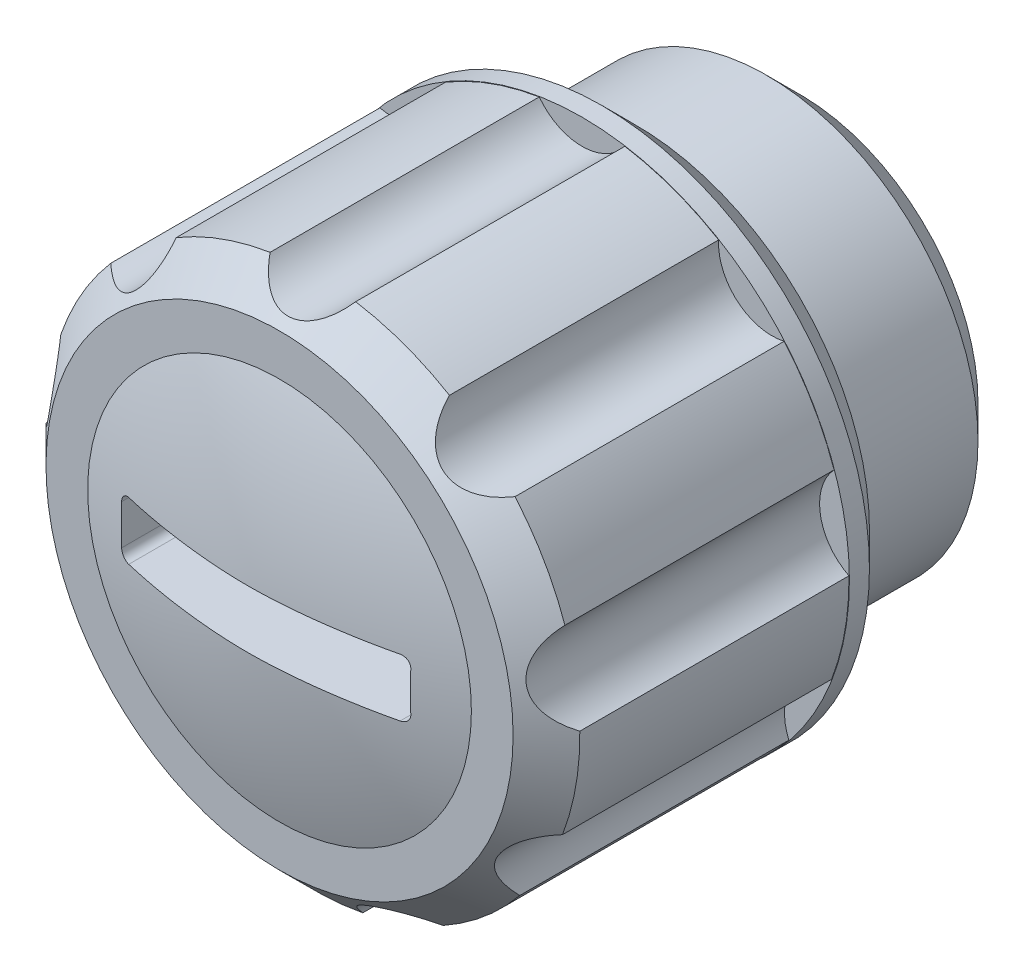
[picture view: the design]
ISO-10303-21;
HEADER;
FILE_DESCRIPTION(('STEP AP214'),'2;1');
FILE_NAME('part.step','',(''),(''),'','','');
FILE_SCHEMA(('AUTOMOTIVE_DESIGN { 1 0 10303 214 1 1 1 1 }'));
ENDSEC;
DATA;
#1=APPLICATION_CONTEXT('core data for automotive mechanical design processes');
#2=APPLICATION_PROTOCOL_DEFINITION('international standard','automotive_design',2000,#1);
#3=PRODUCT_CONTEXT('',#1,'mechanical');
#4=PRODUCT('Part','Part','',(#3));
#5=PRODUCT_RELATED_PRODUCT_CATEGORY('part','',(#4));
#6=PRODUCT_DEFINITION_FORMATION('','',#4);
#7=PRODUCT_DEFINITION_CONTEXT('part definition',#1,'design');
#8=PRODUCT_DEFINITION('design','',#6,#7);
#9=PRODUCT_DEFINITION_SHAPE('','',#8);
#10=(LENGTH_UNIT() NAMED_UNIT(*) SI_UNIT(.MILLI.,.METRE.));
#11=(NAMED_UNIT(*) PLANE_ANGLE_UNIT() SI_UNIT($,.RADIAN.));
#12=(NAMED_UNIT(*) SI_UNIT($,.STERADIAN.) SOLID_ANGLE_UNIT());
#13=UNCERTAINTY_MEASURE_WITH_UNIT(LENGTH_MEASURE(1.E-05),#10,'distance_accuracy_value','');
#14=(GEOMETRIC_REPRESENTATION_CONTEXT(3) GLOBAL_UNCERTAINTY_ASSIGNED_CONTEXT((#13)) GLOBAL_UNIT_ASSIGNED_CONTEXT((#10,
#11,#12)) REPRESENTATION_CONTEXT('',''));
#15=CARTESIAN_POINT('',(0.,0.,0.));
#16=DIRECTION('',(0.,0.,1.));
#17=DIRECTION('',(1.,0.,0.));
#18=AXIS2_PLACEMENT_3D('',#15,#16,#17);
#19=CARTESIAN_POINT('',(0.,0.,-2.24502330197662));
#20=DIRECTION('',(0.,0.,1.));
#21=DIRECTION('',(1.,0.,0.));
#22=AXIS2_PLACEMENT_3D('',#19,#20,#21);
#23=DEGENERATE_TOROIDAL_SURFACE('',#22,0.386362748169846,14.9999999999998,.F.);
#24=CARTESIAN_POINT('',(0.,0.,12.));
#25=DIRECTION('',(0.,0.,1.));
#26=DIRECTION('',(1.,0.,0.));
#27=AXIS2_PLACEMENT_3D('',#24,#25,#26);
#28=CIRCLE('',#27,4.3125);
#29=CARTESIAN_POINT('',(4.3125,0.,12.));
#30=VERTEX_POINT('',#29);
#31=EDGE_CURVE('E356',#30,#30,#28,.T.);
#32=ORIENTED_EDGE('',*,*,#31,.T.);
#33=EDGE_LOOP('',(#32));
#34=FACE_BOUND('',#33,.T.);
#35=CARTESIAN_POINT('',(-3.0498,-0.649999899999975,12.3398097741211));
#36=CARTESIAN_POINT('',(-3.06120822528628,-0.650019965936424,12.3371277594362));
#37=CARTESIAN_POINT('',(-3.07262553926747,-0.649047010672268,12.3344789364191));
#38=CARTESIAN_POINT('',(-3.09516164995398,-0.645167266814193,12.3293198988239));
#39=CARTESIAN_POINT('',(-3.10628037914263,-0.642260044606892,12.326809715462));
#40=CARTESIAN_POINT('',(-3.1279071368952,-0.634560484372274,12.3219992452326));
#41=CARTESIAN_POINT('',(-3.13841459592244,-0.629766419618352,12.3196991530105));
#42=CARTESIAN_POINT('',(-3.15848770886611,-0.618413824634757,12.3153819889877));
#43=CARTESIAN_POINT('',(-3.16805381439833,-0.611856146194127,12.3133647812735));
#44=CARTESIAN_POINT('',(-3.18579781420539,-0.59727066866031,12.3097075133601));
#45=CARTESIAN_POINT('',(-3.19399634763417,-0.589269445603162,12.308061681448));
#46=CARTESIAN_POINT('',(-3.20893719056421,-0.571941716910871,12.3051577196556));
#47=CARTESIAN_POINT('',(-3.2156793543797,-0.562615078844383,12.303899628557));
#48=CARTESIAN_POINT('',(-3.22732440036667,-0.543172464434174,12.3018421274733));
#49=CARTESIAN_POINT('',(-3.23227144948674,-0.533084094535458,12.3010314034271));
#50=CARTESIAN_POINT('',(-3.24041051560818,-0.512202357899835,12.2998457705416));
#51=CARTESIAN_POINT('',(-3.24360397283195,-0.501409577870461,12.299470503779));
#52=CARTESIAN_POINT('',(-3.24725089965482,-0.483746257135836,12.2992265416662));
#53=CARTESIAN_POINT('',(-3.24828749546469,-0.476992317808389,12.2992171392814));
#54=CARTESIAN_POINT('',(-3.24966526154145,-0.4634255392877,12.2993633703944));
#55=CARTESIAN_POINT('',(-3.25000743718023,-0.456612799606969,12.2995187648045));
#56=CARTESIAN_POINT('',(-3.24999990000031,-0.449800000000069,12.2997561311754));
#57=B_SPLINE_CURVE_WITH_KNOTS('',3,(#35,#36,#37,#38,#39,#40,#41,#42,#43,#44,#45,#46,#47,#48,#49,
#50,#51,#52,#53,#54,#55,#56),.UNSPECIFIED.,.F.,.F.,(4,2,2,2,2,2,2,2,2,2,4),(0.,
0.0351172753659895,0.0702424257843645,0.10539979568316,0.140540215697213,0.175089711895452,
0.209642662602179,0.243276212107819,0.276882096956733,0.297346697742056,0.317781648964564),.UNSPECIFIED.);
#58=CARTESIAN_POINT('',(-3.05,-0.65,12.3397627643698));
#59=VERTEX_POINT('',#58);
#60=CARTESIAN_POINT('',(-3.25,-0.45,12.2997491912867));
#61=VERTEX_POINT('',#60);
#62=EDGE_CURVE('E27',#59,#61,#57,.T.);
#63=ORIENTED_EDGE('',*,*,#62,.T.);
#64=CARTESIAN_POINT('',(-3.25,0.,12.3075320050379));
#65=CARTESIAN_POINT('',(-3.25,0.277728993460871,12.3075356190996));
#66=CARTESIAN_POINT('',(-3.25,0.555440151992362,12.2986179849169));
#67=CARTESIAN_POINT('',(-3.25,1.10971337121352,12.2631914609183));
#68=CARTESIAN_POINT('',(-3.25,1.38627553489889,12.2366841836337));
#69=CARTESIAN_POINT('',(-3.25,1.93745588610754,12.1665755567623));
#70=CARTESIAN_POINT('',(-3.25,2.21207222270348,12.122959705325));
#71=CARTESIAN_POINT('',(-3.25,2.75819405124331,12.019207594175));
#72=CARTESIAN_POINT('',(-3.25,3.02969897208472,11.9590683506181));
#73=CARTESIAN_POINT('',(-3.25,3.68907942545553,11.7923343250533));
#74=CARTESIAN_POINT('',(-3.25,4.07477310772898,11.6769874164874));
#75=CARTESIAN_POINT('',(-3.25,4.83507528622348,11.4141726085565));
#76=CARTESIAN_POINT('',(-3.25,5.20968196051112,11.2666994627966));
#77=CARTESIAN_POINT('',(-3.25,5.94561682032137,10.9408021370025));
#78=CARTESIAN_POINT('',(-3.25,6.30693188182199,10.7623483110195));
#79=CARTESIAN_POINT('',(-3.25,7.013278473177,10.3760839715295));
#80=CARTESIAN_POINT('',(-3.25,7.35831779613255,10.1682877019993));
#81=CARTESIAN_POINT('',(-3.25,8.03118455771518,9.72399493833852));
#82=CARTESIAN_POINT('',(-3.25,8.35894545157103,9.48739766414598));
#83=CARTESIAN_POINT('',(-3.25,8.99368126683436,8.98778857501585));
#84=CARTESIAN_POINT('',(-3.25,9.30065586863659,8.72477635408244));
#85=CARTESIAN_POINT('',(-3.25,9.8916546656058,8.1742495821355));
#86=CARTESIAN_POINT('',(-3.25,10.1756840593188,7.88674061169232));
#87=CARTESIAN_POINT('',(-3.25,10.7189336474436,7.2891687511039));
#88=CARTESIAN_POINT('',(-3.25,10.9781537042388,6.97910573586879));
#89=CARTESIAN_POINT('',(-3.25,11.4737062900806,6.33376323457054));
#90=CARTESIAN_POINT('',(-3.25,11.7096373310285,5.9981753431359));
#91=CARTESIAN_POINT('',(-3.25,12.1524595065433,5.30835452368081));
#92=CARTESIAN_POINT('',(-3.25,12.3593503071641,4.95412138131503));
#93=CARTESIAN_POINT('',(-3.25,12.7426542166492,4.22948724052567));
#94=CARTESIAN_POINT('',(-3.25,12.9190643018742,3.85908464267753));
#95=CARTESIAN_POINT('',(-3.25,13.2401398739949,3.10476845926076));
#96=CARTESIAN_POINT('',(-3.25,13.3848053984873,2.72085488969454));
#97=CARTESIAN_POINT('',(-3.25,13.6416809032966,1.94130139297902));
#98=CARTESIAN_POINT('',(-3.25,13.753812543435,1.5456356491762));
#99=CARTESIAN_POINT('',(-3.25,13.944363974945,0.746267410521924));
#100=CARTESIAN_POINT('',(-3.25,14.0227836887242,0.342564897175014));
#101=CARTESIAN_POINT('',(-3.25,14.1453548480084,-0.469998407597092));
#102=CARTESIAN_POINT('',(-3.25,14.1895071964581,-0.8788590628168));
#103=CARTESIAN_POINT('',(-3.25,14.2432347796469,-1.69884576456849));
#104=CARTESIAN_POINT('',(-3.25,14.2528100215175,-2.10997181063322));
#105=CARTESIAN_POINT('',(-3.25,14.2373111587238,-2.93180992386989));
#106=CARTESIAN_POINT('',(-3.25,14.2122168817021,-3.34252161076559));
#107=CARTESIAN_POINT('',(-3.25,14.1275207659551,-4.16037161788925));
#108=CARTESIAN_POINT('',(-3.25,14.0679189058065,-4.56750993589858));
#109=CARTESIAN_POINT('',(-3.25,13.9146256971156,-5.37533907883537));
#110=CARTESIAN_POINT('',(-3.25,13.8209326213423,-5.77602957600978));
#111=CARTESIAN_POINT('',(-3.25,13.6001207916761,-6.568092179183));
#112=CARTESIAN_POINT('',(-3.25,13.4730020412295,-6.95946428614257));
#113=CARTESIAN_POINT('',(-3.25,13.186232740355,-7.7301217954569));
#114=CARTESIAN_POINT('',(-3.25,13.0265808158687,-8.10940668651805));
#115=CARTESIAN_POINT('',(-3.25,12.6758786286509,-8.85317181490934));
#116=CARTESIAN_POINT('',(-3.25,12.4848283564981,-9.21765204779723));
#117=CARTESIAN_POINT('',(-3.25,12.072711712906,-9.92915798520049));
#118=CARTESIAN_POINT('',(-3.25,11.8516496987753,-10.2761862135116));
#119=CARTESIAN_POINT('',(-3.25,11.3810523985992,-10.9503675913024));
#120=CARTESIAN_POINT('',(-3.25,11.1315171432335,-11.2775207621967));
#121=CARTESIAN_POINT('',(-3.25,10.6059307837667,-11.9093794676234));
#122=CARTESIAN_POINT('',(-3.25,10.3298992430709,-12.2141012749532));
#123=CARTESIAN_POINT('',(-3.25,9.75311451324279,-12.7991756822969));
#124=CARTESIAN_POINT('',(-3.25,9.45236128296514,-13.0795282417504));
#125=CARTESIAN_POINT('',(-3.25,8.82813062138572,-13.6139441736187));
#126=CARTESIAN_POINT('',(-3.25,8.50464416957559,-13.8679970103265));
#127=CARTESIAN_POINT('',(-3.25,7.8373363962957,-14.3478241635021));
#128=CARTESIAN_POINT('',(-3.25,7.49351512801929,-14.573598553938));
#129=CARTESIAN_POINT('',(-3.25,6.78879460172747,-14.9946762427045));
#130=CARTESIAN_POINT('',(-3.25,6.42793763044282,-15.1900503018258));
#131=CARTESIAN_POINT('',(-3.25,5.69092259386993,-15.5494366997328));
#132=CARTESIAN_POINT('',(-3.25,5.31476441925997,-15.7134488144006));
#133=CARTESIAN_POINT('',(-3.25,4.54996490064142,-16.0086112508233));
#134=CARTESIAN_POINT('',(-3.25,4.16132971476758,-16.1397775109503));
#135=CARTESIAN_POINT('',(-3.25,3.37414151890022,-16.367940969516));
#136=CARTESIAN_POINT('',(-3.25,2.97558824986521,-16.4649372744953));
#137=CARTESIAN_POINT('',(-3.25,2.17796770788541,-16.6218590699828));
#138=CARTESIAN_POINT('',(-3.25,1.77901685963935,-16.682368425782));
#139=CARTESIAN_POINT('',(-3.25,1.17783289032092,-16.7458571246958));
#140=CARTESIAN_POINT('',(-3.25,0.976962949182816,-16.7624743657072));
#141=CARTESIAN_POINT('',(-3.25,0.574677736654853,-16.7864370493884));
#142=CARTESIAN_POINT('',(-3.25,0.373262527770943,-16.7937835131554));
#143=CARTESIAN_POINT('',(-3.25,-0.0296307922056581,-16.7991040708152));
#144=CARTESIAN_POINT('',(-3.25,-0.231108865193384,-16.7970810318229));
#145=CARTESIAN_POINT('',(-3.25,-0.633740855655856,-16.7837024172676));
#146=CARTESIAN_POINT('',(-3.25,-0.834894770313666,-16.7723467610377));
#147=CARTESIAN_POINT('',(-3.25,-1.43727360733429,-16.7244784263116));
#148=CARTESIAN_POINT('',(-3.25,-1.83748615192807,-16.6741652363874));
#149=CARTESIAN_POINT('',(-3.25,-2.60244344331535,-16.5434913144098));
#150=CARTESIAN_POINT('',(-3.25,-2.9676242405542,-16.465624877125));
#151=CARTESIAN_POINT('',(-3.25,-3.69061293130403,-16.2811099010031));
#152=CARTESIAN_POINT('',(-3.25,-4.04842149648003,-16.1744639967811));
#153=CARTESIAN_POINT('',(-3.25,-4.75476881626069,-15.9334225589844));
#154=CARTESIAN_POINT('',(-3.25,-5.10330243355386,-15.7990119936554));
#155=CARTESIAN_POINT('',(-3.25,-5.78889033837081,-15.5035347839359));
#156=CARTESIAN_POINT('',(-3.25,-6.12594408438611,-15.3424668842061));
#157=CARTESIAN_POINT('',(-3.25,-6.80932679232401,-14.9828170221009));
#158=CARTESIAN_POINT('',(-3.25,-7.15470066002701,-14.7824174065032));
#159=CARTESIAN_POINT('',(-3.25,-7.82779768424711,-14.3538815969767));
#160=CARTESIAN_POINT('',(-3.25,-8.15552013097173,-14.1257442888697));
#161=CARTESIAN_POINT('',(-3.25,-8.79107255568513,-13.6433774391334));
#162=CARTESIAN_POINT('',(-3.25,-9.09890611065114,-13.3891526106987));
#163=CARTESIAN_POINT('',(-3.25,-9.69269581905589,-12.8563257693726));
#164=CARTESIAN_POINT('',(-3.25,-9.97865187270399,-12.5777236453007));
#165=CARTESIAN_POINT('',(-3.25,-10.5337680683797,-11.9906483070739));
#166=CARTESIAN_POINT('',(-3.25,-10.8023152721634,-11.6815951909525));
#167=CARTESIAN_POINT('',(-3.25,-11.3125257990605,-11.0420356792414));
#168=CARTESIAN_POINT('',(-3.25,-11.5541885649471,-10.7115288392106));
#169=CARTESIAN_POINT('',(-3.25,-12.0089741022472,-10.0313455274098));
#170=CARTESIAN_POINT('',(-3.25,-12.2220918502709,-9.6816656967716));
#171=CARTESIAN_POINT('',(-3.25,-12.6182423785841,-8.96566280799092));
#172=CARTESIAN_POINT('',(-3.25,-12.8012752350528,-8.59933979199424));
#173=CARTESIAN_POINT('',(-3.25,-13.1366167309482,-7.85119993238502));
#174=CARTESIAN_POINT('',(-3.25,-13.2888047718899,-7.46932902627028));
#175=CARTESIAN_POINT('',(-3.25,-13.5604975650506,-6.69413124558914));
#176=CARTESIAN_POINT('',(-3.25,-13.680002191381,-6.30080432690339));
#177=CARTESIAN_POINT('',(-3.25,-13.885478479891,-5.505506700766));
#178=CARTESIAN_POINT('',(-3.25,-13.9714517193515,-5.10353640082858));
#179=CARTESIAN_POINT('',(-3.25,-14.1092657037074,-4.29378701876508));
#180=CARTESIAN_POINT('',(-3.25,-14.1611064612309,-3.88600793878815));
#181=CARTESIAN_POINT('',(-3.25,-14.2303212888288,-3.06715435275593));
#182=CARTESIAN_POINT('',(-3.25,-14.2476633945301,-2.65607714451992));
#183=CARTESIAN_POINT('',(-3.25,-14.2476620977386,-1.83392251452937));
#184=CARTESIAN_POINT('',(-3.25,-14.2303186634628,-1.42284509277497));
#185=CARTESIAN_POINT('',(-3.25,-14.1610682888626,-0.603603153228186));
#186=CARTESIAN_POINT('',(-3.25,-14.1091606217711,-0.195438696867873));
#187=CARTESIAN_POINT('',(-3.25,-13.9711485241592,0.615067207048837));
#188=CARTESIAN_POINT('',(-3.25,-13.885044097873,1.01740865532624));
#189=CARTESIAN_POINT('',(-3.25,-13.6792331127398,1.81346557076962));
#190=CARTESIAN_POINT('',(-3.25,-13.5595217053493,2.20717978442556));
#191=CARTESIAN_POINT('',(-3.25,-13.2873494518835,2.98312116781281));
#192=CARTESIAN_POINT('',(-3.25,-13.1348885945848,3.36534833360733));
#193=CARTESIAN_POINT('',(-3.25,-12.7982999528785,4.11558729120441));
#194=CARTESIAN_POINT('',(-3.25,-12.6141727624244,4.48359934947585));
#195=CARTESIAN_POINT('',(-3.25,-12.2155528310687,5.20279306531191));
#196=CARTESIAN_POINT('',(-3.25,-12.0010601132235,5.55397473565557));
#197=CARTESIAN_POINT('',(-3.25,-11.5433180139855,6.2368658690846));
#198=CARTESIAN_POINT('',(-3.25,-11.3000801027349,6.56858302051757));
#199=CARTESIAN_POINT('',(-3.25,-10.7864981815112,7.2103264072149));
#200=CARTESIAN_POINT('',(-3.25,-10.5161541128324,7.52035259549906));
#201=CARTESIAN_POINT('',(-3.25,-9.95025306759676,8.11650757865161));
#202=CARTESIAN_POINT('',(-3.25,-9.65469453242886,8.4026348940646));
#203=CARTESIAN_POINT('',(-3.25,-9.04046877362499,8.94890264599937));
#204=CARTESIAN_POINT('',(-3.25,-8.72180175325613,9.20904331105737));
#205=CARTESIAN_POINT('',(-3.25,-8.06411837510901,9.70105813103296));
#206=CARTESIAN_POINT('',(-3.25,-7.72513441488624,9.93297559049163));
#207=CARTESIAN_POINT('',(-3.25,-7.02875492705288,10.3672880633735));
#208=CARTESIAN_POINT('',(-3.25,-6.67135962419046,10.5696834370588));
#209=CARTESIAN_POINT('',(-3.25,-5.94066060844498,10.9433896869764));
#210=CARTESIAN_POINT('',(-3.25,-5.56735649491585,11.1146997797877));
#211=CARTESIAN_POINT('',(-3.25,-4.80749189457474,11.4247686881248));
#212=CARTESIAN_POINT('',(-3.25,-4.42093314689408,11.5635317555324));
#213=CARTESIAN_POINT('',(-3.25,-3.70318039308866,11.786627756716));
#214=CARTESIAN_POINT('',(-3.25,-3.37360154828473,11.876189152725));
#215=CARTESIAN_POINT('',(-3.25,-2.70877137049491,12.0309482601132));
#216=CARTESIAN_POINT('',(-3.25,-2.37352047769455,12.0961478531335));
#217=CARTESIAN_POINT('',(-3.25,-1.69957377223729,12.2010954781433));
#218=CARTESIAN_POINT('',(-3.25,-1.36088404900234,12.2408824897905));
#219=CARTESIAN_POINT('',(-3.25,-0.681453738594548,12.2940966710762));
#220=CARTESIAN_POINT('',(-3.25,-0.340713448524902,12.3075275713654));
#221=CARTESIAN_POINT('',(-3.25,0.,12.3075320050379));
#222=B_SPLINE_CURVE_WITH_KNOTS('',3,(#64,#65,#66,#67,#68,#69,#70,#71,#72,#73,#74,#75,#76,#77,
#78,#79,#80,#81,#82,#83,#84,#85,#86,#87,#88,#89,#90,#91,#92,#93,#94,#95,#96,#97,#98,#99,#100,
#101,#102,#103,#104,#105,#106,#107,#108,#109,#110,#111,#112,#113,#114,#115,#116,#117,#118,#119,
#120,#121,#122,#123,#124,#125,#126,#127,#128,#129,#130,#131,#132,#133,#134,#135,#136,#137,#138,
#139,#140,#141,#142,#143,#144,#145,#146,#147,#148,#149,#150,#151,#152,#153,#154,#155,#156,#157,
#158,#159,#160,#161,#162,#163,#164,#165,#166,#167,#168,#169,#170,#171,#172,#173,#174,#175,#176,
#177,#178,#179,#180,#181,#182,#183,#184,#185,#186,#187,#188,#189,#190,#191,#192,#193,#194,#195,
#196,#197,#198,#199,#200,#201,#202,#203,#204,#205,#206,#207,#208,#209,#210,#211,#212,#213,#214,
#215,#216,#217,#218,#219,#220,#221),.UNSPECIFIED.,.T.,.F.,(4,2,2,2,2,2,2,2,2,2,2,2,2,2,2,2,2,2,
2,2,2,2,2,2,2,2,2,2,2,2,2,2,2,2,2,2,2,2,2,2,2,2,2,2,2,2,2,2,2,2,2,2,2,2,2,2,2,2,2,2,2,2,2,2,2,2,
2,2,2,2,2,2,2,2,2,2,2,2,4),(0.,0.833015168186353,1.66595398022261,2.49960035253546,
3.33339736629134,4.53957397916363,5.74594771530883,6.95348227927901,8.16043266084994,
9.37173482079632,10.583055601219,11.7941011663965,13.0051534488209,14.2343656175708,
15.4635919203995,16.6929400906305,17.9222868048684,19.15456962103,20.3868552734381,
21.6191084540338,22.8513613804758,24.0843315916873,25.3173025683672,26.5503360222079,
27.7833693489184,29.01645476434,30.2495405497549,31.4824474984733,32.7153531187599,
33.9473553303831,35.1793595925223,36.4118555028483,37.6443481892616,38.8739277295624,
40.1035160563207,41.3325065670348,42.5615292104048,43.7703236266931,44.3748145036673,
44.97923879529,45.583478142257,46.1877227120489,47.3960010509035,48.5150195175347,
49.6339355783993,50.7534590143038,51.8730351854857,53.0695719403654,54.2661567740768,
55.4625258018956,56.658900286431,57.8857327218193,59.1125905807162,60.3396640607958,
61.5667344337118,62.7985136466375,64.0302976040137,65.2620236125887,66.4937491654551,
67.7266154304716,68.9594828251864,70.1923761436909,71.4252693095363,72.6583404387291,
73.8914119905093,75.1244604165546,76.3575079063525,77.5900650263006,78.8226248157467,
80.05526085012,81.2878860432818,82.5185954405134,83.7492898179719,84.9800152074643,
86.2105797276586,87.2343070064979,88.2579551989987,89.2800294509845,90.3019590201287),.UNSPECIFIED.);
#223=CARTESIAN_POINT('',(-3.25,0.45,12.2997491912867));
#224=VERTEX_POINT('',#223);
#225=EDGE_CURVE('E9',#61,#224,#222,.T.);
#226=ORIENTED_EDGE('',*,*,#225,.T.);
#227=CARTESIAN_POINT('',(-3.24999989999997,0.4498,12.2997561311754));
#228=CARTESIAN_POINT('',(-3.25002147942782,0.460776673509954,12.2993714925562));
#229=CARTESIAN_POINT('',(-3.24911882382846,0.471758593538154,12.2992032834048));
#230=CARTESIAN_POINT('',(-3.24553635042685,0.493412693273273,12.2992941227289));
#231=CARTESIAN_POINT('',(-3.24285883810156,0.504085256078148,12.299552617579));
#232=CARTESIAN_POINT('',(-3.23579622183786,0.524834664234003,12.3004904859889));
#233=CARTESIAN_POINT('',(-3.23141042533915,0.53491126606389,12.3011700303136));
#234=CARTESIAN_POINT('',(-3.22107038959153,0.554184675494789,12.3029273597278));
#235=CARTESIAN_POINT('',(-3.21511623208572,0.563381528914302,12.3040051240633));
#236=CARTESIAN_POINT('',(-3.20177417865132,0.580709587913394,12.3065339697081));
#237=CARTESIAN_POINT('',(-3.19437690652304,0.588833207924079,12.3079875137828));
#238=CARTESIAN_POINT('',(-3.17839327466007,0.603735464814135,12.3112205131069));
#239=CARTESIAN_POINT('',(-3.16980667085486,0.610513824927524,12.3130000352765));
#240=CARTESIAN_POINT('',(-3.15148706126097,0.62269653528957,12.3168763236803));
#241=CARTESIAN_POINT('',(-3.14173272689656,0.628066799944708,12.3189792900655));
#242=CARTESIAN_POINT('',(-3.12151319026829,0.637105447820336,12.3234120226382));
#243=CARTESIAN_POINT('',(-3.11104805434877,0.640773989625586,12.3257417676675));
#244=CARTESIAN_POINT('',(-3.09210451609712,0.64570458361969,12.3300193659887));
#245=CARTESIAN_POINT('',(-3.08370936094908,0.647322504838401,12.3319350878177));
#246=CARTESIAN_POINT('',(-3.06680849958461,0.649474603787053,12.3358309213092));
#247=CARTESIAN_POINT('',(-3.05830296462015,0.650010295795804,12.3378109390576));
#248=CARTESIAN_POINT('',(-3.0498,0.649999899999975,12.3398097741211));
#249=B_SPLINE_CURVE_WITH_KNOTS('',3,(#227,#228,#229,#230,#231,#232,#233,#234,#235,#236,#237,
#238,#239,#240,#241,#242,#243,#244,#245,#246,#247,#248),.UNSPECIFIED.,.F.,.F.,(4,2,2,2,2,2,2,2,
2,2,4),(0.,0.0329053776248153,0.0657680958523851,0.0986441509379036,0.13151849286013,
0.1646140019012,0.197716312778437,0.231558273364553,0.265397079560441,0.291616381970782,
0.31779897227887),.UNSPECIFIED.);
#250=CARTESIAN_POINT('',(-3.04999999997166,0.65,12.3397627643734));
#251=VERTEX_POINT('',#250);
#252=EDGE_CURVE('E419',#224,#251,#249,.T.);
#253=ORIENTED_EDGE('',*,*,#252,.T.);
#254=CARTESIAN_POINT('',(0.,0.65,12.7191322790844));
#255=CARTESIAN_POINT('',(0.108520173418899,0.65,12.7191277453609));
#256=CARTESIAN_POINT('',(0.217041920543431,0.65,12.7172094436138));
#257=CARTESIAN_POINT('',(0.433997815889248,0.65,12.7099981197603));
#258=CARTESIAN_POINT('',(0.542431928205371,0.65,12.7047040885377));
#259=CARTESIAN_POINT('',(0.759555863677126,0.65,12.6912706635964));
#260=CARTESIAN_POINT('',(0.868244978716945,0.65,12.6831199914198));
#261=CARTESIAN_POINT('',(1.08539837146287,0.65,12.6642185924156));
#262=CARTESIAN_POINT('',(1.19386263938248,0.65,12.6534677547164));
#263=CARTESIAN_POINT('',(1.51887735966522,0.65,12.6174925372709));
#264=CARTESIAN_POINT('',(1.73502604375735,0.65,12.5885469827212));
#265=CARTESIAN_POINT('',(2.16611297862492,0.65,12.5210525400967));
#266=CARTESIAN_POINT('',(2.38104917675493,0.65,12.4824906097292));
#267=CARTESIAN_POINT('',(2.80901885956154,0.65,12.3959374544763));
#268=CARTESIAN_POINT('',(3.02205219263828,0.65,12.3479454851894));
#269=CARTESIAN_POINT('',(3.64169701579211,0.65,12.1939819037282));
#270=CARTESIAN_POINT('',(4.04525595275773,0.65,12.0754170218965));
#271=CARTESIAN_POINT('',(4.84106887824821,0.65,11.804706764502));
#272=CARTESIAN_POINT('',(5.23331827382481,0.65,11.6525479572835));
#273=CARTESIAN_POINT('',(6.00390173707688,0.65,11.3156534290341));
#274=CARTESIAN_POINT('',(6.382226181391,0.65,11.1308956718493));
#275=CARTESIAN_POINT('',(7.12194189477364,0.65,10.7302214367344));
#276=CARTESIAN_POINT('',(7.48333496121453,0.65,10.5143082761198));
#277=CARTESIAN_POINT('',(8.18679974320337,0.65,10.0527629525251));
#278=CARTESIAN_POINT('',(8.52886465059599,0.65,9.80712041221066));
#279=CARTESIAN_POINT('',(9.19111928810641,0.65,9.28791513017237));
#280=CARTESIAN_POINT('',(9.51130841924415,0.65,9.01435162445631));
#281=CARTESIAN_POINT('',(10.1275007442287,0.65,8.44128082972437));
#282=CARTESIAN_POINT('',(10.4235063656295,0.65,8.14177615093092));
#283=CARTESIAN_POINT('',(10.9892674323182,0.65,7.51892636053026));
#284=CARTESIAN_POINT('',(11.2590230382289,0.65,7.19558139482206));
#285=CARTESIAN_POINT('',(11.7706885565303,0.65,6.52693164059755));
#286=CARTESIAN_POINT('',(12.012563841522,0.65,6.18160035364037));
#287=CARTESIAN_POINT('',(12.4663665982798,0.65,5.47179015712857));
#288=CARTESIAN_POINT('',(12.6782939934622,0.65,5.10731119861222));
#289=CARTESIAN_POINT('',(13.0706918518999,0.65,4.36180202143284));
#290=CARTESIAN_POINT('',(13.2511627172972,0.65,3.98077201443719));
#291=CARTESIAN_POINT('',(13.5793682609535,0.65,3.20486500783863));
#292=CARTESIAN_POINT('',(13.7271029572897,0.65,2.80998801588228));
#293=CARTESIAN_POINT('',(13.988800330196,0.65,2.00915107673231));
#294=CARTESIAN_POINT('',(14.1027594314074,0.65,1.60318996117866));
#295=CARTESIAN_POINT('',(14.2960746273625,0.65,0.783110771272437));
#296=CARTESIAN_POINT('',(14.3754307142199,0.65,0.368992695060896));
#297=CARTESIAN_POINT('',(14.498977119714,0.65,-0.464465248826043));
#298=CARTESIAN_POINT('',(14.5431666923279,0.65,-0.883805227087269));
#299=CARTESIAN_POINT('',(14.596063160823,0.65,-1.72471716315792));
#300=CARTESIAN_POINT('',(14.6047700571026,0.65,-2.1462891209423));
#301=CARTESIAN_POINT('',(14.5866390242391,0.65,-2.98868011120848));
#302=CARTESIAN_POINT('',(14.5598000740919,0.65,-3.40949912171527));
#303=CARTESIAN_POINT('',(14.4707663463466,0.65,-4.24738022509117));
#304=CARTESIAN_POINT('',(14.4085715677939,0.65,-4.66444231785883));
#305=CARTESIAN_POINT('',(14.2492707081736,0.65,-5.49183187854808));
#306=CARTESIAN_POINT('',(14.1521656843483,0.65,-5.90215955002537));
#307=CARTESIAN_POINT('',(13.92373427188,0.65,-6.7131760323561));
#308=CARTESIAN_POINT('',(13.7924078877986,0.65,-7.11386484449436));
#309=CARTESIAN_POINT('',(13.4964692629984,0.65,-7.90274953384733));
#310=CARTESIAN_POINT('',(13.3318574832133,0.65,-8.29094558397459));
#311=CARTESIAN_POINT('',(12.9705168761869,0.65,-9.05209088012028));
#312=CARTESIAN_POINT('',(12.7737880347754,0.65,-9.42504011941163));
#313=CARTESIAN_POINT('',(12.3495993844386,0.65,-10.1530610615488));
#314=CARTESIAN_POINT('',(12.1221378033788,0.65,-10.5081317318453));
#315=CARTESIAN_POINT('',(11.6381096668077,0.65,-11.1978469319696));
#316=CARTESIAN_POINT('',(11.3815431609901,0.65,-11.5324914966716));
#317=CARTESIAN_POINT('',(10.8411381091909,0.65,-12.1789638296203));
#318=CARTESIAN_POINT('',(10.5573005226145,0.65,-12.4907923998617));
#319=CARTESIAN_POINT('',(9.9643609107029,0.65,-13.0894299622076));
#320=CARTESIAN_POINT('',(9.65525870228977,0.65,-13.3762387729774));
#321=CARTESIAN_POINT('',(9.01399860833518,0.65,-13.9227850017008));
#322=CARTESIAN_POINT('',(8.681841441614,0.65,-14.1825232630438));
#323=CARTESIAN_POINT('',(7.99683299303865,0.65,-14.6730822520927));
#324=CARTESIAN_POINT('',(7.64398231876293,0.65,-14.9039038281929));
#325=CARTESIAN_POINT('',(6.92002553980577,0.65,-15.335028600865));
#326=CARTESIAN_POINT('',(6.5489163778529,0.65,-15.5353266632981));
#327=CARTESIAN_POINT('',(5.79113277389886,0.65,-15.903924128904));
#328=CARTESIAN_POINT('',(5.40445847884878,0.65,-16.0722238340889));
#329=CARTESIAN_POINT('',(4.61839618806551,0.65,-16.3755712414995));
#330=CARTESIAN_POINT('',(4.21901109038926,0.65,-16.5106264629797));
#331=CARTESIAN_POINT('',(3.41037855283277,0.65,-16.7464936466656));
#332=CARTESIAN_POINT('',(3.00113546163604,0.65,-16.8473204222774));
#333=CARTESIAN_POINT('',(2.37474825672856,0.65,-16.9737106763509));
#334=CARTESIAN_POINT('',(2.16011736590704,0.65,-17.0121235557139));
#335=CARTESIAN_POINT('',(1.72933145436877,0.65,-17.0793970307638));
#336=CARTESIAN_POINT('',(1.51317639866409,0.65,-17.1082574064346));
#337=CARTESIAN_POINT('',(1.1883245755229,0.65,-17.1440821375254));
#338=CARTESIAN_POINT('',(1.08002619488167,0.65,-17.1547737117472));
#339=CARTESIAN_POINT('',(0.863198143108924,0.65,-17.1735629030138));
#340=CARTESIAN_POINT('',(0.754668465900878,0.65,-17.1816604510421));
#341=CARTESIAN_POINT('',(0.537464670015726,0.65,-17.1950151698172));
#342=CARTESIAN_POINT('',(0.42879060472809,0.65,-17.2002731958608));
#343=CARTESIAN_POINT('',(0.211334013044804,0.65,-17.20738850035));
#344=CARTESIAN_POINT('',(0.102551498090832,0.65,-17.2092461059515));
#345=CARTESIAN_POINT('',(-0.098037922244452,0.65,-17.2091183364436));
#346=CARTESIAN_POINT('',(-0.189845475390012,0.65,-17.2076873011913));
#347=CARTESIAN_POINT('',(-0.373392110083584,0.65,-17.2023544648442));
#348=CARTESIAN_POINT('',(-0.465131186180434,0.65,-17.1984524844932));
#349=CARTESIAN_POINT('',(-0.648525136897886,0.65,-17.1885366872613));
#350=CARTESIAN_POINT('',(-0.740179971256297,0.65,-17.1825221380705));
#351=CARTESIAN_POINT('',(-0.923340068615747,0.65,-17.1685825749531));
#352=CARTESIAN_POINT('',(-1.01484533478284,0.65,-17.1606576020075));
#353=CARTESIAN_POINT('',(-1.28932831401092,0.65,-17.1341570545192));
#354=CARTESIAN_POINT('',(-1.47205047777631,0.65,-17.1128685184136));
#355=CARTESIAN_POINT('',(-1.83651738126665,0.65,-17.0634122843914));
#356=CARTESIAN_POINT('',(-2.01826229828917,0.65,-17.0352458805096));
#357=CARTESIAN_POINT('',(-2.38129600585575,0.65,-16.9720306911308));
#358=CARTESIAN_POINT('',(-2.56258014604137,0.65,-16.936955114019));
#359=CARTESIAN_POINT('',(-2.92371751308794,0.65,-16.8600846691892));
#360=CARTESIAN_POINT('',(-3.10357066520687,0.65,-16.8182894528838));
#361=CARTESIAN_POINT('',(-3.64033450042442,0.65,-16.6830040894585));
#362=CARTESIAN_POINT('',(-3.9947892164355,0.65,-16.57955495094));
#363=CARTESIAN_POINT('',(-4.71178689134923,0.65,-16.3411791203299));
#364=CARTESIAN_POINT('',(-5.07390702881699,0.65,-16.2049845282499));
#365=CARTESIAN_POINT('',(-5.78663052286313,0.65,-15.9049349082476));
#366=CARTESIAN_POINT('',(-6.13723052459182,0.65,-15.7410719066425));
#367=CARTESIAN_POINT('',(-6.82400082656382,0.65,-15.3870663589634));
#368=CARTESIAN_POINT('',(-7.16019896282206,0.65,-15.1969778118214));
#369=CARTESIAN_POINT('',(-7.81689468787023,0.65,-14.7914249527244));
#370=CARTESIAN_POINT('',(-8.13739298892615,0.65,-14.5759617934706));
#371=CARTESIAN_POINT('',(-8.7889588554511,0.65,-14.1003791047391));
#372=CARTESIAN_POINT('',(-9.118369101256,0.65,-13.8379842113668));
#373=CARTESIAN_POINT('',(-9.75396306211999,0.65,-13.2863857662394));
#374=CARTESIAN_POINT('',(-10.0601446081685,0.65,-12.9971797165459));
#375=CARTESIAN_POINT('',(-10.6473742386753,0.65,-12.3937305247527));
#376=CARTESIAN_POINT('',(-10.9283974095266,0.65,-12.0794631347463));
#377=CARTESIAN_POINT('',(-11.4629667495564,0.65,-11.4283824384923));
#378=CARTESIAN_POINT('',(-11.716513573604,0.65,-11.0915696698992));
#379=CARTESIAN_POINT('',(-12.1943966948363,0.65,-10.3976989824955));
#380=CARTESIAN_POINT('',(-12.4187257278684,0.65,-10.0406360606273));
#381=CARTESIAN_POINT('',(-12.836505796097,0.65,-9.30887820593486));
#382=CARTESIAN_POINT('',(-13.0299566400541,0.65,-8.93418316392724));
#383=CARTESIAN_POINT('',(-13.3845512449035,0.65,-8.1699401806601));
#384=CARTESIAN_POINT('',(-13.5457045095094,0.65,-7.78039664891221));
#385=CARTESIAN_POINT('',(-13.8346300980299,0.65,-6.98912166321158));
#386=CARTESIAN_POINT('',(-13.9624024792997,0.65,-6.58739023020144));
#387=CARTESIAN_POINT('',(-14.1836800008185,0.65,-5.77451590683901));
#388=CARTESIAN_POINT('',(-14.2771785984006,0.65,-5.36337123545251));
#389=CARTESIAN_POINT('',(-14.4292098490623,0.65,-4.53466691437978));
#390=CARTESIAN_POINT('',(-14.487742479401,0.65,-4.11710726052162));
#391=CARTESIAN_POINT('',(-14.5694291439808,0.65,-3.27850601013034));
#392=CARTESIAN_POINT('',(-14.5925801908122,0.65,-2.85746412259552));
#393=CARTESIAN_POINT('',(-14.6033296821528,0.65,-2.01492679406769));
#394=CARTESIAN_POINT('',(-14.5909281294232,0.65,-1.59343135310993));
#395=CARTESIAN_POINT('',(-14.5306606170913,0.65,-0.752983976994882));
#396=CARTESIAN_POINT('',(-14.4827946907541,0.65,-0.334032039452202));
#397=CARTESIAN_POINT('',(-14.351938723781,0.65,0.49835010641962));
#398=CARTESIAN_POINT('',(-14.2689486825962,0.65,0.911780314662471));
#399=CARTESIAN_POINT('',(-14.0684388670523,0.65,1.73016147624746));
#400=CARTESIAN_POINT('',(-13.9509206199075,0.65,2.13511280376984));
#401=CARTESIAN_POINT('',(-13.6821883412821,0.65,2.93367609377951));
#402=CARTESIAN_POINT('',(-13.5309743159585,0.65,3.32728805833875));
#403=CARTESIAN_POINT('',(-13.1959267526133,0.65,4.10037092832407));
#404=CARTESIAN_POINT('',(-13.0120935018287,0.65,4.47984195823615));
#405=CARTESIAN_POINT('',(-12.6131130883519,0.65,5.22194896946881));
#406=CARTESIAN_POINT('',(-12.3979659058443,0.65,5.58458494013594));
#407=CARTESIAN_POINT('',(-11.9378740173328,0.65,6.29046298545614));
#408=CARTESIAN_POINT('',(-11.6929276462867,0.65,6.63370397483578));
#409=CARTESIAN_POINT('',(-11.1749886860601,0.65,7.29832838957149));
#410=CARTESIAN_POINT('',(-10.9019961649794,0.65,7.61971186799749));
#411=CARTESIAN_POINT('',(-10.3299256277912,0.65,8.23831388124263));
#412=CARTESIAN_POINT('',(-10.0308495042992,0.65,8.53553416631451));
#413=CARTESIAN_POINT('',(-9.40871715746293,0.65,9.10372430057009));
#414=CARTESIAN_POINT('',(-9.08566069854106,0.65,9.37469389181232));
#415=CARTESIAN_POINT('',(-8.41785441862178,0.65,9.88845978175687));
#416=CARTESIAN_POINT('',(-8.07310383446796,0.65,10.1312550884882));
#417=CARTESIAN_POINT('',(-7.36438263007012,0.65,10.5869228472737));
#418=CARTESIAN_POINT('',(-7.00041275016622,0.65,10.799796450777));
#419=CARTESIAN_POINT('',(-6.25574024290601,0.65,11.1941576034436));
#420=CARTESIAN_POINT('',(-5.87503367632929,0.65,11.3756377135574));
#421=CARTESIAN_POINT('',(-5.09960838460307,0.65,11.7058730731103));
#422=CARTESIAN_POINT('',(-4.70488757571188,0.65,11.8546234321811));
#423=CARTESIAN_POINT('',(-3.90465475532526,0.65,12.118151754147));
#424=CARTESIAN_POINT('',(-3.49915214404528,0.65,12.2329583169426));
#425=CARTESIAN_POINT('',(-2.67985286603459,0.65,12.4278850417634));
#426=CARTESIAN_POINT('',(-2.26605705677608,0.65,12.5080087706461));
#427=CARTESIAN_POINT('',(-1.69646981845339,0.65,12.5931341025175));
#428=CARTESIAN_POINT('',(-1.54287539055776,0.65,12.6136119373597));
#429=CARTESIAN_POINT('',(-1.23513895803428,0.65,12.6495835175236));
#430=CARTESIAN_POINT('',(-1.08099712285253,0.65,12.6650786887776));
#431=CARTESIAN_POINT('',(-0.772511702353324,0.65,12.6907884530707));
#432=CARTESIAN_POINT('',(-0.618168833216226,0.65,12.7010114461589));
#433=CARTESIAN_POINT('',(-0.386454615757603,0.65,12.7116612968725));
#434=CARTESIAN_POINT('',(-0.309189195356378,0.65,12.7144304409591));
#435=CARTESIAN_POINT('',(-0.154616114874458,0.65,12.7181675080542));
#436=CARTESIAN_POINT('',(-0.0773084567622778,0.65,12.7191355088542));
#437=CARTESIAN_POINT('',(0.,0.65,12.7191322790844));
#438=B_SPLINE_CURVE_WITH_KNOTS('',3,(#254,#255,#256,#257,#258,#259,#260,#261,#262,#263,#264,
#265,#266,#267,#268,#269,#270,#271,#272,#273,#274,#275,#276,#277,#278,#279,#280,#281,#282,#283,
#284,#285,#286,#287,#288,#289,#290,#291,#292,#293,#294,#295,#296,#297,#298,#299,#300,#301,#302,
#303,#304,#305,#306,#307,#308,#309,#310,#311,#312,#313,#314,#315,#316,#317,#318,#319,#320,#321,
#322,#323,#324,#325,#326,#327,#328,#329,#330,#331,#332,#333,#334,#335,#336,#337,#338,#339,#340,
#341,#342,#343,#344,#345,#346,#347,#348,#349,#350,#351,#352,#353,#354,#355,#356,#357,#358,#359,
#360,#361,#362,#363,#364,#365,#366,#367,#368,#369,#370,#371,#372,#373,#374,#375,#376,#377,#378,
#379,#380,#381,#382,#383,#384,#385,#386,#387,#388,#389,#390,#391,#392,#393,#394,#395,#396,#397,
#398,#399,#400,#401,#402,#403,#404,#405,#406,#407,#408,#409,#410,#411,#412,#413,#414,#415,#416,
#417,#418,#419,#420,#421,#422,#423,#424,#425,#426,#427,#428,#429,#430,#431,#432,#433,#434,#435,
#436,#437),.UNSPECIFIED.,.T.,.F.,(4,2,2,2,2,2,2,2,2,2,2,2,2,2,2,2,2,2,2,2,2,2,2,2,2,2,2,2,2,2,2,
2,2,2,2,2,2,2,2,2,2,2,2,2,2,2,2,2,2,2,2,2,2,2,2,2,2,2,2,2,2,2,2,2,2,2,2,2,2,2,2,2,2,2,2,2,2,2,2,
2,2,2,2,2,2,2,2,2,2,2,2,4),(0.,0.325550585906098,0.651198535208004,0.978146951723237,
1.30510931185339,1.95910516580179,2.61399287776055,3.26893230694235,4.52915364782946,
5.78987977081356,7.05146140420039,8.31290880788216,9.57479780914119,10.8367213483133,
12.0985180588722,13.3603070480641,14.6236466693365,15.8869895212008,17.1503162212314,
18.4136422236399,19.6771019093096,20.9405618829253,22.2040486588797,23.4675354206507,
24.7310584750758,25.9945815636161,27.2580663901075,28.5215510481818,29.7850182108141,
31.048485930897,32.3120265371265,33.5755649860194,34.8390589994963,36.1025621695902,
37.366025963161,38.6294526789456,39.8930916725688,41.1567187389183,42.4200597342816,
43.6828532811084,44.3368060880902,44.9907739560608,45.3172246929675,45.64368411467,
45.9700451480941,46.296374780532,46.5717928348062,46.8472308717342,47.1227644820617,
47.3982921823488,47.9500163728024,48.5016368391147,49.0554399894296,49.6092718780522,
50.7159038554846,51.8754142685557,53.0352594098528,54.1927510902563,55.3501902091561,
56.6121057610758,57.8741390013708,59.1374084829,60.4006478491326,61.6642006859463,
62.9277613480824,64.1909496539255,65.4541357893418,66.7175629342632,67.9809909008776,
69.2445255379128,70.5080600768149,71.7715934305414,73.0351268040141,74.2986042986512,
75.5620815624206,76.8255477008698,78.0890146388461,79.3525522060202,80.6160867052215,
81.8795295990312,83.1429849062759,84.4064846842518,85.6699358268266,86.9336859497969,
88.1976247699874,89.4604955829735,90.7232364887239,91.1880404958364,91.6527113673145,
92.1166395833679,92.3485678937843,92.5804861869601),.UNSPECIFIED.);
#439=CARTESIAN_POINT('',(3.05,0.65,12.3397627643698));
#440=VERTEX_POINT('',#439);
#441=EDGE_CURVE('E429',#251,#440,#438,.T.);
#442=ORIENTED_EDGE('',*,*,#441,.T.);
#443=CARTESIAN_POINT('',(3.0498,0.649999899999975,12.3398097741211));
#444=CARTESIAN_POINT('',(3.06120822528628,0.650019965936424,12.3371277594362));
#445=CARTESIAN_POINT('',(3.07262553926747,0.649047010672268,12.3344789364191));
#446=CARTESIAN_POINT('',(3.09516164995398,0.645167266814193,12.3293198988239));
#447=CARTESIAN_POINT('',(3.10628037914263,0.642260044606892,12.326809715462));
#448=CARTESIAN_POINT('',(3.1279071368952,0.634560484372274,12.3219992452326));
#449=CARTESIAN_POINT('',(3.13841459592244,0.629766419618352,12.3196991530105));
#450=CARTESIAN_POINT('',(3.15848770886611,0.618413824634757,12.3153819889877));
#451=CARTESIAN_POINT('',(3.16805381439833,0.611856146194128,12.3133647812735));
#452=CARTESIAN_POINT('',(3.18579781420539,0.597270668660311,12.3097075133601));
#453=CARTESIAN_POINT('',(3.19399634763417,0.589269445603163,12.308061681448));
#454=CARTESIAN_POINT('',(3.20893719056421,0.571941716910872,12.3051577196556));
#455=CARTESIAN_POINT('',(3.2156793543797,0.562615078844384,12.303899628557));
#456=CARTESIAN_POINT('',(3.22732440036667,0.543172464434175,12.3018421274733));
#457=CARTESIAN_POINT('',(3.23227144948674,0.533084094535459,12.3010314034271));
#458=CARTESIAN_POINT('',(3.24041051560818,0.512202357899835,12.2998457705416));
#459=CARTESIAN_POINT('',(3.24360397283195,0.501409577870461,12.299470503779));
#460=CARTESIAN_POINT('',(3.24725089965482,0.483746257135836,12.2992265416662));
#461=CARTESIAN_POINT('',(3.24828749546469,0.476992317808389,12.2992171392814));
#462=CARTESIAN_POINT('',(3.24966526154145,0.4634255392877,12.2993633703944));
#463=CARTESIAN_POINT('',(3.25000743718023,0.456612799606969,12.2995187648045));
#464=CARTESIAN_POINT('',(3.24999990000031,0.449800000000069,12.2997561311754));
#465=B_SPLINE_CURVE_WITH_KNOTS('',3,(#443,#444,#445,#446,#447,#448,#449,#450,#451,#452,#453,
#454,#455,#456,#457,#458,#459,#460,#461,#462,#463,#464),.UNSPECIFIED.,.F.,.F.,(4,2,2,2,2,2,2,2,
2,2,4),(0.,0.0351172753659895,0.0702424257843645,0.105399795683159,0.140540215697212,
0.175089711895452,0.209642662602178,0.243276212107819,0.276882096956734,0.297346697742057,
0.317781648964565),.UNSPECIFIED.);
#466=CARTESIAN_POINT('',(3.25,0.45,12.2997491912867));
#467=VERTEX_POINT('',#466);
#468=EDGE_CURVE('E436',#440,#467,#465,.T.);
#469=ORIENTED_EDGE('',*,*,#468,.T.);
#470=CARTESIAN_POINT('',(3.25,0.,12.3075320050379));
#471=CARTESIAN_POINT('',(3.25,-0.277728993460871,12.3075356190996));
#472=CARTESIAN_POINT('',(3.25,-0.555440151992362,12.2986179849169));
#473=CARTESIAN_POINT('',(3.25,-1.10971337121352,12.2631914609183));
#474=CARTESIAN_POINT('',(3.25,-1.38627553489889,12.2366841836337));
#475=CARTESIAN_POINT('',(3.25,-1.93745588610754,12.1665755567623));
#476=CARTESIAN_POINT('',(3.25,-2.21207222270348,12.122959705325));
#477=CARTESIAN_POINT('',(3.25,-2.75819405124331,12.019207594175));
#478=CARTESIAN_POINT('',(3.25,-3.02969897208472,11.9590683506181));
#479=CARTESIAN_POINT('',(3.25,-3.68907942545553,11.7923343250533));
#480=CARTESIAN_POINT('',(3.25,-4.07477310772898,11.6769874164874));
#481=CARTESIAN_POINT('',(3.25,-4.83507528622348,11.4141726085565));
#482=CARTESIAN_POINT('',(3.25,-5.20968196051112,11.2666994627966));
#483=CARTESIAN_POINT('',(3.25,-5.94561682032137,10.9408021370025));
#484=CARTESIAN_POINT('',(3.25,-6.30693188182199,10.7623483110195));
#485=CARTESIAN_POINT('',(3.25,-7.013278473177,10.3760839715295));
#486=CARTESIAN_POINT('',(3.25,-7.35831779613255,10.1682877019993));
#487=CARTESIAN_POINT('',(3.25,-8.03118455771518,9.72399493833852));
#488=CARTESIAN_POINT('',(3.25,-8.35894545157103,9.48739766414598));
#489=CARTESIAN_POINT('',(3.25,-8.99368126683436,8.98778857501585));
#490=CARTESIAN_POINT('',(3.25,-9.30065586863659,8.72477635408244));
#491=CARTESIAN_POINT('',(3.25,-9.8916546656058,8.1742495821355));
#492=CARTESIAN_POINT('',(3.25,-10.1756840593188,7.88674061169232));
#493=CARTESIAN_POINT('',(3.25,-10.7189336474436,7.2891687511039));
#494=CARTESIAN_POINT('',(3.25,-10.9781537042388,6.97910573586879));
#495=CARTESIAN_POINT('',(3.25,-11.4737062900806,6.33376323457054));
#496=CARTESIAN_POINT('',(3.25,-11.7096373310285,5.9981753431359));
#497=CARTESIAN_POINT('',(3.25,-12.1524595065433,5.30835452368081));
#498=CARTESIAN_POINT('',(3.25,-12.3593503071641,4.95412138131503));
#499=CARTESIAN_POINT('',(3.25,-12.7426542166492,4.22948724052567));
#500=CARTESIAN_POINT('',(3.25,-12.9190643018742,3.85908464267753));
#501=CARTESIAN_POINT('',(3.25,-13.2401398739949,3.10476845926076));
#502=CARTESIAN_POINT('',(3.25,-13.3848053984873,2.72085488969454));
#503=CARTESIAN_POINT('',(3.25,-13.6416809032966,1.94130139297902));
#504=CARTESIAN_POINT('',(3.25,-13.753812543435,1.5456356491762));
#505=CARTESIAN_POINT('',(3.25,-13.944363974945,0.746267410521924));
#506=CARTESIAN_POINT('',(3.25,-14.0227836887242,0.342564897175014));
#507=CARTESIAN_POINT('',(3.25,-14.1453548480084,-0.469998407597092));
#508=CARTESIAN_POINT('',(3.25,-14.1895071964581,-0.8788590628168));
#509=CARTESIAN_POINT('',(3.25,-14.2432347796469,-1.69884576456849));
#510=CARTESIAN_POINT('',(3.25,-14.2528100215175,-2.10997181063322));
#511=CARTESIAN_POINT('',(3.25,-14.2373111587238,-2.93180992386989));
#512=CARTESIAN_POINT('',(3.25,-14.2122168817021,-3.34252161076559));
#513=CARTESIAN_POINT('',(3.25,-14.1275207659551,-4.16037161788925));
#514=CARTESIAN_POINT('',(3.25,-14.0679189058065,-4.56750993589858));
#515=CARTESIAN_POINT('',(3.25,-13.9146256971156,-5.37533907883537));
#516=CARTESIAN_POINT('',(3.25,-13.8209326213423,-5.77602957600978));
#517=CARTESIAN_POINT('',(3.25,-13.6001207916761,-6.568092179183));
#518=CARTESIAN_POINT('',(3.25,-13.4730020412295,-6.95946428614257));
#519=CARTESIAN_POINT('',(3.25,-13.186232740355,-7.7301217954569));
#520=CARTESIAN_POINT('',(3.25,-13.0265808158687,-8.10940668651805));
#521=CARTESIAN_POINT('',(3.25,-12.6758786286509,-8.85317181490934));
#522=CARTESIAN_POINT('',(3.25,-12.4848283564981,-9.21765204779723));
#523=CARTESIAN_POINT('',(3.25,-12.072711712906,-9.92915798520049));
#524=CARTESIAN_POINT('',(3.25,-11.8516496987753,-10.2761862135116));
#525=CARTESIAN_POINT('',(3.25,-11.3810523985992,-10.9503675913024));
#526=CARTESIAN_POINT('',(3.25,-11.1315171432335,-11.2775207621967));
#527=CARTESIAN_POINT('',(3.25,-10.6059307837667,-11.9093794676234));
#528=CARTESIAN_POINT('',(3.25,-10.3298992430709,-12.2141012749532));
#529=CARTESIAN_POINT('',(3.25,-9.75311451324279,-12.7991756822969));
#530=CARTESIAN_POINT('',(3.25,-9.45236128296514,-13.0795282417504));
#531=CARTESIAN_POINT('',(3.25,-8.82813062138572,-13.6139441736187));
#532=CARTESIAN_POINT('',(3.25,-8.50464416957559,-13.8679970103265));
#533=CARTESIAN_POINT('',(3.25,-7.8373363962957,-14.3478241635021));
#534=CARTESIAN_POINT('',(3.25,-7.49351512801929,-14.573598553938));
#535=CARTESIAN_POINT('',(3.25,-6.78879460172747,-14.9946762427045));
#536=CARTESIAN_POINT('',(3.25,-6.42793763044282,-15.1900503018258));
#537=CARTESIAN_POINT('',(3.25,-5.69092259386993,-15.5494366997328));
#538=CARTESIAN_POINT('',(3.25,-5.31476441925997,-15.7134488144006));
#539=CARTESIAN_POINT('',(3.25,-4.54996490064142,-16.0086112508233));
#540=CARTESIAN_POINT('',(3.25,-4.16132971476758,-16.1397775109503));
#541=CARTESIAN_POINT('',(3.25,-3.37414151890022,-16.367940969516));
#542=CARTESIAN_POINT('',(3.25,-2.97558824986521,-16.4649372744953));
#543=CARTESIAN_POINT('',(3.25,-2.17796770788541,-16.6218590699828));
#544=CARTESIAN_POINT('',(3.25,-1.77901685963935,-16.682368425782));
#545=CARTESIAN_POINT('',(3.25,-1.17783289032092,-16.7458571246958));
#546=CARTESIAN_POINT('',(3.25,-0.976962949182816,-16.7624743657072));
#547=CARTESIAN_POINT('',(3.25,-0.574677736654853,-16.7864370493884));
#548=CARTESIAN_POINT('',(3.25,-0.373262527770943,-16.7937835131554));
#549=CARTESIAN_POINT('',(3.25,0.0296307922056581,-16.7991040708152));
#550=CARTESIAN_POINT('',(3.25,0.231108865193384,-16.7970810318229));
#551=CARTESIAN_POINT('',(3.25,0.633740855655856,-16.7837024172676));
#552=CARTESIAN_POINT('',(3.25,0.834894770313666,-16.7723467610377));
#553=CARTESIAN_POINT('',(3.25,1.43727360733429,-16.7244784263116));
#554=CARTESIAN_POINT('',(3.25,1.83748615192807,-16.6741652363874));
#555=CARTESIAN_POINT('',(3.25,2.60244344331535,-16.5434913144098));
#556=CARTESIAN_POINT('',(3.25,2.9676242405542,-16.465624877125));
#557=CARTESIAN_POINT('',(3.25,3.69061293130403,-16.2811099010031));
#558=CARTESIAN_POINT('',(3.25,4.04842149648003,-16.1744639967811));
#559=CARTESIAN_POINT('',(3.25,4.75476881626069,-15.9334225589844));
#560=CARTESIAN_POINT('',(3.25,5.10330243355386,-15.7990119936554));
#561=CARTESIAN_POINT('',(3.25,5.78889033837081,-15.5035347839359));
#562=CARTESIAN_POINT('',(3.25,6.12594408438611,-15.3424668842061));
#563=CARTESIAN_POINT('',(3.25,6.80932679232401,-14.9828170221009));
#564=CARTESIAN_POINT('',(3.25,7.15470066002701,-14.7824174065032));
#565=CARTESIAN_POINT('',(3.25,7.82779768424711,-14.3538815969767));
#566=CARTESIAN_POINT('',(3.25,8.15552013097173,-14.1257442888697));
#567=CARTESIAN_POINT('',(3.25,8.79107255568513,-13.6433774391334));
#568=CARTESIAN_POINT('',(3.25,9.09890611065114,-13.3891526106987));
#569=CARTESIAN_POINT('',(3.25,9.69269581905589,-12.8563257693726));
#570=CARTESIAN_POINT('',(3.25,9.97865187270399,-12.5777236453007));
#571=CARTESIAN_POINT('',(3.25,10.5337680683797,-11.9906483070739));
#572=CARTESIAN_POINT('',(3.25,10.8023152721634,-11.6815951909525));
#573=CARTESIAN_POINT('',(3.25,11.3125257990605,-11.0420356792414));
#574=CARTESIAN_POINT('',(3.25,11.5541885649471,-10.7115288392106));
#575=CARTESIAN_POINT('',(3.25,12.0089741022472,-10.0313455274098));
#576=CARTESIAN_POINT('',(3.25,12.2220918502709,-9.6816656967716));
#577=CARTESIAN_POINT('',(3.25,12.6182423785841,-8.96566280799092));
#578=CARTESIAN_POINT('',(3.25,12.8012752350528,-8.59933979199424));
#579=CARTESIAN_POINT('',(3.25,13.1366167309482,-7.85119993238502));
#580=CARTESIAN_POINT('',(3.25,13.2888047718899,-7.46932902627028));
#581=CARTESIAN_POINT('',(3.25,13.5604975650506,-6.69413124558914));
#582=CARTESIAN_POINT('',(3.25,13.680002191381,-6.30080432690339));
#583=CARTESIAN_POINT('',(3.25,13.885478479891,-5.505506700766));
#584=CARTESIAN_POINT('',(3.25,13.9714517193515,-5.10353640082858));
#585=CARTESIAN_POINT('',(3.25,14.1092657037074,-4.29378701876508));
#586=CARTESIAN_POINT('',(3.25,14.1611064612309,-3.88600793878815));
#587=CARTESIAN_POINT('',(3.25,14.2303212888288,-3.06715435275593));
#588=CARTESIAN_POINT('',(3.25,14.2476633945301,-2.65607714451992));
#589=CARTESIAN_POINT('',(3.25,14.2476620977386,-1.83392251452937));
#590=CARTESIAN_POINT('',(3.25,14.2303186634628,-1.42284509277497));
#591=CARTESIAN_POINT('',(3.25,14.1610682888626,-0.603603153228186));
#592=CARTESIAN_POINT('',(3.25,14.1091606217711,-0.195438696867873));
#593=CARTESIAN_POINT('',(3.25,13.9711485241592,0.615067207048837));
#594=CARTESIAN_POINT('',(3.25,13.885044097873,1.01740865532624));
#595=CARTESIAN_POINT('',(3.25,13.6792331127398,1.81346557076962));
#596=CARTESIAN_POINT('',(3.25,13.5595217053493,2.20717978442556));
#597=CARTESIAN_POINT('',(3.25,13.2873494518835,2.98312116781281));
#598=CARTESIAN_POINT('',(3.25,13.1348885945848,3.36534833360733));
#599=CARTESIAN_POINT('',(3.25,12.7982999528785,4.11558729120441));
#600=CARTESIAN_POINT('',(3.25,12.6141727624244,4.48359934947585));
#601=CARTESIAN_POINT('',(3.25,12.2155528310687,5.20279306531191));
#602=CARTESIAN_POINT('',(3.25,12.0010601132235,5.55397473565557));
#603=CARTESIAN_POINT('',(3.25,11.5433180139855,6.2368658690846));
#604=CARTESIAN_POINT('',(3.25,11.3000801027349,6.56858302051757));
#605=CARTESIAN_POINT('',(3.25,10.7864981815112,7.2103264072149));
#606=CARTESIAN_POINT('',(3.25,10.5161541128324,7.52035259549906));
#607=CARTESIAN_POINT('',(3.25,9.95025306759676,8.11650757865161));
#608=CARTESIAN_POINT('',(3.25,9.65469453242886,8.4026348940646));
#609=CARTESIAN_POINT('',(3.25,9.04046877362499,8.94890264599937));
#610=CARTESIAN_POINT('',(3.25,8.72180175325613,9.20904331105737));
#611=CARTESIAN_POINT('',(3.25,8.06411837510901,9.70105813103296));
#612=CARTESIAN_POINT('',(3.25,7.72513441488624,9.93297559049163));
#613=CARTESIAN_POINT('',(3.25,7.02875492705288,10.3672880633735));
#614=CARTESIAN_POINT('',(3.25,6.67135962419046,10.5696834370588));
#615=CARTESIAN_POINT('',(3.25,5.94066060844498,10.9433896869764));
#616=CARTESIAN_POINT('',(3.25,5.56735649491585,11.1146997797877));
#617=CARTESIAN_POINT('',(3.25,4.80749189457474,11.4247686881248));
#618=CARTESIAN_POINT('',(3.25,4.42093314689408,11.5635317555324));
#619=CARTESIAN_POINT('',(3.25,3.70318039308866,11.786627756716));
#620=CARTESIAN_POINT('',(3.25,3.37360154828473,11.876189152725));
#621=CARTESIAN_POINT('',(3.25,2.70877137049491,12.0309482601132));
#622=CARTESIAN_POINT('',(3.25,2.37352047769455,12.0961478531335));
#623=CARTESIAN_POINT('',(3.25,1.69957377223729,12.2010954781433));
#624=CARTESIAN_POINT('',(3.25,1.36088404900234,12.2408824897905));
#625=CARTESIAN_POINT('',(3.25,0.681453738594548,12.2940966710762));
#626=CARTESIAN_POINT('',(3.25,0.340713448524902,12.3075275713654));
#627=CARTESIAN_POINT('',(3.25,0.,12.3075320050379));
#628=B_SPLINE_CURVE_WITH_KNOTS('',3,(#470,#471,#472,#473,#474,#475,#476,#477,#478,#479,#480,
#481,#482,#483,#484,#485,#486,#487,#488,#489,#490,#491,#492,#493,#494,#495,#496,#497,#498,#499,
#500,#501,#502,#503,#504,#505,#506,#507,#508,#509,#510,#511,#512,#513,#514,#515,#516,#517,#518,
#519,#520,#521,#522,#523,#524,#525,#526,#527,#528,#529,#530,#531,#532,#533,#534,#535,#536,#537,
#538,#539,#540,#541,#542,#543,#544,#545,#546,#547,#548,#549,#550,#551,#552,#553,#554,#555,#556,
#557,#558,#559,#560,#561,#562,#563,#564,#565,#566,#567,#568,#569,#570,#571,#572,#573,#574,#575,
#576,#577,#578,#579,#580,#581,#582,#583,#584,#585,#586,#587,#588,#589,#590,#591,#592,#593,#594,
#595,#596,#597,#598,#599,#600,#601,#602,#603,#604,#605,#606,#607,#608,#609,#610,#611,#612,#613,
#614,#615,#616,#617,#618,#619,#620,#621,#622,#623,#624,#625,#626,#627),.UNSPECIFIED.,.T.,.F.,(4,
2,2,2,2,2,2,2,2,2,2,2,2,2,2,2,2,2,2,2,2,2,2,2,2,2,2,2,2,2,2,2,2,2,2,2,2,2,2,2,2,2,2,2,2,2,2,2,2,
2,2,2,2,2,2,2,2,2,2,2,2,2,2,2,2,2,2,2,2,2,2,2,2,2,2,2,2,2,4),(0.,0.833015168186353,
1.66595398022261,2.49960035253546,3.33339736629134,4.53957397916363,5.74594771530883,
6.95348227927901,8.16043266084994,9.37173482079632,10.583055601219,11.7941011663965,
13.0051534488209,14.2343656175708,15.4635919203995,16.6929400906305,17.9222868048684,
19.15456962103,20.3868552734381,21.6191084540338,22.8513613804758,24.0843315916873,
25.3173025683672,26.5503360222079,27.7833693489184,29.01645476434,30.2495405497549,
31.4824474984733,32.7153531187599,33.9473553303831,35.1793595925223,36.4118555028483,
37.6443481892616,38.8739277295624,40.1035160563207,41.3325065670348,42.5615292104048,
43.7703236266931,44.3748145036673,44.97923879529,45.583478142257,46.1877227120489,
47.3960010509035,48.5150195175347,49.6339355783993,50.7534590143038,51.8730351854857,
53.0695719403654,54.2661567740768,55.4625258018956,56.658900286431,57.8857327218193,
59.1125905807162,60.3396640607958,61.5667344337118,62.7985136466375,64.0302976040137,
65.2620236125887,66.4937491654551,67.7266154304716,68.9594828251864,70.1923761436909,
71.4252693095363,72.6583404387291,73.8914119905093,75.1244604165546,76.3575079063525,
77.5900650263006,78.8226248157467,80.05526085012,81.2878860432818,82.5185954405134,
83.7492898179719,84.9800152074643,86.2105797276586,87.2343070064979,88.2579551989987,
89.2800294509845,90.3019590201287),.UNSPECIFIED.);
#629=CARTESIAN_POINT('',(3.25,-0.45,12.2997491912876));
#630=VERTEX_POINT('',#629);
#631=EDGE_CURVE('E444',#467,#630,#628,.T.);
#632=ORIENTED_EDGE('',*,*,#631,.T.);
#633=CARTESIAN_POINT('',(3.24999989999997,-0.4498,12.2997561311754));
#634=CARTESIAN_POINT('',(3.25002147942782,-0.460776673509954,12.2993714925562));
#635=CARTESIAN_POINT('',(3.24911882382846,-0.471758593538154,12.2992032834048));
#636=CARTESIAN_POINT('',(3.24553635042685,-0.493412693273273,12.2992941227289));
#637=CARTESIAN_POINT('',(3.24285883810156,-0.504085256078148,12.299552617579));
#638=CARTESIAN_POINT('',(3.23579622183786,-0.524834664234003,12.3004904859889));
#639=CARTESIAN_POINT('',(3.23141042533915,-0.53491126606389,12.3011700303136));
#640=CARTESIAN_POINT('',(3.22107038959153,-0.554184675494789,12.3029273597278));
#641=CARTESIAN_POINT('',(3.21511623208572,-0.563381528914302,12.3040051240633));
#642=CARTESIAN_POINT('',(3.20177417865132,-0.580709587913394,12.3065339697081));
#643=CARTESIAN_POINT('',(3.19437690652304,-0.588833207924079,12.3079875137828));
#644=CARTESIAN_POINT('',(3.17839327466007,-0.603735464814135,12.3112205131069));
#645=CARTESIAN_POINT('',(3.16980667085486,-0.610513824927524,12.3130000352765));
#646=CARTESIAN_POINT('',(3.15148706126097,-0.62269653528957,12.3168763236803));
#647=CARTESIAN_POINT('',(3.14173272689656,-0.628066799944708,12.3189792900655));
#648=CARTESIAN_POINT('',(3.12151319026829,-0.637105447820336,12.3234120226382));
#649=CARTESIAN_POINT('',(3.11104805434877,-0.640773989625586,12.3257417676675));
#650=CARTESIAN_POINT('',(3.09210451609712,-0.64570458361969,12.3300193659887));
#651=CARTESIAN_POINT('',(3.08370936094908,-0.647322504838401,12.3319350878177));
#652=CARTESIAN_POINT('',(3.06680849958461,-0.649474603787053,12.3358309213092));
#653=CARTESIAN_POINT('',(3.05830296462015,-0.650010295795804,12.3378109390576));
#654=CARTESIAN_POINT('',(3.0498,-0.649999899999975,12.3398097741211));
#655=B_SPLINE_CURVE_WITH_KNOTS('',3,(#633,#634,#635,#636,#637,#638,#639,#640,#641,#642,#643,
#644,#645,#646,#647,#648,#649,#650,#651,#652,#653,#654),.UNSPECIFIED.,.F.,.F.,(4,2,2,2,2,2,2,2,
2,2,4),(0.,0.0329053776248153,0.0657680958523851,0.0986441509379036,0.13151849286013,
0.1646140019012,0.197716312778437,0.231558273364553,0.265397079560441,0.291616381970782,
0.31779897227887),.UNSPECIFIED.);
#656=CARTESIAN_POINT('',(3.05,-0.65,12.3397627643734));
#657=VERTEX_POINT('',#656);
#658=EDGE_CURVE('E451',#630,#657,#655,.T.);
#659=ORIENTED_EDGE('',*,*,#658,.T.);
#660=CARTESIAN_POINT('',(0.,-0.65,12.7191322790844));
#661=CARTESIAN_POINT('',(-0.108520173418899,-0.65,12.7191277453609));
#662=CARTESIAN_POINT('',(-0.217041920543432,-0.65,12.7172094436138));
#663=CARTESIAN_POINT('',(-0.433997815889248,-0.65,12.7099981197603));
#664=CARTESIAN_POINT('',(-0.542431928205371,-0.65,12.7047040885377));
#665=CARTESIAN_POINT('',(-0.759555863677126,-0.65,12.6912706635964));
#666=CARTESIAN_POINT('',(-0.868244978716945,-0.65,12.6831199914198));
#667=CARTESIAN_POINT('',(-1.08539837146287,-0.65,12.6642185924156));
#668=CARTESIAN_POINT('',(-1.19386263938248,-0.65,12.6534677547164));
#669=CARTESIAN_POINT('',(-1.51887735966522,-0.65,12.6174925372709));
#670=CARTESIAN_POINT('',(-1.73502604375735,-0.65,12.5885469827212));
#671=CARTESIAN_POINT('',(-2.16611297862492,-0.65,12.5210525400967));
#672=CARTESIAN_POINT('',(-2.38104917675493,-0.65,12.4824906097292));
#673=CARTESIAN_POINT('',(-2.80901885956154,-0.65,12.3959374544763));
#674=CARTESIAN_POINT('',(-3.02205219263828,-0.65,12.3479454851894));
#675=CARTESIAN_POINT('',(-3.64169701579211,-0.65,12.1939819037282));
#676=CARTESIAN_POINT('',(-4.04525595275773,-0.65,12.0754170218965));
#677=CARTESIAN_POINT('',(-4.84106887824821,-0.65,11.804706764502));
#678=CARTESIAN_POINT('',(-5.23331827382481,-0.65,11.6525479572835));
#679=CARTESIAN_POINT('',(-6.00390173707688,-0.65,11.3156534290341));
#680=CARTESIAN_POINT('',(-6.382226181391,-0.65,11.1308956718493));
#681=CARTESIAN_POINT('',(-7.12194189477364,-0.65,10.7302214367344));
#682=CARTESIAN_POINT('',(-7.48333496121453,-0.65,10.5143082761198));
#683=CARTESIAN_POINT('',(-8.18679974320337,-0.65,10.0527629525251));
#684=CARTESIAN_POINT('',(-8.52886465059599,-0.65,9.80712041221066));
#685=CARTESIAN_POINT('',(-9.19111928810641,-0.65,9.28791513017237));
#686=CARTESIAN_POINT('',(-9.51130841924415,-0.65,9.01435162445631));
#687=CARTESIAN_POINT('',(-10.1275007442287,-0.65,8.44128082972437));
#688=CARTESIAN_POINT('',(-10.4235063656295,-0.65,8.14177615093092));
#689=CARTESIAN_POINT('',(-10.9892674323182,-0.65,7.51892636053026));
#690=CARTESIAN_POINT('',(-11.2590230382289,-0.65,7.19558139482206));
#691=CARTESIAN_POINT('',(-11.7706885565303,-0.65,6.52693164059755));
#692=CARTESIAN_POINT('',(-12.012563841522,-0.65,6.18160035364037));
#693=CARTESIAN_POINT('',(-12.4663665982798,-0.65,5.47179015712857));
#694=CARTESIAN_POINT('',(-12.6782939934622,-0.65,5.10731119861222));
#695=CARTESIAN_POINT('',(-13.0706918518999,-0.65,4.36180202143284));
#696=CARTESIAN_POINT('',(-13.2511627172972,-0.65,3.98077201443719));
#697=CARTESIAN_POINT('',(-13.5793682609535,-0.65,3.20486500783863));
#698=CARTESIAN_POINT('',(-13.7271029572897,-0.65,2.80998801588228));
#699=CARTESIAN_POINT('',(-13.988800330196,-0.65,2.00915107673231));
#700=CARTESIAN_POINT('',(-14.1027594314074,-0.65,1.60318996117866));
#701=CARTESIAN_POINT('',(-14.2960746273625,-0.65,0.783110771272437));
#702=CARTESIAN_POINT('',(-14.3754307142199,-0.65,0.368992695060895));
#703=CARTESIAN_POINT('',(-14.498977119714,-0.65,-0.464465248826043));
#704=CARTESIAN_POINT('',(-14.5431666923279,-0.65,-0.883805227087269));
#705=CARTESIAN_POINT('',(-14.596063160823,-0.65,-1.72471716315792));
#706=CARTESIAN_POINT('',(-14.6047700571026,-0.65,-2.1462891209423));
#707=CARTESIAN_POINT('',(-14.5866390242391,-0.65,-2.98868011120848));
#708=CARTESIAN_POINT('',(-14.5598000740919,-0.65,-3.40949912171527));
#709=CARTESIAN_POINT('',(-14.4707663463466,-0.65,-4.24738022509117));
#710=CARTESIAN_POINT('',(-14.4085715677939,-0.65,-4.66444231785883));
#711=CARTESIAN_POINT('',(-14.2492707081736,-0.65,-5.49183187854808));
#712=CARTESIAN_POINT('',(-14.1521656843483,-0.65,-5.90215955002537));
#713=CARTESIAN_POINT('',(-13.92373427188,-0.65,-6.7131760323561));
#714=CARTESIAN_POINT('',(-13.7924078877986,-0.65,-7.11386484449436));
#715=CARTESIAN_POINT('',(-13.4964692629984,-0.65,-7.90274953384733));
#716=CARTESIAN_POINT('',(-13.3318574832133,-0.65,-8.29094558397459));
#717=CARTESIAN_POINT('',(-12.9705168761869,-0.65,-9.05209088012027));
#718=CARTESIAN_POINT('',(-12.7737880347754,-0.65,-9.42504011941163));
#719=CARTESIAN_POINT('',(-12.3495993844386,-0.65,-10.1530610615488));
#720=CARTESIAN_POINT('',(-12.1221378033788,-0.65,-10.5081317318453));
#721=CARTESIAN_POINT('',(-11.6381096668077,-0.65,-11.1978469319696));
#722=CARTESIAN_POINT('',(-11.3815431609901,-0.65,-11.5324914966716));
#723=CARTESIAN_POINT('',(-10.8411381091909,-0.65,-12.1789638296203));
#724=CARTESIAN_POINT('',(-10.5573005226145,-0.65,-12.4907923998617));
#725=CARTESIAN_POINT('',(-9.96436091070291,-0.65,-13.0894299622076));
#726=CARTESIAN_POINT('',(-9.65525870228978,-0.65,-13.3762387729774));
#727=CARTESIAN_POINT('',(-9.01399860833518,-0.65,-13.9227850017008));
#728=CARTESIAN_POINT('',(-8.681841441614,-0.65,-14.1825232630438));
#729=CARTESIAN_POINT('',(-7.99683299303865,-0.65,-14.6730822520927));
#730=CARTESIAN_POINT('',(-7.64398231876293,-0.65,-14.9039038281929));
#731=CARTESIAN_POINT('',(-6.92002553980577,-0.65,-15.335028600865));
#732=CARTESIAN_POINT('',(-6.5489163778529,-0.65,-15.5353266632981));
#733=CARTESIAN_POINT('',(-5.79113277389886,-0.65,-15.903924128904));
#734=CARTESIAN_POINT('',(-5.40445847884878,-0.65,-16.0722238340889));
#735=CARTESIAN_POINT('',(-4.61839618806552,-0.65,-16.3755712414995));
#736=CARTESIAN_POINT('',(-4.21901109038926,-0.65,-16.5106264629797));
#737=CARTESIAN_POINT('',(-3.41037855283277,-0.65,-16.7464936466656));
#738=CARTESIAN_POINT('',(-3.00113546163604,-0.65,-16.8473204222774));
#739=CARTESIAN_POINT('',(-2.37474825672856,-0.65,-16.9737106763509));
#740=CARTESIAN_POINT('',(-2.16011736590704,-0.65,-17.0121235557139));
#741=CARTESIAN_POINT('',(-1.72933145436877,-0.65,-17.0793970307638));
#742=CARTESIAN_POINT('',(-1.51317639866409,-0.65,-17.1082574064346));
#743=CARTESIAN_POINT('',(-1.1883245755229,-0.65,-17.1440821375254));
#744=CARTESIAN_POINT('',(-1.08002619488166,-0.65,-17.1547737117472));
#745=CARTESIAN_POINT('',(-0.86319814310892,-0.65,-17.1735629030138));
#746=CARTESIAN_POINT('',(-0.754668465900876,-0.65,-17.1816604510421));
#747=CARTESIAN_POINT('',(-0.537464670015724,-0.65,-17.1950151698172));
#748=CARTESIAN_POINT('',(-0.428790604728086,-0.65,-17.2002731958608));
#749=CARTESIAN_POINT('',(-0.211334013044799,-0.65,-17.20738850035));
#750=CARTESIAN_POINT('',(-0.10255149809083,-0.65,-17.2092461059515));
#751=CARTESIAN_POINT('',(0.0980379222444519,-0.65,-17.2091183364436));
#752=CARTESIAN_POINT('',(0.189845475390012,-0.65,-17.2076873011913));
#753=CARTESIAN_POINT('',(0.373392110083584,-0.65,-17.2023544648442));
#754=CARTESIAN_POINT('',(0.465131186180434,-0.65,-17.1984524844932));
#755=CARTESIAN_POINT('',(0.648525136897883,-0.65,-17.1885366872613));
#756=CARTESIAN_POINT('',(0.740179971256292,-0.65,-17.1825221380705));
#757=CARTESIAN_POINT('',(0.923340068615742,-0.65,-17.1685825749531));
#758=CARTESIAN_POINT('',(1.01484533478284,-0.65,-17.1606576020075));
#759=CARTESIAN_POINT('',(1.28932831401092,-0.65,-17.1341570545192));
#760=CARTESIAN_POINT('',(1.47205047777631,-0.65,-17.1128685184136));
#761=CARTESIAN_POINT('',(1.83651738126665,-0.65,-17.0634122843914));
#762=CARTESIAN_POINT('',(2.01826229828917,-0.65,-17.0352458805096));
#763=CARTESIAN_POINT('',(2.38129600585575,-0.65,-16.9720306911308));
#764=CARTESIAN_POINT('',(2.56258014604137,-0.65,-16.936955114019));
#765=CARTESIAN_POINT('',(2.92371751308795,-0.65,-16.8600846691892));
#766=CARTESIAN_POINT('',(3.10357066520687,-0.65,-16.8182894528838));
#767=CARTESIAN_POINT('',(3.64033450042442,-0.65,-16.6830040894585));
#768=CARTESIAN_POINT('',(3.9947892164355,-0.65,-16.57955495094));
#769=CARTESIAN_POINT('',(4.71178689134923,-0.65,-16.3411791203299));
#770=CARTESIAN_POINT('',(5.07390702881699,-0.65,-16.2049845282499));
#771=CARTESIAN_POINT('',(5.78663052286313,-0.65,-15.9049349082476));
#772=CARTESIAN_POINT('',(6.13723052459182,-0.65,-15.7410719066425));
#773=CARTESIAN_POINT('',(6.82400082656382,-0.65,-15.3870663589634));
#774=CARTESIAN_POINT('',(7.16019896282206,-0.65,-15.1969778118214));
#775=CARTESIAN_POINT('',(7.81689468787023,-0.65,-14.7914249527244));
#776=CARTESIAN_POINT('',(8.13739298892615,-0.65,-14.5759617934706));
#777=CARTESIAN_POINT('',(8.7889588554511,-0.65,-14.1003791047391));
#778=CARTESIAN_POINT('',(9.118369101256,-0.65,-13.8379842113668));
#779=CARTESIAN_POINT('',(9.75396306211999,-0.65,-13.2863857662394));
#780=CARTESIAN_POINT('',(10.0601446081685,-0.65,-12.9971797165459));
#781=CARTESIAN_POINT('',(10.6473742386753,-0.65,-12.3937305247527));
#782=CARTESIAN_POINT('',(10.9283974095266,-0.65,-12.0794631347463));
#783=CARTESIAN_POINT('',(11.4629667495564,-0.65,-11.4283824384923));
#784=CARTESIAN_POINT('',(11.716513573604,-0.65,-11.0915696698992));
#785=CARTESIAN_POINT('',(12.1943966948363,-0.65,-10.3976989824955));
#786=CARTESIAN_POINT('',(12.4187257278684,-0.65,-10.0406360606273));
#787=CARTESIAN_POINT('',(12.836505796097,-0.65,-9.30887820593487));
#788=CARTESIAN_POINT('',(13.0299566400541,-0.65,-8.93418316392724));
#789=CARTESIAN_POINT('',(13.3845512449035,-0.65,-8.16994018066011));
#790=CARTESIAN_POINT('',(13.5457045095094,-0.65,-7.78039664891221));
#791=CARTESIAN_POINT('',(13.8346300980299,-0.65,-6.98912166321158));
#792=CARTESIAN_POINT('',(13.9624024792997,-0.65,-6.58739023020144));
#793=CARTESIAN_POINT('',(14.1836800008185,-0.65,-5.77451590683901));
#794=CARTESIAN_POINT('',(14.2771785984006,-0.65,-5.36337123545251));
#795=CARTESIAN_POINT('',(14.4292098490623,-0.65,-4.53466691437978));
#796=CARTESIAN_POINT('',(14.487742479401,-0.65,-4.11710726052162));
#797=CARTESIAN_POINT('',(14.5694291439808,-0.65,-3.27850601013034));
#798=CARTESIAN_POINT('',(14.5925801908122,-0.65,-2.85746412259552));
#799=CARTESIAN_POINT('',(14.6033296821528,-0.65,-2.01492679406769));
#800=CARTESIAN_POINT('',(14.5909281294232,-0.65,-1.59343135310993));
#801=CARTESIAN_POINT('',(14.5306606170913,-0.65,-0.752983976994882));
#802=CARTESIAN_POINT('',(14.4827946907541,-0.65,-0.334032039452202));
#803=CARTESIAN_POINT('',(14.351938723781,-0.65,0.49835010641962));
#804=CARTESIAN_POINT('',(14.2689486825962,-0.65,0.911780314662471));
#805=CARTESIAN_POINT('',(14.0684388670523,-0.65,1.73016147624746));
#806=CARTESIAN_POINT('',(13.9509206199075,-0.65,2.13511280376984));
#807=CARTESIAN_POINT('',(13.6821883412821,-0.65,2.93367609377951));
#808=CARTESIAN_POINT('',(13.5309743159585,-0.65,3.32728805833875));
#809=CARTESIAN_POINT('',(13.1959267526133,-0.65,4.10037092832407));
#810=CARTESIAN_POINT('',(13.0120935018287,-0.65,4.47984195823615));
#811=CARTESIAN_POINT('',(12.6131130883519,-0.65,5.22194896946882));
#812=CARTESIAN_POINT('',(12.3979659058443,-0.65,5.58458494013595));
#813=CARTESIAN_POINT('',(11.9378740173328,-0.65,6.29046298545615));
#814=CARTESIAN_POINT('',(11.6929276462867,-0.65,6.63370397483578));
#815=CARTESIAN_POINT('',(11.1749886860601,-0.65,7.29832838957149));
#816=CARTESIAN_POINT('',(10.9019961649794,-0.65,7.61971186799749));
#817=CARTESIAN_POINT('',(10.3299256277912,-0.65,8.23831388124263));
#818=CARTESIAN_POINT('',(10.0308495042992,-0.65,8.53553416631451));
#819=CARTESIAN_POINT('',(9.40871715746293,-0.65,9.10372430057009));
#820=CARTESIAN_POINT('',(9.08566069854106,-0.65,9.37469389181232));
#821=CARTESIAN_POINT('',(8.41785441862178,-0.65,9.88845978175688));
#822=CARTESIAN_POINT('',(8.07310383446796,-0.65,10.1312550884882));
#823=CARTESIAN_POINT('',(7.36438263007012,-0.65,10.5869228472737));
#824=CARTESIAN_POINT('',(7.00041275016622,-0.65,10.799796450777));
#825=CARTESIAN_POINT('',(6.25574024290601,-0.65,11.1941576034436));
#826=CARTESIAN_POINT('',(5.87503367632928,-0.65,11.3756377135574));
#827=CARTESIAN_POINT('',(5.09960838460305,-0.65,11.7058730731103));
#828=CARTESIAN_POINT('',(4.70488757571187,-0.65,11.8546234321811));
#829=CARTESIAN_POINT('',(3.90465475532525,-0.65,12.118151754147));
#830=CARTESIAN_POINT('',(3.49915214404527,-0.65,12.2329583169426));
#831=CARTESIAN_POINT('',(2.6798528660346,-0.65,12.4278850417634));
#832=CARTESIAN_POINT('',(2.26605705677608,-0.65,12.5080087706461));
#833=CARTESIAN_POINT('',(1.69646981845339,-0.65,12.5931341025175));
#834=CARTESIAN_POINT('',(1.54287539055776,-0.65,12.6136119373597));
#835=CARTESIAN_POINT('',(1.23513895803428,-0.65,12.6495835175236));
#836=CARTESIAN_POINT('',(1.08099712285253,-0.65,12.6650786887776));
#837=CARTESIAN_POINT('',(0.772511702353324,-0.65,12.6907884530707));
#838=CARTESIAN_POINT('',(0.618168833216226,-0.65,12.7010114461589));
#839=CARTESIAN_POINT('',(0.386454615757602,-0.65,12.7116612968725));
#840=CARTESIAN_POINT('',(0.309189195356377,-0.65,12.7144304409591));
#841=CARTESIAN_POINT('',(0.154616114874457,-0.65,12.7181675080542));
#842=CARTESIAN_POINT('',(0.0773084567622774,-0.65,12.7191355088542));
#843=CARTESIAN_POINT('',(0.,-0.65,12.7191322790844));
#844=B_SPLINE_CURVE_WITH_KNOTS('',3,(#660,#661,#662,#663,#664,#665,#666,#667,#668,#669,#670,
#671,#672,#673,#674,#675,#676,#677,#678,#679,#680,#681,#682,#683,#684,#685,#686,#687,#688,#689,
#690,#691,#692,#693,#694,#695,#696,#697,#698,#699,#700,#701,#702,#703,#704,#705,#706,#707,#708,
#709,#710,#711,#712,#713,#714,#715,#716,#717,#718,#719,#720,#721,#722,#723,#724,#725,#726,#727,
#728,#729,#730,#731,#732,#733,#734,#735,#736,#737,#738,#739,#740,#741,#742,#743,#744,#745,#746,
#747,#748,#749,#750,#751,#752,#753,#754,#755,#756,#757,#758,#759,#760,#761,#762,#763,#764,#765,
#766,#767,#768,#769,#770,#771,#772,#773,#774,#775,#776,#777,#778,#779,#780,#781,#782,#783,#784,
#785,#786,#787,#788,#789,#790,#791,#792,#793,#794,#795,#796,#797,#798,#799,#800,#801,#802,#803,
#804,#805,#806,#807,#808,#809,#810,#811,#812,#813,#814,#815,#816,#817,#818,#819,#820,#821,#822,
#823,#824,#825,#826,#827,#828,#829,#830,#831,#832,#833,#834,#835,#836,#837,#838,#839,#840,#841,
#842,#843),.UNSPECIFIED.,.T.,.F.,(4,2,2,2,2,2,2,2,2,2,2,2,2,2,2,2,2,2,2,2,2,2,2,2,2,2,2,2,2,2,2,
2,2,2,2,2,2,2,2,2,2,2,2,2,2,2,2,2,2,2,2,2,2,2,2,2,2,2,2,2,2,2,2,2,2,2,2,2,2,2,2,2,2,2,2,2,2,2,2,
2,2,2,2,2,2,2,2,2,2,2,2,4),(0.,0.325550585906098,0.651198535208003,0.978146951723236,
1.30510931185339,1.95910516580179,2.61399287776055,3.26893230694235,4.52915364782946,
5.78987977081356,7.05146140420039,8.31290880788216,9.57479780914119,10.8367213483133,
12.0985180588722,13.3603070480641,14.6236466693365,15.8869895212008,17.1503162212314,
18.4136422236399,19.6771019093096,20.9405618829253,22.2040486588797,23.4675354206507,
24.7310584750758,25.9945815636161,27.2580663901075,28.5215510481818,29.7850182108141,
31.048485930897,32.3120265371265,33.5755649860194,34.8390589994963,36.1025621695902,
37.366025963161,38.6294526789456,39.8930916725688,41.1567187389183,42.4200597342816,
43.6828532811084,44.3368060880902,44.9907739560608,45.3172246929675,45.64368411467,
45.9700451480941,46.296374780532,46.5717928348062,46.8472308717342,47.1227644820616,
47.3982921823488,47.9500163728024,48.5016368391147,49.0554399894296,49.6092718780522,
50.7159038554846,51.8754142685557,53.0352594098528,54.1927510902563,55.3501902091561,
56.6121057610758,57.8741390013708,59.1374084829,60.4006478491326,61.6642006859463,
62.9277613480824,64.1909496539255,65.4541357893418,66.7175629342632,67.9809909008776,
69.2445255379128,70.5080600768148,71.7715934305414,73.0351268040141,74.2986042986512,
75.5620815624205,76.8255477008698,78.0890146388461,79.3525522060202,80.6160867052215,
81.8795295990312,83.1429849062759,84.4064846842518,85.6699358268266,86.9336859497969,
88.1976247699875,89.4604955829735,90.7232364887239,91.1880404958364,91.6527113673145,
92.1166395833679,92.3485678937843,92.5804861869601),.UNSPECIFIED.);
#845=EDGE_CURVE('E458',#657,#59,#844,.T.);
#846=ORIENTED_EDGE('',*,*,#845,.T.);
#847=EDGE_LOOP('',(#63,#226,#253,#442,#469,#632,#659,#846));
#848=FACE_BOUND('',#847,.T.);
#849=ADVANCED_FACE('F14',(#34,#848),#23,.F.);
#850=CARTESIAN_POINT('',(0.,0.,0.));
#851=DIRECTION('',(0.,0.,1.));
#852=DIRECTION('',(1.,0.,0.));
#853=AXIS2_PLACEMENT_3D('',#850,#851,#852);
#854=PLANE('',#853);
#855=CARTESIAN_POINT('',(0.,0.,0.));
#856=DIRECTION('',(0.,0.,1.));
#857=DIRECTION('',(1.,0.,0.));
#858=AXIS2_PLACEMENT_3D('',#855,#856,#857);
#859=CIRCLE('',#858,2.);
#860=CARTESIAN_POINT('',(2.,0.,0.));
#861=VERTEX_POINT('',#860);
#862=EDGE_CURVE('E383',#861,#861,#859,.T.);
#863=ORIENTED_EDGE('',*,*,#862,.F.);
#864=EDGE_LOOP('',(#863));
#865=FACE_BOUND('',#864,.T.);
#866=CARTESIAN_POINT('',(0.,0.,0.));
#867=DIRECTION('',(0.,0.,-1.));
#868=DIRECTION('',(-1.,0.,0.));
#869=AXIS2_PLACEMENT_3D('',#866,#867,#868);
#870=CIRCLE('',#869,1.5);
#871=CARTESIAN_POINT('',(-1.5,0.,0.));
#872=VERTEX_POINT('',#871);
#873=EDGE_CURVE('E219',#872,#872,#870,.T.);
#874=ORIENTED_EDGE('',*,*,#873,.F.);
#875=EDGE_LOOP('',(#874));
#876=FACE_BOUND('',#875,.T.);
#877=ADVANCED_FACE('F16',(#865,#876),#854,.F.);
#878=CARTESIAN_POINT('',(0.,0.,12.75));
#879=DIRECTION('',(0.,0.,1.));
#880=DIRECTION('',(1.,0.,0.));
#881=AXIS2_PLACEMENT_3D('',#878,#879,#880);
#882=CYLINDRICAL_SURFACE('',#881,2.);
#883=CARTESIAN_POINT('',(0.,0.,0.3));
#884=DIRECTION('',(0.,0.,1.));
#885=DIRECTION('',(1.,0.,0.));
#886=AXIS2_PLACEMENT_3D('',#883,#884,#885);
#887=CIRCLE('',#886,2.);
#888=CARTESIAN_POINT('',(2.,0.,0.3));
#889=VERTEX_POINT('',#888);
#890=EDGE_CURVE('E380',#889,#889,#887,.T.);
#891=ORIENTED_EDGE('',*,*,#890,.F.);
#892=EDGE_LOOP('',(#891));
#893=FACE_BOUND('',#892,.T.);
#894=ORIENTED_EDGE('',*,*,#862,.T.);
#895=EDGE_LOOP('',(#894));
#896=FACE_BOUND('',#895,.T.);
#897=ADVANCED_FACE('F957',(#893,#896),#882,.T.);
#898=CARTESIAN_POINT('',(0.,2.,0.3));
#899=DIRECTION('',(0.,0.,1.));
#900=DIRECTION('',(1.,0.,0.));
#901=AXIS2_PLACEMENT_3D('',#898,#899,#900);
#902=PLANE('',#901);
#903=CARTESIAN_POINT('',(0.,0.,0.3));
#904=DIRECTION('',(0.,0.,1.));
#905=DIRECTION('',(1.,0.,0.));
#906=AXIS2_PLACEMENT_3D('',#903,#904,#905);
#907=CIRCLE('',#906,4.);
#908=CARTESIAN_POINT('',(4.,0.,0.3));
#909=VERTEX_POINT('',#908);
#910=EDGE_CURVE('E377',#909,#909,#907,.T.);
#911=ORIENTED_EDGE('',*,*,#910,.F.);
#912=EDGE_LOOP('',(#911));
#913=FACE_BOUND('',#912,.T.);
#914=ORIENTED_EDGE('',*,*,#890,.T.);
#915=EDGE_LOOP('',(#914));
#916=FACE_BOUND('',#915,.T.);
#917=ADVANCED_FACE('F948',(#913,#916),#902,.F.);
#918=CARTESIAN_POINT('',(0.,0.,0.3));
#919=DIRECTION('',(0.,0.,1.));
#920=DIRECTION('',(1.,0.,0.));
#921=AXIS2_PLACEMENT_3D('',#918,#919,#920);
#922=CONICAL_SURFACE('',#921,4.,0.785398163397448);
#923=CARTESIAN_POINT('',(0.,0.,1.05));
#924=DIRECTION('',(0.,0.,1.));
#925=DIRECTION('',(1.,0.,0.));
#926=AXIS2_PLACEMENT_3D('',#923,#924,#925);
#927=CIRCLE('',#926,4.75);
#928=CARTESIAN_POINT('',(4.75,0.,1.05));
#929=VERTEX_POINT('',#928);
#930=EDGE_CURVE('E374',#929,#929,#927,.T.);
#931=ORIENTED_EDGE('',*,*,#930,.F.);
#932=EDGE_LOOP('',(#931));
#933=FACE_BOUND('',#932,.T.);
#934=ORIENTED_EDGE('',*,*,#910,.T.);
#935=EDGE_LOOP('',(#934));
#936=FACE_BOUND('',#935,.T.);
#937=ADVANCED_FACE('F939',(#933,#936),#922,.T.);
#938=CARTESIAN_POINT('',(0.,0.,12.75));
#939=DIRECTION('',(0.,0.,1.));
#940=DIRECTION('',(1.,0.,0.));
#941=AXIS2_PLACEMENT_3D('',#938,#939,#940);
#942=CYLINDRICAL_SURFACE('',#941,4.75);
#943=CARTESIAN_POINT('',(0.,0.,4.));
#944=DIRECTION('',(0.,0.,1.));
#945=DIRECTION('',(1.,0.,0.));
#946=AXIS2_PLACEMENT_3D('',#943,#944,#945);
#947=CIRCLE('',#946,4.75);
#948=CARTESIAN_POINT('',(4.75,0.,4.));
#949=VERTEX_POINT('',#948);
#950=EDGE_CURVE('E371',#949,#949,#947,.T.);
#951=ORIENTED_EDGE('',*,*,#950,.F.);
#952=EDGE_LOOP('',(#951));
#953=FACE_BOUND('',#952,.T.);
#954=ORIENTED_EDGE('',*,*,#930,.T.);
#955=EDGE_LOOP('',(#954));
#956=FACE_BOUND('',#955,.T.);
#957=ADVANCED_FACE('F930',(#953,#956),#942,.T.);
#958=CARTESIAN_POINT('',(0.,4.75,4.));
#959=DIRECTION('',(0.,0.,1.));
#960=DIRECTION('',(1.,0.,0.));
#961=AXIS2_PLACEMENT_3D('',#958,#959,#960);
#962=PLANE('',#961);
#963=CARTESIAN_POINT('',(0.,0.,4.));
#964=DIRECTION('',(0.,0.,1.));
#965=DIRECTION('',(1.,0.,0.));
#966=AXIS2_PLACEMENT_3D('',#963,#964,#965);
#967=CIRCLE('',#966,5.);
#968=CARTESIAN_POINT('',(5.,0.,4.));
#969=VERTEX_POINT('',#968);
#970=EDGE_CURVE('E368',#969,#969,#967,.T.);
#971=ORIENTED_EDGE('',*,*,#970,.F.);
#972=EDGE_LOOP('',(#971));
#973=FACE_BOUND('',#972,.T.);
#974=ORIENTED_EDGE('',*,*,#950,.T.);
#975=EDGE_LOOP('',(#974));
#976=FACE_BOUND('',#975,.T.);
#977=ADVANCED_FACE('F921',(#973,#976),#962,.F.);
#978=CARTESIAN_POINT('',(0.,0.,12.75));
#979=DIRECTION('',(0.,0.,1.));
#980=DIRECTION('',(1.,0.,0.));
#981=AXIS2_PLACEMENT_3D('',#978,#979,#980);
#982=CYLINDRICAL_SURFACE('',#981,5.);
#983=CARTESIAN_POINT('',(0.,0.,7.));
#984=DIRECTION('',(0.,0.,1.));
#985=DIRECTION('',(1.,0.,0.));
#986=AXIS2_PLACEMENT_3D('',#983,#984,#985);
#987=CIRCLE('',#986,5.);
#988=CARTESIAN_POINT('',(5.,0.,7.));
#989=VERTEX_POINT('',#988);
#990=EDGE_CURVE('E365',#989,#989,#987,.T.);
#991=ORIENTED_EDGE('',*,*,#990,.F.);
#992=EDGE_LOOP('',(#991));
#993=FACE_BOUND('',#992,.T.);
#994=ORIENTED_EDGE('',*,*,#970,.T.);
#995=EDGE_LOOP('',(#994));
#996=FACE_BOUND('',#995,.T.);
#997=ADVANCED_FACE('F912',(#993,#996),#982,.T.);
#998=CARTESIAN_POINT('',(0.,5.,7.));
#999=DIRECTION('',(0.,0.,1.));
#1000=DIRECTION('',(1.,0.,0.));
#1001=AXIS2_PLACEMENT_3D('',#998,#999,#1000);
#1002=PLANE('',#1001);
#1003=CARTESIAN_POINT('',(0.,0.,7.));
#1004=DIRECTION('',(0.,0.,1.));
#1005=DIRECTION('',(1.,0.,0.));
#1006=AXIS2_PLACEMENT_3D('',#1003,#1004,#1005);
#1007=CIRCLE('',#1006,5.21739130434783);
#1008=CARTESIAN_POINT('',(5.21739130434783,0.,7.));
#1009=VERTEX_POINT('',#1008);
#1010=EDGE_CURVE('E362',#1009,#1009,#1007,.T.);
#1011=ORIENTED_EDGE('',*,*,#1010,.F.);
#1012=EDGE_LOOP('',(#1011));
#1013=FACE_BOUND('',#1012,.T.);
#1014=ORIENTED_EDGE('',*,*,#990,.T.);
#1015=EDGE_LOOP('',(#1014));
#1016=FACE_BOUND('',#1015,.T.);
#1017=ADVANCED_FACE('F904',(#1013,#1016),#1002,.F.);
#1018=CARTESIAN_POINT('',(0.,0.,12.75));
#1019=DIRECTION('',(0.,0.,1.));
#1020=DIRECTION('',(1.,0.,0.));
#1021=AXIS2_PLACEMENT_3D('',#1018,#1019,#1020);
#1022=CYLINDRICAL_SURFACE('',#1021,5.21739130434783);
#1023=CARTESIAN_POINT('',(0.,0.,4.));
#1024=DIRECTION('',(0.,0.,1.));
#1025=DIRECTION('',(1.,0.,0.));
#1026=AXIS2_PLACEMENT_3D('',#1023,#1024,#1025);
#1027=CIRCLE('',#1026,5.21739130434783);
#1028=CARTESIAN_POINT('',(5.21739130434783,0.,4.));
#1029=VERTEX_POINT('',#1028);
#1030=EDGE_CURVE('E256',#1029,#1029,#1027,.T.);
#1031=ORIENTED_EDGE('',*,*,#1030,.F.);
#1032=EDGE_LOOP('',(#1031));
#1033=FACE_BOUND('',#1032,.T.);
#1034=ORIENTED_EDGE('',*,*,#1010,.T.);
#1035=EDGE_LOOP('',(#1034));
#1036=FACE_BOUND('',#1035,.T.);
#1037=ADVANCED_FACE('F487',(#1033,#1036),#1022,.F.);
#1038=CARTESIAN_POINT('',(0.,5.21739130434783,5.2));
#1039=DIRECTION('',(0.,0.,1.));
#1040=DIRECTION('',(1.,0.,0.));
#1041=AXIS2_PLACEMENT_3D('',#1038,#1039,#1040);
#1042=PLANE('',#1041);
#1043=CARTESIAN_POINT('',(0.,0.,5.2));
#1044=DIRECTION('',(0.,0.,1.));
#1045=DIRECTION('',(1.,0.,0.));
#1046=AXIS2_PLACEMENT_3D('',#1043,#1044,#1045);
#1047=CIRCLE('',#1046,6.01);
#1048=CARTESIAN_POINT('',(6.01,0.,5.2));
#1049=VERTEX_POINT('',#1048);
#1050=EDGE_CURVE('E253',#1049,#1049,#1047,.T.);
#1051=ORIENTED_EDGE('',*,*,#1050,.T.);
#1052=EDGE_LOOP('',(#1051));
#1053=FACE_BOUND('',#1052,.T.);
#1054=CARTESIAN_POINT('',(-6.53912348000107,1.15302389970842,5.2));
#1055=DIRECTION('',(0.,0.,1.));
#1056=DIRECTION('',(1.,0.,0.));
#1057=AXIS2_PLACEMENT_3D('',#1054,#1055,#1056);
#1058=CIRCLE('',#1057,1.2);
#1059=CARTESIAN_POINT('',(-5.99945018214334,0.0812250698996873,5.2));
#1060=VERTEX_POINT('',#1059);
#1061=CARTESIAN_POINT('',(-5.6654196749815,1.97560621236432,5.2));
#1062=VERTEX_POINT('',#1061);
#1063=EDGE_CURVE('E351',#1060,#1062,#1058,.T.);
#1064=ORIENTED_EDGE('',*,*,#1063,.T.);
#1065=CARTESIAN_POINT('',(0.,0.,5.2));
#1066=DIRECTION('',(0.,0.,1.));
#1067=DIRECTION('',(1.,0.,0.));
#1068=AXIS2_PLACEMENT_3D('',#1065,#1066,#1067);
#1069=CIRCLE('',#1068,6.);
#1070=CARTESIAN_POINT('',(-4.54363500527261,3.918594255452,5.2));
#1071=VERTEX_POINT('',#1070);
#1072=EDGE_CURVE('E349',#1071,#1062,#1069,.T.);
#1073=ORIENTED_EDGE('',*,*,#1072,.F.);
#1074=CARTESIAN_POINT('',(-4.26810972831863,5.08653510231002,5.2));
#1075=DIRECTION('',(0.,0.,1.));
#1076=DIRECTION('',(1.,0.,0.));
#1077=AXIS2_PLACEMENT_3D('',#1074,#1075,#1076);
#1078=CIRCLE('',#1077,1.2);
#1079=CARTESIAN_POINT('',(-3.07006806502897,5.15506373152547,5.2));
#1080=VERTEX_POINT('',#1079);
#1081=EDGE_CURVE('E346',#1071,#1080,#1078,.T.);
#1082=ORIENTED_EDGE('',*,*,#1081,.T.);
#1083=CARTESIAN_POINT('',(0.,0.,5.2));
#1084=DIRECTION('',(0.,0.,1.));
#1085=DIRECTION('',(1.,0.,0.));
#1086=AXIS2_PLACEMENT_3D('',#1083,#1084,#1085);
#1087=CIRCLE('',#1086,6.);
#1088=CARTESIAN_POINT('',(-0.961802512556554,5.92240963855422,5.2));
#1089=VERTEX_POINT('',#1088);
#1090=EDGE_CURVE('E344',#1089,#1080,#1087,.T.);
#1091=ORIENTED_EDGE('',*,*,#1090,.F.);
#1092=CARTESIAN_POINT('',(0.,6.64,5.2));
#1093=DIRECTION('',(0.,0.,1.));
#1094=DIRECTION('',(1.,0.,0.));
#1095=AXIS2_PLACEMENT_3D('',#1092,#1093,#1094);
#1096=CIRCLE('',#1095,1.2);
#1097=CARTESIAN_POINT('',(0.961802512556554,5.92240963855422,5.2));
#1098=VERTEX_POINT('',#1097);
#1099=EDGE_CURVE('E342',#1089,#1098,#1096,.T.);
#1100=ORIENTED_EDGE('',*,*,#1099,.T.);
#1101=CARTESIAN_POINT('',(0.,0.,5.2));
#1102=DIRECTION('',(0.,0.,1.));
#1103=DIRECTION('',(1.,0.,0.));
#1104=AXIS2_PLACEMENT_3D('',#1101,#1102,#1103);
#1105=CIRCLE('',#1104,6.);
#1106=CARTESIAN_POINT('',(3.07006806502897,5.15506373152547,5.2));
#1107=VERTEX_POINT('',#1106);
#1108=EDGE_CURVE('E339',#1107,#1098,#1105,.T.);
#1109=ORIENTED_EDGE('',*,*,#1108,.F.);
#1110=CARTESIAN_POINT('',(4.26810972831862,5.08653510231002,5.2));
#1111=DIRECTION('',(0.,0.,1.));
#1112=DIRECTION('',(1.,0.,0.));
#1113=AXIS2_PLACEMENT_3D('',#1110,#1111,#1112);
#1114=CIRCLE('',#1113,1.2);
#1115=CARTESIAN_POINT('',(4.54363500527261,3.91859425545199,5.2));
#1116=VERTEX_POINT('',#1115);
#1117=EDGE_CURVE('E336',#1107,#1116,#1114,.T.);
#1118=ORIENTED_EDGE('',*,*,#1117,.T.);
#1119=CARTESIAN_POINT('',(0.,0.,5.2));
#1120=DIRECTION('',(0.,0.,1.));
#1121=DIRECTION('',(1.,0.,0.));
#1122=AXIS2_PLACEMENT_3D('',#1119,#1120,#1121);
#1123=CIRCLE('',#1122,6.);
#1124=CARTESIAN_POINT('',(5.6654196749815,1.97560621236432,5.2));
#1125=VERTEX_POINT('',#1124);
#1126=EDGE_CURVE('E334',#1125,#1116,#1123,.T.);
#1127=ORIENTED_EDGE('',*,*,#1126,.F.);
#1128=CARTESIAN_POINT('',(6.53912348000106,1.15302389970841,5.2));
#1129=DIRECTION('',(0.,0.,1.));
#1130=DIRECTION('',(1.,0.,0.));
#1131=AXIS2_PLACEMENT_3D('',#1128,#1129,#1130);
#1132=CIRCLE('',#1131,1.2);
#1133=CARTESIAN_POINT('',(5.99945018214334,0.0812250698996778,5.2));
#1134=VERTEX_POINT('',#1133);
#1135=EDGE_CURVE('E331',#1125,#1134,#1132,.T.);
#1136=ORIENTED_EDGE('',*,*,#1135,.T.);
#1137=CARTESIAN_POINT('',(0.,0.,5.2));
#1138=DIRECTION('',(0.,0.,1.));
#1139=DIRECTION('',(1.,0.,0.));
#1140=AXIS2_PLACEMENT_3D('',#1137,#1138,#1139);
#1141=CIRCLE('',#1140,6.);
#1142=CARTESIAN_POINT('',(5.60985845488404,-2.12825940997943,5.2));
#1143=VERTEX_POINT('',#1142);
#1144=EDGE_CURVE('E329',#1143,#1134,#1141,.T.);
#1145=ORIENTED_EDGE('',*,*,#1144,.F.);
#1146=CARTESIAN_POINT('',(5.75040868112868,-3.32,5.2));
#1147=DIRECTION('',(0.,0.,1.));
#1148=DIRECTION('',(1.,0.,0.));
#1149=AXIS2_PLACEMENT_3D('',#1146,#1147,#1148);
#1150=CIRCLE('',#1149,1.2);
#1151=CARTESIAN_POINT('',(4.64805594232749,-3.79415022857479,5.2));
#1152=VERTEX_POINT('',#1151);
#1153=EDGE_CURVE('E326',#1143,#1152,#1150,.T.);
#1154=ORIENTED_EDGE('',*,*,#1153,.T.);
#1155=CARTESIAN_POINT('',(0.,0.,5.2));
#1156=DIRECTION('',(0.,0.,1.));
#1157=DIRECTION('',(1.,0.,0.));
#1158=AXIS2_PLACEMENT_3D('',#1155,#1156,#1157);
#1159=CIRCLE('',#1158,6.);
#1160=CARTESIAN_POINT('',(2.92938211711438,-5.23628880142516,5.2));
#1161=VERTEX_POINT('',#1160);
#1162=EDGE_CURVE('E324',#1161,#1152,#1159,.T.);
#1163=ORIENTED_EDGE('',*,*,#1162,.F.);
#1164=CARTESIAN_POINT('',(2.27101375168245,-6.23955900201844,5.2));
#1165=DIRECTION('',(0.,0.,1.));
#1166=DIRECTION('',(1.,0.,0.));
#1167=AXIS2_PLACEMENT_3D('',#1164,#1165,#1166);
#1168=CIRCLE('',#1167,1.2);
#1169=CARTESIAN_POINT('',(1.12178466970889,-5.89420046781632,5.2));
#1170=VERTEX_POINT('',#1169);
#1171=EDGE_CURVE('E321',#1161,#1170,#1168,.T.);
#1172=ORIENTED_EDGE('',*,*,#1171,.T.);
#1173=CARTESIAN_POINT('',(0.,0.,5.2));
#1174=DIRECTION('',(0.,0.,1.));
#1175=DIRECTION('',(1.,0.,0.));
#1176=AXIS2_PLACEMENT_3D('',#1173,#1174,#1175);
#1177=CIRCLE('',#1176,6.);
#1178=CARTESIAN_POINT('',(-1.1217846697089,-5.89420046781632,5.2));
#1179=VERTEX_POINT('',#1178);
#1180=EDGE_CURVE('E319',#1179,#1170,#1177,.T.);
#1181=ORIENTED_EDGE('',*,*,#1180,.F.);
#1182=CARTESIAN_POINT('',(-2.27101375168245,-6.23955900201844,5.2));
#1183=DIRECTION('',(0.,0.,1.));
#1184=DIRECTION('',(1.,0.,0.));
#1185=AXIS2_PLACEMENT_3D('',#1182,#1183,#1184);
#1186=CIRCLE('',#1185,1.2);
#1187=CARTESIAN_POINT('',(-2.92938211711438,-5.23628880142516,5.2));
#1188=VERTEX_POINT('',#1187);
#1189=EDGE_CURVE('E316',#1179,#1188,#1186,.T.);
#1190=ORIENTED_EDGE('',*,*,#1189,.T.);
#1191=CARTESIAN_POINT('',(0.,0.,5.2));
#1192=DIRECTION('',(0.,0.,1.));
#1193=DIRECTION('',(1.,0.,0.));
#1194=AXIS2_PLACEMENT_3D('',#1191,#1192,#1193);
#1195=CIRCLE('',#1194,6.);
#1196=CARTESIAN_POINT('',(-4.64805594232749,-3.79415022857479,5.2));
#1197=VERTEX_POINT('',#1196);
#1198=EDGE_CURVE('E314',#1197,#1188,#1195,.T.);
#1199=ORIENTED_EDGE('',*,*,#1198,.F.);
#1200=CARTESIAN_POINT('',(-5.75040868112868,-3.32,5.2));
#1201=DIRECTION('',(0.,0.,1.));
#1202=DIRECTION('',(1.,0.,0.));
#1203=AXIS2_PLACEMENT_3D('',#1200,#1201,#1202);
#1204=CIRCLE('',#1203,1.2);
#1205=CARTESIAN_POINT('',(-5.60985845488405,-2.12825940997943,5.2));
#1206=VERTEX_POINT('',#1205);
#1207=EDGE_CURVE('E311',#1197,#1206,#1204,.T.);
#1208=ORIENTED_EDGE('',*,*,#1207,.T.);
#1209=CARTESIAN_POINT('',(0.,0.,5.2));
#1210=DIRECTION('',(0.,0.,1.));
#1211=DIRECTION('',(1.,0.,0.));
#1212=AXIS2_PLACEMENT_3D('',#1209,#1210,#1211);
#1213=CIRCLE('',#1212,6.);
#1214=EDGE_CURVE('E354',#1060,#1206,#1213,.T.);
#1215=ORIENTED_EDGE('',*,*,#1214,.F.);
#1216=EDGE_LOOP('',(#1064,#1073,#1082,#1091,#1100,#1109,#1118,#1127,#1136,#1145,#1154,#1163,
#1172,#1181,#1190,#1199,#1208,#1215));
#1217=FACE_BOUND('',#1216,.T.);
#1218=ADVANCED_FACE('F484',(#1053,#1217),#1042,.T.);
#1219=CARTESIAN_POINT('',(0.,5.26,4.));
#1220=DIRECTION('',(0.,0.,-1.));
#1221=DIRECTION('',(-1.,0.,0.));
#1222=AXIS2_PLACEMENT_3D('',#1219,#1220,#1221);
#1223=PLANE('',#1222);
#1224=ORIENTED_EDGE('',*,*,#1030,.T.);
#1225=EDGE_LOOP('',(#1224));
#1226=FACE_BOUND('',#1225,.T.);
#1227=CARTESIAN_POINT('',(0.,0.,4.));
#1228=DIRECTION('',(0.,0.,1.));
#1229=DIRECTION('',(1.,0.,0.));
#1230=AXIS2_PLACEMENT_3D('',#1227,#1228,#1229);
#1231=CIRCLE('',#1230,5.26);
#1232=CARTESIAN_POINT('',(5.26,0.,4.));
#1233=VERTEX_POINT('',#1232);
#1234=EDGE_CURVE('E200',#1233,#1233,#1231,.T.);
#1235=ORIENTED_EDGE('',*,*,#1234,.F.);
#1236=EDGE_LOOP('',(#1235));
#1237=FACE_BOUND('',#1236,.T.);
#1238=ADVANCED_FACE('F482',(#1226,#1237),#1223,.T.);
#1239=CARTESIAN_POINT('',(0.,0.,12.));
#1240=DIRECTION('',(0.,0.,1.));
#1241=DIRECTION('',(1.,0.,0.));
#1242=AXIS2_PLACEMENT_3D('',#1239,#1240,#1241);
#1243=CYLINDRICAL_SURFACE('',#1242,6.01);
#1244=CARTESIAN_POINT('',(0.,0.,4.75));
#1245=DIRECTION('',(0.,0.,1.));
#1246=DIRECTION('',(1.,0.,0.));
#1247=AXIS2_PLACEMENT_3D('',#1244,#1245,#1246);
#1248=CIRCLE('',#1247,6.01);
#1249=CARTESIAN_POINT('',(6.01,0.,4.75));
#1250=VERTEX_POINT('',#1249);
#1251=EDGE_CURVE('E250',#1250,#1250,#1248,.T.);
#1252=ORIENTED_EDGE('',*,*,#1251,.T.);
#1253=EDGE_LOOP('',(#1252));
#1254=FACE_BOUND('',#1253,.T.);
#1255=ORIENTED_EDGE('',*,*,#1050,.F.);
#1256=EDGE_LOOP('',(#1255));
#1257=FACE_BOUND('',#1256,.T.);
#1258=ADVANCED_FACE('F478',(#1254,#1257),#1243,.T.);
#1259=CARTESIAN_POINT('',(0.,0.,4.75));
#1260=DIRECTION('',(0.,0.,1.));
#1261=DIRECTION('',(1.,0.,0.));
#1262=AXIS2_PLACEMENT_3D('',#1259,#1260,#1261);
#1263=CONICAL_SURFACE('',#1262,6.01,0.785398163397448);
#1264=ORIENTED_EDGE('',*,*,#1234,.T.);
#1265=EDGE_LOOP('',(#1264));
#1266=FACE_BOUND('',#1265,.T.);
#1267=ORIENTED_EDGE('',*,*,#1251,.F.);
#1268=EDGE_LOOP('',(#1267));
#1269=FACE_BOUND('',#1268,.T.);
#1270=ADVANCED_FACE('F475',(#1266,#1269),#1263,.T.);
#1271=CARTESIAN_POINT('',(0.,5.25,12.));
#1272=DIRECTION('',(0.,0.,-1.));
#1273=DIRECTION('',(-1.,0.,0.));
#1274=AXIS2_PLACEMENT_3D('',#1271,#1272,#1273);
#1275=PLANE('',#1274);
#1276=ORIENTED_EDGE('',*,*,#31,.F.);
#1277=EDGE_LOOP('',(#1276));
#1278=FACE_BOUND('',#1277,.T.);
#1279=CARTESIAN_POINT('',(0.,0.,12.));
#1280=DIRECTION('',(0.,0.,1.));
#1281=DIRECTION('',(1.,0.,0.));
#1282=AXIS2_PLACEMENT_3D('',#1279,#1280,#1281);
#1283=CIRCLE('',#1282,5.25);
#1284=CARTESIAN_POINT('',(5.25,0.,12.));
#1285=VERTEX_POINT('',#1284);
#1286=EDGE_CURVE('E359',#1285,#1285,#1283,.T.);
#1287=ORIENTED_EDGE('',*,*,#1286,.T.);
#1288=EDGE_LOOP('',(#1287));
#1289=FACE_BOUND('',#1288,.T.);
#1290=ADVANCED_FACE('F415',(#1278,#1289),#1275,.F.);
#1291=CARTESIAN_POINT('',(0.,0.,10.25));
#1292=DIRECTION('',(0.,0.,-1.));
#1293=DIRECTION('',(-1.,0.,0.));
#1294=AXIS2_PLACEMENT_3D('',#1291,#1292,#1293);
#1295=CONICAL_SURFACE('',#1294,7.,0.785398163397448);
#1296=ORIENTED_EDGE('',*,*,#1286,.F.);
#1297=EDGE_LOOP('',(#1296));
#1298=FACE_BOUND('',#1297,.T.);
#1299=CARTESIAN_POINT('',(0.,0.,11.25));
#1300=DIRECTION('',(0.,0.,-1.));
#1301=DIRECTION('',(-1.,0.,0.));
#1302=AXIS2_PLACEMENT_3D('',#1299,#1300,#1301);
#1303=CIRCLE('',#1302,6.);
#1304=CARTESIAN_POINT('',(-5.6654196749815,1.97560621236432,11.25));
#1305=VERTEX_POINT('',#1304);
#1306=CARTESIAN_POINT('',(-4.54363500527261,3.918594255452,11.25));
#1307=VERTEX_POINT('',#1306);
#1308=EDGE_CURVE('E505',#1305,#1307,#1303,.T.);
#1309=ORIENTED_EDGE('',*,*,#1308,.F.);
#1310=CARTESIAN_POINT('',(-6.1599348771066,2.29153872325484,10.6776376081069));
#1311=CARTESIAN_POINT('',(-6.11686247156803,2.2771796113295,10.7230063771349));
#1312=CARTESIAN_POINT('',(-6.07463808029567,2.26041349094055,10.7684330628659));
#1313=CARTESIAN_POINT('',(-5.99210689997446,2.2220680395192,10.8591555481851));
#1314=CARTESIAN_POINT('',(-5.95180363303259,2.20048025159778,10.9044509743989));
#1315=CARTESIAN_POINT('',(-5.87413099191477,2.15293523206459,10.9937651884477));
#1316=CARTESIAN_POINT('',(-5.83672441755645,2.12705522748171,11.0377927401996));
#1317=CARTESIAN_POINT('',(-5.76448823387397,2.07065048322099,11.1249114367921));
#1318=CARTESIAN_POINT('',(-5.72965566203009,2.0401312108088,11.1680036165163));
#1319=CARTESIAN_POINT('',(-5.68593417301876,1.99699045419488,11.2235762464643));
#1320=CARTESIAN_POINT('',(-5.67569770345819,1.98651663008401,11.2367020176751));
#1321=CARTESIAN_POINT('',(-5.61323978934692,1.92021622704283,11.317511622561));
#1322=CARTESIAN_POINT('',(-5.5648257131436,1.8582526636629,11.3833412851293));
#1323=CARTESIAN_POINT('',(-5.47875013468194,1.72063192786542,11.507654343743));
#1324=CARTESIAN_POINT('',(-5.44107335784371,1.64499446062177,11.5661481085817));
#1325=CARTESIAN_POINT('',(-5.39543000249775,1.51917191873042,11.6448951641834));
#1326=CARTESIAN_POINT('',(-5.38186987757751,1.47409800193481,11.6700642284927));
#1327=CARTESIAN_POINT('',(-5.35986422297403,1.38031798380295,11.715416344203));
#1328=CARTESIAN_POINT('',(-5.35141296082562,1.33161602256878,11.7356049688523));
#1329=CARTESIAN_POINT('',(-5.34055192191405,1.23067012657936,11.7696952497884));
#1330=CARTESIAN_POINT('',(-5.33821648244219,1.17839046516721,11.7835178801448));
#1331=CARTESIAN_POINT('',(-5.3406646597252,1.07248742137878,11.8029605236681));
#1332=CARTESIAN_POINT('',(-5.3454374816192,1.01886619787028,11.8085929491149));
#1333=CARTESIAN_POINT('',(-5.36097156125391,0.920512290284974,11.8107672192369));
#1334=CARTESIAN_POINT('',(-5.37073641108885,0.875643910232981,11.8085366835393));
#1335=CARTESIAN_POINT('',(-5.39508175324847,0.78800754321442,11.7978607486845));
#1336=CARTESIAN_POINT('',(-5.40966354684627,0.745240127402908,11.7894136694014));
#1337=CARTESIAN_POINT('',(-5.44220048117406,0.664581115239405,11.7675270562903));
#1338=CARTESIAN_POINT('',(-5.45999109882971,0.626560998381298,11.754308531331));
#1339=CARTESIAN_POINT('',(-5.49857999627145,0.553887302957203,11.7237252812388));
#1340=CARTESIAN_POINT('',(-5.51937976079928,0.519235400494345,11.7063585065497));
#1341=CARTESIAN_POINT('',(-5.57668221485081,0.433475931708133,11.6567748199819));
#1342=CARTESIAN_POINT('',(-5.61505797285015,0.385133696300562,11.6219393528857));
#1343=CARTESIAN_POINT('',(-5.69590085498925,0.297124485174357,11.5465441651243));
#1344=CARTESIAN_POINT('',(-5.73837696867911,0.257477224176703,11.5059717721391));
#1345=CARTESIAN_POINT('',(-5.81703260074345,0.193549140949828,11.4298226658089));
#1346=CARTESIAN_POINT('',(-5.85270425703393,0.16778551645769,11.3949411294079));
#1347=CARTESIAN_POINT('',(-5.92530521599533,0.120991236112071,11.3235097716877));
#1348=CARTESIAN_POINT('',(-5.9622324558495,0.0999532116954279,11.2869626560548));
#1349=CARTESIAN_POINT('',(-6.02334454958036,0.0692012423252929,11.226269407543));
#1350=CARTESIAN_POINT('',(-6.04723559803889,0.0581639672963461,11.2024911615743));
#1351=CARTESIAN_POINT('',(-6.0712814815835,0.0479791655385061,11.178528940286));
#1352=B_SPLINE_CURVE_WITH_KNOTS('',3,(#1310,#1311,#1312,#1313,#1314,#1315,#1316,#1317,#1318,
#1319,#1320,#1321,#1322,#1323,#1324,#1325,#1326,#1327,#1328,#1329,#1330,#1331,#1332,#1333,#1334,
#1335,#1336,#1337,#1338,#1339,#1340,#1341,#1342,#1343,#1344,#1345,#1346,#1347,#1348,#1349,#1350,
#1351),.UNSPECIFIED.,.F.,.F.,(4,2,2,2,2,2,2,2,2,2,2,2,2,2,2,2,2,2,2,2,4),(0.,0.192522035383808,
0.385384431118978,0.575092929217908,0.764579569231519,0.823579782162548,1.12980695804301,
1.43559630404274,1.5952480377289,1.75472029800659,1.91612212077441,2.0772790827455,
2.21446346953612,2.35168494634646,2.48322923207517,2.61483864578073,2.82626534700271,
3.03816658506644,3.20636997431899,3.37430923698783,3.48065494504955),.UNSPECIFIED.);
#1353=CARTESIAN_POINT('',(-5.99945018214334,0.0812250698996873,11.25));
#1354=VERTEX_POINT('',#1353);
#1355=EDGE_CURVE('E498',#1305,#1354,#1352,.T.);
#1356=ORIENTED_EDGE('',*,*,#1355,.T.);
#1357=CARTESIAN_POINT('',(0.,0.,11.25));
#1358=DIRECTION('',(0.,0.,-1.));
#1359=DIRECTION('',(-1.,0.,0.));
#1360=AXIS2_PLACEMENT_3D('',#1357,#1358,#1359);
#1361=CIRCLE('',#1360,6.);
#1362=CARTESIAN_POINT('',(-5.60985845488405,-2.12825940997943,11.25));
#1363=VERTEX_POINT('',#1362);
#1364=EDGE_CURVE('E539',#1363,#1354,#1361,.T.);
#1365=ORIENTED_EDGE('',*,*,#1364,.F.);
#1366=CARTESIAN_POINT('',(-5.61005845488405,-2.12823583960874,11.2498213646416));
#1367=CARTESIAN_POINT('',(-5.57252093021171,-2.13266944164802,11.283338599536));
#1368=CARTESIAN_POINT('',(-5.53473069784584,-2.13890671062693,11.3163898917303));
#1369=CARTESIAN_POINT('',(-5.45867233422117,-2.15534590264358,11.3812579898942));
#1370=CARTESIAN_POINT('',(-5.42040284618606,-2.16556477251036,11.413068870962));
#1371=CARTESIAN_POINT('',(-5.34314088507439,-2.19048515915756,11.475340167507));
#1372=CARTESIAN_POINT('',(-5.30414645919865,-2.20525422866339,11.5057717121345));
#1373=CARTESIAN_POINT('',(-5.22642551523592,-2.23960935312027,11.564015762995));
#1374=CARTESIAN_POINT('',(-5.18769862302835,-2.25918595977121,11.5918332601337));
#1375=CARTESIAN_POINT('',(-5.10952697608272,-2.30443032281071,11.6449768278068));
#1376=CARTESIAN_POINT('',(-5.0701066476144,-2.33029216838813,11.6701769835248));
#1377=CARTESIAN_POINT('',(-4.99297449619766,-2.38801206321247,11.7155080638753));
#1378=CARTESIAN_POINT('',(-4.95525655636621,-2.41984609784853,11.7356585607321));
#1379=CARTESIAN_POINT('',(-4.88211897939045,-2.49013609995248,11.7697117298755));
#1380=CARTESIAN_POINT('',(-4.84673656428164,-2.52867447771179,11.783527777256));
#1381=CARTESIAN_POINT('',(-4.78054460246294,-2.61137147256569,11.8029661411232));
#1382=CARTESIAN_POINT('',(-4.74973026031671,-2.65552410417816,11.8085971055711));
#1383=CARTESIAN_POINT('',(-4.69841023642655,-2.74086045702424,11.8107657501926));
#1384=CARTESIAN_POINT('',(-4.67705274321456,-2.78150694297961,11.8085328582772));
#1385=CARTESIAN_POINT('',(-4.63937589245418,-2.86428689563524,11.797852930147));
#1386=CARTESIAN_POINT('',(-4.62305804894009,-2.90642080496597,11.789404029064));
#1387=CARTESIAN_POINT('',(-4.59613736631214,-2.98913023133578,11.7675121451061));
#1388=CARTESIAN_POINT('',(-4.58532691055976,-3.02969849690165,11.7542890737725));
#1389=CARTESIAN_POINT('',(-4.56817849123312,-3.11017495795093,11.7237008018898));
#1390=CARTESIAN_POINT('',(-4.56184120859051,-3.15008305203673,11.7063349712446));
#1391=CARTESIAN_POINT('',(-4.55062321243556,-3.25254633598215,11.656779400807));
#1392=CARTESIAN_POINT('',(-4.54894548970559,-3.31418958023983,11.6219789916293));
#1393=CARTESIAN_POINT('',(-4.55429294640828,-3.43358530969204,11.5465861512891));
#1394=CARTESIAN_POINT('',(-4.56135475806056,-3.49132034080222,11.5059699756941));
#1395=CARTESIAN_POINT('',(-4.58055982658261,-3.59107215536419,11.4296524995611));
#1396=CARTESIAN_POINT('',(-4.59137215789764,-3.63389234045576,11.3946394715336));
#1397=CARTESIAN_POINT('',(-4.61694865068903,-3.71636110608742,11.3231961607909));
#1398=CARTESIAN_POINT('',(-4.63167409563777,-3.75603606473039,11.2867826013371));
#1399=CARTESIAN_POINT('',(-4.64814198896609,-3.79435022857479,11.2498068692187));
#1400=B_SPLINE_CURVE_WITH_KNOTS('',3,(#1366,#1367,#1368,#1369,#1370,#1371,#1372,#1373,#1374,
#1375,#1376,#1377,#1378,#1379,#1380,#1381,#1382,#1383,#1384,#1385,#1386,#1387,#1388,#1389,#1390,
#1391,#1392,#1393,#1394,#1395,#1396,#1397,#1398,#1399),.UNSPECIFIED.,.F.,.F.,(4,2,2,2,2,2,2,2,2,
2,2,2,2,2,2,2,4),(0.,0.151575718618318,0.303803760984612,0.458410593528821,0.612715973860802,
0.772582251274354,0.931818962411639,1.09317268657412,1.25435580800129,1.39153260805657,
1.52875057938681,1.66031965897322,1.7919087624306,2.0031404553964,2.21526054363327,
2.38409677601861,2.55132101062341),.UNSPECIFIED.);
#1401=CARTESIAN_POINT('',(-4.64805594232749,-3.79415022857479,11.25));
#1402=VERTEX_POINT('',#1401);
#1403=EDGE_CURVE('E386',#1363,#1402,#1400,.T.);
#1404=ORIENTED_EDGE('',*,*,#1403,.T.);
#1405=CARTESIAN_POINT('',(0.,0.,11.25));
#1406=DIRECTION('',(0.,0.,-1.));
#1407=DIRECTION('',(-1.,0.,0.));
#1408=AXIS2_PLACEMENT_3D('',#1405,#1406,#1407);
#1409=CIRCLE('',#1408,6.);
#1410=CARTESIAN_POINT('',(-2.92938211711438,-5.23628880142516,11.25));
#1411=VERTEX_POINT('',#1410);
#1412=EDGE_CURVE('E395',#1411,#1402,#1409,.T.);
#1413=ORIENTED_EDGE('',*,*,#1412,.F.);
#1414=CARTESIAN_POINT('',(-2.92958211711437,-5.2364200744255,11.2497877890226));
#1415=CARTESIAN_POINT('',(-2.89797776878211,-5.21568693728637,11.2833053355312));
#1416=CARTESIAN_POINT('',(-2.86502047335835,-5.19617300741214,11.3163569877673));
#1417=CARTESIAN_POINT('',(-2.79619140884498,-5.15987494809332,11.381225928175));
#1418=CARTESIAN_POINT('',(-2.76030770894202,-5.14310292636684,11.4130372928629));
#1419=CARTESIAN_POINT('',(-2.68510515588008,-5.11252790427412,11.4753097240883));
#1420=CARTESIAN_POINT('',(-2.64574138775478,-5.09877539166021,11.5057419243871));
#1421=CARTESIAN_POINT('',(-2.5641227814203,-5.07513238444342,11.563987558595));
#1422=CARTESIAN_POINT('',(-2.52187372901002,-5.06523441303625,11.5918059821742));
#1423=CARTESIAN_POINT('',(-2.43290875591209,-5.04964252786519,11.6449527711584));
#1424=CARTESIAN_POINT('',(-2.38608667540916,-5.0441131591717,11.6701551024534));
#1425=CARTESIAN_POINT('',(-2.28989664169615,-5.03874611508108,11.715490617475));
#1426=CARTESIAN_POINT('',(-2.24053943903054,-5.0388861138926,11.7356433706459));
#1427=CARTESIAN_POINT('',(-2.13932862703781,-5.04571636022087,11.7697010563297));
#1428=CARTESIAN_POINT('',(-2.08745055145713,-5.05249367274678,11.7835193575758));
#1429=CARTESIAN_POINT('',(-1.98358434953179,-5.07329350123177,11.8029619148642));
#1430=CARTESIAN_POINT('',(-1.93159639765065,-5.08730834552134,11.8085948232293));
#1431=CARTESIAN_POINT('',(-1.8374264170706,-5.11969050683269,11.8107664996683));
#1432=CARTESIAN_POINT('',(-1.79493720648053,-5.13709858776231,11.808534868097));
#1433=CARTESIAN_POINT('',(-1.71286230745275,-5.17629264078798,11.7978570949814));
#1434=CARTESIAN_POINT('',(-1.67327749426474,-5.19807992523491,11.7894090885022));
#1435=CARTESIAN_POINT('',(-1.59948871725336,-5.24413387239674,11.7675188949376));
#1436=CARTESIAN_POINT('',(-1.56513026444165,-5.26826142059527,11.7542967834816));
#1437=CARTESIAN_POINT('',(-1.50026367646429,-5.31888583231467,11.7237103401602));
#1438=CARTESIAN_POINT('',(-1.46975612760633,-5.34538305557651,11.7063453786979));
#1439=CARTESIAN_POINT('',(-1.39530011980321,-5.41666129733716,11.6567925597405));
#1440=CARTESIAN_POINT('',(-1.35439124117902,-5.46280254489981,11.6219941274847));
#1441=CARTESIAN_POINT('',(-1.281740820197,-5.55769875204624,11.5466052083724));
#1442=CARTESIAN_POINT('',(-1.25003856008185,-5.60646388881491,11.5059909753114));
#1443=CARTESIAN_POINT('',(-1.20062762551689,-5.69522422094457,11.4296733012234));
#1444=CARTESIAN_POINT('',(-1.18138361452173,-5.73497942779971,11.3946578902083));
#1445=CARTESIAN_POINT('',(-1.14796240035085,-5.81460049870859,11.3232095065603));
#1446=CARTESIAN_POINT('',(-1.13373857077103,-5.85446168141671,11.2867932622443));
#1447=CARTESIAN_POINT('',(-1.12172458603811,-5.89440046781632,11.2498147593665));
#1448=B_SPLINE_CURVE_WITH_KNOTS('',3,(#1414,#1415,#1416,#1417,#1418,#1419,#1420,#1421,#1422,
#1423,#1424,#1425,#1426,#1427,#1428,#1429,#1430,#1431,#1432,#1433,#1434,#1435,#1436,#1437,#1438,
#1439,#1440,#1441,#1442,#1443,#1444,#1445,#1446,#1447),.UNSPECIFIED.,.F.,.F.,(4,2,2,2,2,2,2,2,2,
2,2,2,2,2,2,2,4),(0.,0.151575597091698,0.303803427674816,0.458409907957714,0.612714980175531,
0.77258668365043,0.93182887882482,1.09318830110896,1.25437703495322,1.39155669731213,
1.52877753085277,1.66034545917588,1.79193339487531,2.00315896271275,2.21527296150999,
2.38412244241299,2.55135964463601),.UNSPECIFIED.);
#1449=CARTESIAN_POINT('',(-1.1217846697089,-5.89420046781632,11.25));
#1450=VERTEX_POINT('',#1449);
#1451=EDGE_CURVE('E625',#1411,#1450,#1448,.T.);
#1452=ORIENTED_EDGE('',*,*,#1451,.T.);
#1453=CARTESIAN_POINT('',(0.,0.,11.25));
#1454=DIRECTION('',(0.,0.,-1.));
#1455=DIRECTION('',(-1.,0.,0.));
#1456=AXIS2_PLACEMENT_3D('',#1453,#1454,#1455);
#1457=CIRCLE('',#1456,6.);
#1458=CARTESIAN_POINT('',(1.12178466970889,-5.89420046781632,11.25));
#1459=VERTEX_POINT('',#1458);
#1460=EDGE_CURVE('E624',#1459,#1450,#1457,.T.);
#1461=ORIENTED_EDGE('',*,*,#1460,.F.);
#1462=CARTESIAN_POINT('',(1.12172458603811,-5.89440046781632,11.2498147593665));
#1463=CARTESIAN_POINT('',(1.13260891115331,-5.85820310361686,11.2833320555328));
#1464=CARTESIAN_POINT('',(1.14531337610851,-5.82207006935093,11.3163834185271));
#1465=CARTESIAN_POINT('',(1.17470969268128,-5.75002180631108,11.3812516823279));
#1466=CARTESIAN_POINT('',(1.19141846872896,-5.71410818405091,11.4130626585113));
#1467=CARTESIAN_POINT('',(1.22937607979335,-5.64234732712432,11.4753341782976));
#1468=CARTESIAN_POINT('',(1.25069177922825,-5.6065098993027,11.5057658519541));
#1469=CARTESIAN_POINT('',(1.29802043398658,-5.53593530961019,11.5640102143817));
#1470=CARTESIAN_POINT('',(1.32402414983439,-5.50119613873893,11.5918278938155));
#1471=CARTESIAN_POINT('',(1.38215501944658,-5.43206825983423,11.6449720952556));
#1472=CARTESIAN_POINT('',(1.41446910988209,-5.39773732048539,11.6701726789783));
#1473=CARTESIAN_POINT('',(1.4847057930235,-5.33179919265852,11.7155046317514));
#1474=CARTESIAN_POINT('',(1.52260579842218,-5.30018181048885,11.7356555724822));
#1475=CARTESIAN_POINT('',(1.60452815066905,-5.24036028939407,11.7697096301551));
#1476=CARTESIAN_POINT('',(1.64862519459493,-5.21220711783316,11.7835261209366));
#1477=CARTESIAN_POINT('',(1.74156019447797,-5.16138012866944,11.8029653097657));
#1478=CARTESIAN_POINT('',(1.79039308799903,-5.13870054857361,11.8085966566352));
#1479=CARTESIAN_POINT('',(1.88334495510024,-5.10297805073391,11.8107658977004));
#1480=CARTESIAN_POINT('',(1.92708274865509,-5.0890029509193,11.8085332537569));
#1481=CARTESIAN_POINT('',(2.0151479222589,-5.06627259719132,11.7978537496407));
#1482=CARTESIAN_POINT('',(2.05947547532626,-5.05751891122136,11.7894050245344));
#1483=CARTESIAN_POINT('',(2.14560324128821,-5.04536920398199,11.7675134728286));
#1484=CARTESIAN_POINT('',(2.18743236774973,-5.04176743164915,11.754290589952));
#1485=CARTESIAN_POINT('',(2.26966396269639,-5.03885381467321,11.7237026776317));
#1486=CARTESIAN_POINT('',(2.31006621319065,-5.03954262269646,11.7063370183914));
#1487=CARTESIAN_POINT('',(2.41292058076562,-5.04628720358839,11.6567819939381));
#1488=CARTESIAN_POINT('',(2.4739184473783,-5.0553389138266,11.6219819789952));
#1489=CARTESIAN_POINT('',(2.59057137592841,-5.08133736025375,11.5465899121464));
#1490=CARTESIAN_POINT('',(2.64620288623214,-5.09831714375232,11.5059741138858));
#1491=CARTESIAN_POINT('',(2.74110894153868,-5.13455338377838,11.4296534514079));
#1492=CARTESIAN_POINT('',(2.78140538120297,-5.15263910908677,11.3946365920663));
#1493=CARTESIAN_POINT('',(2.85818779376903,-5.19215230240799,11.3231853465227));
#1494=CARTESIAN_POINT('',(2.89470647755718,-5.21354621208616,11.2867676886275));
#1495=CARTESIAN_POINT('',(2.92958211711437,-5.2364200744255,11.2497877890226));
#1496=B_SPLINE_CURVE_WITH_KNOTS('',3,(#1462,#1463,#1464,#1465,#1466,#1467,#1468,#1469,#1470,
#1471,#1472,#1473,#1474,#1475,#1476,#1477,#1478,#1479,#1480,#1481,#1482,#1483,#1484,#1485,#1486,
#1487,#1488,#1489,#1490,#1491,#1492,#1493,#1494,#1495),.UNSPECIFIED.,.F.,.F.,(4,2,2,2,2,2,2,2,2,
2,2,2,2,2,2,2,4),(0.,0.151575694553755,0.303803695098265,0.458410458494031,0.612715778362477,
0.772583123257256,0.931820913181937,1.09317575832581,1.25435998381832,1.39153734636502,
1.5287558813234,1.66032473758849,1.79191360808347,2.00314406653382,2.21526298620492,
2.38411749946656,2.55135967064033),.UNSPECIFIED.);
#1497=CARTESIAN_POINT('',(2.92938211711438,-5.23628880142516,11.25));
#1498=VERTEX_POINT('',#1497);
#1499=EDGE_CURVE('E617',#1459,#1498,#1496,.T.);
#1500=ORIENTED_EDGE('',*,*,#1499,.T.);
#1501=CARTESIAN_POINT('',(0.,0.,11.25));
#1502=DIRECTION('',(0.,0.,-1.));
#1503=DIRECTION('',(-1.,0.,0.));
#1504=AXIS2_PLACEMENT_3D('',#1501,#1502,#1503);
#1505=CIRCLE('',#1504,6.);
#1506=CARTESIAN_POINT('',(4.64805594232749,-3.79415022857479,11.25));
#1507=VERTEX_POINT('',#1506);
#1508=EDGE_CURVE('E600',#1507,#1498,#1505,.T.);
#1509=ORIENTED_EDGE('',*,*,#1508,.F.);
#1510=CARTESIAN_POINT('',(4.6481419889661,-3.79435022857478,11.2498068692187));
#1511=CARTESIAN_POINT('',(4.63321242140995,-3.75962531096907,11.2833242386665));
#1512=CARTESIAN_POINT('',(4.61971850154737,-3.72377971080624,11.3163756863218));
#1513=CARTESIAN_POINT('',(4.59592515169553,-3.64969232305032,11.3812441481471));
#1514=CARTESIAN_POINT('',(4.5856397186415,-3.61144088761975,11.4130552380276));
#1515=CARTESIAN_POINT('',(4.56858937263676,-3.5320705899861,11.4753270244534));
#1516=CARTESIAN_POINT('',(4.56188198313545,-3.49091626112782,11.5057588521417));
#1517=CARTESIAN_POINT('',(4.55277269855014,-3.40643110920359,11.5640035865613));
#1518=CARTESIAN_POINT('',(4.55036243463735,-3.36310468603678,11.5918214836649));
#1519=CARTESIAN_POINT('',(4.55045793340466,-3.27278383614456,11.6449664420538));
#1520=CARTESIAN_POINT('',(4.55314407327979,-3.22571348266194,11.6701675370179));
#1521=CARTESIAN_POINT('',(4.56456355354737,-3.13005413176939,11.7155005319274));
#1522=CARTESIAN_POINT('',(4.57327303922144,-3.08147184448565,11.7356520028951));
#1523=CARTESIAN_POINT('',(4.59757606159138,-2.98298649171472,11.7697071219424));
#1524=CARTESIAN_POINT('',(4.61325958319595,-2.9330744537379,11.7835241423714));
#1525=CARTESIAN_POINT('',(4.65178056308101,-2.83440032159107,11.8029643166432));
#1526=CARTESIAN_POINT('',(4.67461043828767,-2.78563706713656,11.8085961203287));
#1527=CARTESIAN_POINT('',(4.72285353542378,-2.6985228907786,11.810766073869));
#1528=CARTESIAN_POINT('',(4.74737552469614,-2.65970289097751,11.8085337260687));
#1529=CARTESIAN_POINT('',(4.80022648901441,-2.5856825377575,11.7978547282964));
#1530=CARTESIAN_POINT('',(4.82855660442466,-2.55048327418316,11.7894062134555));
#1531=CARTESIAN_POINT('',(4.88672448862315,-2.48581376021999,11.7675150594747));
#1532=CARTESIAN_POINT('',(4.91645213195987,-2.45616728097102,11.754292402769));
#1533=CARTESIAN_POINT('',(4.97757207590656,-2.40107761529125,11.7237049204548));
#1534=CARTESIAN_POINT('',(5.00896462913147,-2.37563506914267,11.7063394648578));
#1535=CARTESIAN_POINT('',(5.09209045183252,-2.31468800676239,11.6567850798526));
#1536=CARTESIAN_POINT('',(5.14463545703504,-2.28241323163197,11.6219855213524));
#1537=CARTESIAN_POINT('',(5.25070748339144,-2.22734583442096,11.5465943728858));
#1538=CARTESIAN_POINT('',(5.30423770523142,-2.20459366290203,11.5059790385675));
#1539=CARTESIAN_POINT('',(5.40022651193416,-2.1713491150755,11.4296631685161));
#1540=CARTESIAN_POINT('',(5.44271538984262,-2.159302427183,11.3946509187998));
#1541=CARTESIAN_POINT('',(5.52692241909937,-2.14021713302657,11.3232091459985));
#1542=CARTESIAN_POINT('',(5.56864405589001,-2.13313180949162,11.2867963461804));
#1543=CARTESIAN_POINT('',(5.61005845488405,-2.12823583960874,11.2498213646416));
#1544=B_SPLINE_CURVE_WITH_KNOTS('',3,(#1510,#1511,#1512,#1513,#1514,#1515,#1516,#1517,#1518,
#1519,#1520,#1521,#1522,#1523,#1524,#1525,#1526,#1527,#1528,#1529,#1530,#1531,#1532,#1533,#1534,
#1535,#1536,#1537,#1538,#1539,#1540,#1541,#1542,#1543),.UNSPECIFIED.,.F.,.F.,(4,2,2,2,2,2,2,2,2,
2,2,2,2,2,2,2,4),(0.,0.151575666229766,0.303803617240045,0.458410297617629,0.612715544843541,
0.772584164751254,0.931823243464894,1.09317942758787,1.25436497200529,1.39154300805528,
1.52876221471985,1.66033079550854,1.79191939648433,2.00314846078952,2.21526590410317,
2.38409943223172,2.5513209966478),.UNSPECIFIED.);
#1545=CARTESIAN_POINT('',(5.60985845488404,-2.12825940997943,11.25));
#1546=VERTEX_POINT('',#1545);
#1547=EDGE_CURVE('E593',#1507,#1546,#1544,.T.);
#1548=ORIENTED_EDGE('',*,*,#1547,.T.);
#1549=CARTESIAN_POINT('',(0.,0.,11.25));
#1550=DIRECTION('',(0.,0.,-1.));
#1551=DIRECTION('',(-1.,0.,0.));
#1552=AXIS2_PLACEMENT_3D('',#1549,#1550,#1551);
#1553=CIRCLE('',#1552,6.);
#1554=CARTESIAN_POINT('',(5.99945018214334,0.0812250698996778,11.25));
#1555=VERTEX_POINT('',#1554);
#1556=EDGE_CURVE('E591',#1555,#1546,#1553,.T.);
#1557=ORIENTED_EDGE('',*,*,#1556,.F.);
#1558=CARTESIAN_POINT('',(6.07128148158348,0.0479791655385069,11.178528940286));
#1559=CARTESIAN_POINT('',(6.04723780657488,0.058161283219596,11.2024890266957));
#1560=CARTESIAN_POINT('',(6.02334563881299,0.0691997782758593,11.2262683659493));
#1561=CARTESIAN_POINT('',(5.96549724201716,0.0983116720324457,11.2837201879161));
#1562=CARTESIAN_POINT('',(5.93175295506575,0.11733979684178,11.3171272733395));
#1563=CARTESIAN_POINT('',(5.8653344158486,0.159267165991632,11.3825429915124));
#1564=CARTESIAN_POINT('',(5.83266075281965,0.182168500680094,11.4145508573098));
#1565=CARTESIAN_POINT('',(5.73679061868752,0.257018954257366,11.5076966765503));
#1566=CARTESIAN_POINT('',(5.6755016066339,0.315231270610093,11.5662007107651));
#1567=CARTESIAN_POINT('',(5.58959381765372,0.417839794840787,11.6449306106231));
#1568=CARTESIAN_POINT('',(5.56144410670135,0.455551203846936,11.6700911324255));
#1569=CARTESIAN_POINT('',(5.50869862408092,0.536146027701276,11.7154352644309));
#1570=CARTESIAN_POINT('',(5.48409942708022,0.579024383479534,11.7356236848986));
#1571=CARTESIAN_POINT('',(5.43937033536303,0.670171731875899,11.769710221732));
#1572=CARTESIAN_POINT('',(5.41929779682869,0.718499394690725,11.7835297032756));
#1573=CARTESIAN_POINT('',(5.38538295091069,0.818850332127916,11.8029662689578));
#1574=CARTESIAN_POINT('',(5.37153105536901,0.870867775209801,11.8085960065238));
#1575=CARTESIAN_POINT('',(5.35249337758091,0.96859912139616,11.8107662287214));
#1576=CARTESIAN_POINT('',(5.34632509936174,1.0140998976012,11.808534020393));
#1577=CARTESIAN_POINT('',(5.33923167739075,1.10477502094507,11.797855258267));
#1578=CARTESIAN_POINT('',(5.33830801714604,1.14994927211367,11.7894069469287));
#1579=CARTESIAN_POINT('',(5.34129791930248,1.23687126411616,11.7675179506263));
#1580=CARTESIAN_POINT('',(5.34501310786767,1.27868345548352,11.7542980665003));
#1581=CARTESIAN_POINT('',(5.35642111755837,1.3601724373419,11.7237123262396));
#1582=CARTESIAN_POINT('',(5.36411587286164,1.39984817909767,11.7063444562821));
#1583=CARTESIAN_POINT('',(5.38863486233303,1.50003837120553,11.6567556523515));
#1584=CARTESIAN_POINT('',(5.40816564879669,1.55859435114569,11.6219155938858));
#1585=CARTESIAN_POINT('',(5.4540373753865,1.66894643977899,11.5465146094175));
#1586=CARTESIAN_POINT('',(5.48039283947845,1.72072777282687,11.5059415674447));
#1587=CARTESIAN_POINT('',(5.53243498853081,1.80768747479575,11.4298020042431));
#1588=CARTESIAN_POINT('',(5.55713626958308,1.84408644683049,11.3949313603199));
#1589=CARTESIAN_POINT('',(5.60935632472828,1.91289045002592,11.3234969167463));
#1590=CARTESIAN_POINT('',(5.63687275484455,1.94529875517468,11.2869345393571));
#1591=CARTESIAN_POINT('',(5.70078527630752,2.01315296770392,11.2042432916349));
#1592=CARTESIAN_POINT('',(5.73778911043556,2.04765105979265,11.1578073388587));
#1593=CARTESIAN_POINT('',(5.8149268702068,2.11116635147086,11.0637151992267));
#1594=CARTESIAN_POINT('',(5.85506435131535,2.14017719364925,11.0160576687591));
#1595=CARTESIAN_POINT('',(5.93805314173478,2.19279987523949,10.920013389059));
#1596=CARTESIAN_POINT('',(5.98090786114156,2.21640475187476,10.8716257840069));
#1597=CARTESIAN_POINT('',(6.06883364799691,2.25809332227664,10.77468201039));
#1598=CARTESIAN_POINT('',(6.11390003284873,2.27618814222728,10.7261263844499));
#1599=CARTESIAN_POINT('',(6.1599348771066,2.29153872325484,10.6776376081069));
#1600=B_SPLINE_CURVE_WITH_KNOTS('',3,(#1558,#1559,#1560,#1561,#1562,#1563,#1564,#1565,#1566,
#1567,#1568,#1569,#1570,#1571,#1572,#1573,#1574,#1575,#1576,#1577,#1578,#1579,#1580,#1581,#1582,
#1583,#1584,#1585,#1586,#1587,#1588,#1589,#1590,#1591,#1592,#1593,#1594,#1595,#1596,#1597,#1598,
#1599),.UNSPECIFIED.,.F.,.F.,(4,2,2,2,2,2,2,2,2,2,2,2,2,2,2,2,2,2,2,2,4),(0.,0.106345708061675,
0.259624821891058,0.412986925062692,0.718632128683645,0.878264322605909,1.03774146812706,
1.19913808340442,1.36028506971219,1.49746475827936,1.63468324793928,1.76622965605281,
1.89784005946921,2.10928535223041,2.32118438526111,2.48933351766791,2.65734376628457,
2.86301930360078,3.06893169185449,3.2751078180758,3.48086481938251),.UNSPECIFIED.);
#1601=CARTESIAN_POINT('',(5.6654196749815,1.97560621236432,11.25));
#1602=VERTEX_POINT('',#1601);
#1603=EDGE_CURVE('E565',#1555,#1602,#1600,.T.);
#1604=ORIENTED_EDGE('',*,*,#1603,.T.);
#1605=CARTESIAN_POINT('',(0.,0.,11.25));
#1606=DIRECTION('',(0.,0.,-1.));
#1607=DIRECTION('',(-1.,0.,0.));
#1608=AXIS2_PLACEMENT_3D('',#1605,#1606,#1607);
#1609=CIRCLE('',#1608,6.);
#1610=CARTESIAN_POINT('',(4.54363500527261,3.91859425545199,11.25));
#1611=VERTEX_POINT('',#1610);
#1612=EDGE_CURVE('E564',#1611,#1602,#1609,.T.);
#1613=ORIENTED_EDGE('',*,*,#1612,.F.);
#1614=CARTESIAN_POINT('',(4.54383500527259,3.91864145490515,11.2498177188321));
#1615=CARTESIAN_POINT('',(4.50704495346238,3.9099689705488,11.2833349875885));
#1616=CARTESIAN_POINT('',(4.46940054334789,3.90290494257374,11.3163863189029));
#1617=CARTESIAN_POINT('',(4.39230665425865,3.89233897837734,11.3812545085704));
#1618=CARTESIAN_POINT('',(4.35285010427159,3.88885250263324,11.4130654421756));
#1619=CARTESIAN_POINT('',(4.27172446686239,3.88584456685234,11.4753368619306));
#1620=CARTESIAN_POINT('',(4.23003044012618,3.88638591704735,11.5057684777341));
#1621=CARTESIAN_POINT('',(4.14524662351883,3.8920867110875,11.5640127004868));
#1622=CARTESIAN_POINT('',(4.10215971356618,3.89723714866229,11.5918302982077));
#1623=CARTESIAN_POINT('',(4.01322783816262,3.91301630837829,11.6449742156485));
#1624=CARTESIAN_POINT('',(3.96733943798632,3.92383578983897,11.6701746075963));
#1625=CARTESIAN_POINT('',(3.87511725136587,3.95169371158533,11.7155061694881));
#1626=CARTESIAN_POINT('',(3.82878593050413,3.96870749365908,11.7356569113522));
#1627=CARTESIAN_POINT('',(3.73601810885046,4.00974374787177,11.7697105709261));
#1628=CARTESIAN_POINT('',(3.68958839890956,4.03385639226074,11.7835268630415));
#1629=CARTESIAN_POINT('',(3.59910380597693,4.08892705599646,11.8029656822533));
#1630=CARTESIAN_POINT('',(3.55504646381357,4.1198778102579,11.8085968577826));
#1631=CARTESIAN_POINT('',(3.4776342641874,4.18251525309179,11.8107658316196));
#1632=CARTESIAN_POINT('',(3.44366270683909,4.21340575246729,11.8085330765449));
#1633=CARTESIAN_POINT('',(3.37994531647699,4.27830723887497,11.7978533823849));
#1634=CARTESIAN_POINT('',(3.35020075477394,4.31231915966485,11.7894045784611));
#1635=CARTESIAN_POINT('',(3.29661508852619,4.38083315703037,11.7675128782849));
#1636=CARTESIAN_POINT('',(3.27258135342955,4.41525740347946,11.7542899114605));
#1637=CARTESIAN_POINT('',(3.22894240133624,4.48501533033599,11.723701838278));
#1638=CARTESIAN_POINT('',(3.20933785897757,4.52034914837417,11.7063361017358));
#1639=CARTESIAN_POINT('',(3.16375175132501,4.61279613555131,11.6567808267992));
#1640=CARTESIAN_POINT('',(3.14109189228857,4.67014785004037,11.62198062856));
#1641=CARTESIAN_POINT('',(3.10528091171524,4.78417174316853,11.5465882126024));
#1642=CARTESIAN_POINT('',(3.09217018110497,4.8408400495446,11.5059722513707));
#1643=CARTESIAN_POINT('',(3.07610005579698,4.94114195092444,11.4296569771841));
#1644=CARTESIAN_POINT('',(3.07161494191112,4.98507534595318,11.394646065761));
#1645=CARTESIAN_POINT('',(3.0674424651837,5.07131360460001,11.3232071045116));
#1646=CARTESIAN_POINT('',(3.06770970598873,5.11363001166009,11.2867957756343));
#1647=CARTESIAN_POINT('',(3.07007952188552,5.15526373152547,11.2498223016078));
#1648=B_SPLINE_CURVE_WITH_KNOTS('',3,(#1614,#1615,#1616,#1617,#1618,#1619,#1620,#1621,#1622,
#1623,#1624,#1625,#1626,#1627,#1628,#1629,#1630,#1631,#1632,#1633,#1634,#1635,#1636,#1637,#1638,
#1639,#1640,#1641,#1642,#1643,#1644,#1645,#1646,#1647),.UNSPECIFIED.,.F.,.F.,(4,2,2,2,2,2,2,2,2,
2,2,2,2,2,2,2,4),(0.,0.151575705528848,0.303803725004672,0.458410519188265,0.612715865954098,
0.772582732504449,0.931820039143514,1.09317438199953,1.25435811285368,1.3915352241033,
1.52875350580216,1.66032245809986,1.7919114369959,2.00314248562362,2.215261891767,
2.38408848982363,2.55130326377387),.UNSPECIFIED.);
#1649=CARTESIAN_POINT('',(3.07006806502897,5.15506373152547,11.25));
#1650=VERTEX_POINT('',#1649);
#1651=EDGE_CURVE('E560',#1611,#1650,#1648,.T.);
#1652=ORIENTED_EDGE('',*,*,#1651,.T.);
#1653=CARTESIAN_POINT('',(0.,0.,11.25));
#1654=DIRECTION('',(0.,0.,-1.));
#1655=DIRECTION('',(-1.,0.,0.));
#1656=AXIS2_PLACEMENT_3D('',#1653,#1654,#1655);
#1657=CIRCLE('',#1656,6.);
#1658=CARTESIAN_POINT('',(0.961802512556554,5.92240963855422,11.25));
#1659=VERTEX_POINT('',#1658);
#1660=EDGE_CURVE('E540',#1659,#1650,#1657,.T.);
#1661=ORIENTED_EDGE('',*,*,#1660,.F.);
#1662=CARTESIAN_POINT('',(0.961951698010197,5.92260963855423,11.2497786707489));
#1663=CARTESIAN_POINT('',(0.939344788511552,5.89231741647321,11.283296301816));
#1664=CARTESIAN_POINT('',(0.915049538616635,5.8627081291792,11.3163480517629));
#1665=CARTESIAN_POINT('',(0.862786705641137,5.80505789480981,11.3812172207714));
#1666=CARTESIAN_POINT('',(0.834803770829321,5.77702424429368,11.4130287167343));
#1667=CARTESIAN_POINT('',(0.77459448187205,5.72257198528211,11.4753014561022));
#1668=CARTESIAN_POINT('',(0.742308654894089,5.69618545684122,11.5057338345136));
#1669=CARTESIAN_POINT('',(0.673699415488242,5.64605265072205,11.5639798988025));
#1670=CARTESIAN_POINT('',(0.637383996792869,5.62230132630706,11.5917985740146));
#1671=CARTESIAN_POINT('',(0.559117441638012,5.57722113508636,11.6449462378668));
#1672=CARTESIAN_POINT('',(0.517010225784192,5.55601061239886,11.6701491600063));
#1673=CARTESIAN_POINT('',(0.428456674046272,5.51806726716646,11.7154858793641));
#1674=CARTESIAN_POINT('',(0.38202807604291,5.50131714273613,11.7356392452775));
#1675=CARTESIAN_POINT('',(0.284584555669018,5.47311830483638,11.7696981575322));
#1676=CARTESIAN_POINT('',(0.233516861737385,5.46174303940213,11.7835170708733));
#1677=CARTESIAN_POINT('',(0.128799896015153,5.44576321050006,11.8029607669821));
#1678=CARTESIAN_POINT('',(0.0751534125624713,5.44115149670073,11.8085942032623));
#1679=CARTESIAN_POINT('',(-0.0244135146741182,5.43937206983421,11.8107667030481));
#1680=CARTESIAN_POINT('',(-0.0702945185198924,5.44119786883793,11.8085354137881));
#1681=CARTESIAN_POINT('',(-0.160825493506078,5.44995648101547,11.7978582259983));
#1682=CARTESIAN_POINT('',(-0.20547509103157,5.45689082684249,11.7894104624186));
#1683=CARTESIAN_POINT('',(-0.29056560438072,5.47492975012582,11.767520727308));
#1684=CARTESIAN_POINT('',(-0.331104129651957,5.48585072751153,11.7542988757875));
#1685=CARTESIAN_POINT('',(-0.409373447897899,5.51123601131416,11.7237129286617));
#1686=CARTESIAN_POINT('',(-0.447103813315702,5.52570085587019,11.7063482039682));
#1687=CARTESIAN_POINT('',(-0.541448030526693,5.56721438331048,11.6567961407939));
#1688=CARTESIAN_POINT('',(-0.59567089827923,5.5965808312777,11.6219982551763));
#1689=CARTESIAN_POINT('',(-0.696396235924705,5.66090522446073,11.5466104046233));
#1690=CARTESIAN_POINT('',(-0.742865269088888,5.69588617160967,11.5059966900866));
#1691=CARTESIAN_POINT('',(-0.819661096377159,5.76239912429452,11.4296731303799));
#1692=CARTESIAN_POINT('',(-0.851347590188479,5.79318101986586,11.3946508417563));
#1693=CARTESIAN_POINT('',(-0.909995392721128,5.8565824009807,11.32318822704));
#1694=CARTESIAN_POINT('',(-0.936998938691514,5.88918152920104,11.2867646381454));
#1695=CARTESIAN_POINT('',(-0.961951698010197,5.92260963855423,11.2497786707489));
#1696=B_SPLINE_CURVE_WITH_KNOTS('',3,(#1662,#1663,#1664,#1665,#1666,#1667,#1668,#1669,#1670,
#1671,#1672,#1673,#1674,#1675,#1676,#1677,#1678,#1679,#1680,#1681,#1682,#1683,#1684,#1685,#1686,
#1687,#1688,#1689,#1690,#1691,#1692,#1693,#1694,#1695),.UNSPECIFIED.,.F.,.F.,(4,2,2,2,2,2,2,2,2,
2,2,2,2,2,2,2,4),(0.,0.151575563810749,0.303803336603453,0.458409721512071,0.612714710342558,
0.77258788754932,0.931831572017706,1.09319254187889,1.25438279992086,1.39156323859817,
1.52878485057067,1.66035247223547,1.79194008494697,2.00316393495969,2.2152763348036,
2.38415845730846,2.55142768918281),.UNSPECIFIED.);
#1697=CARTESIAN_POINT('',(-0.961802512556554,5.92240963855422,11.25));
#1698=VERTEX_POINT('',#1697);
#1699=EDGE_CURVE('E533',#1659,#1698,#1696,.T.);
#1700=ORIENTED_EDGE('',*,*,#1699,.T.);
#1701=CARTESIAN_POINT('',(0.,0.,11.25));
#1702=DIRECTION('',(0.,0.,-1.));
#1703=DIRECTION('',(-1.,0.,0.));
#1704=AXIS2_PLACEMENT_3D('',#1701,#1702,#1703);
#1705=CIRCLE('',#1704,6.);
#1706=CARTESIAN_POINT('',(-3.07006806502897,5.15506373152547,11.25));
#1707=VERTEX_POINT('',#1706);
#1708=EDGE_CURVE('E514',#1707,#1698,#1705,.T.);
#1709=ORIENTED_EDGE('',*,*,#1708,.F.);
#1710=CARTESIAN_POINT('',(-3.07007952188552,5.15526373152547,11.2498223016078));
#1711=CARTESIAN_POINT('',(-3.06792747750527,5.1175265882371,11.283339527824));
#1712=CARTESIAN_POINT('',(-3.06750781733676,5.07922737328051,11.3163908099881));
#1713=CARTESIAN_POINT('',(-3.07048993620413,5.00146985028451,11.3812588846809));
#1714=CARTESIAN_POINT('',(-3.0739081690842,4.96200726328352,11.4130697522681));
#1715=CARTESIAN_POINT('',(-3.08503364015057,4.88159168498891,11.4753410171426));
#1716=CARTESIAN_POINT('',(-3.09280706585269,4.84062504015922,11.5057725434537));
#1717=CARTESIAN_POINT('',(-3.11314424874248,4.75811913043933,11.5640165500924));
#1718=CARTESIAN_POINT('',(-3.12569863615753,4.71658113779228,11.5918340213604));
#1719=CARTESIAN_POINT('',(-3.15668135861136,4.63174052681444,11.644977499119));
#1720=CARTESIAN_POINT('',(-3.17530507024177,4.58842826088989,11.6701775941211));
#1721=CARTESIAN_POINT('',(-3.21875427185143,4.50244505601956,11.7155085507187));
#1722=CARTESIAN_POINT('',(-3.2435550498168,4.45977226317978,11.7356589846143));
#1723=CARTESIAN_POINT('',(-3.30007701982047,4.3755401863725,11.7697120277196));
#1724=CARTESIAN_POINT('',(-3.33188583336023,4.33400324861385,11.7835280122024));
#1725=CARTESIAN_POINT('',(-3.40183236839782,4.25445682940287,11.8029662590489));
#1726=CARTESIAN_POINT('',(-3.43996336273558,4.21644366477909,11.8085971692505));
#1727=CARTESIAN_POINT('',(-3.51509162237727,4.15108490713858,11.8107657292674));
#1728=CARTESIAN_POINT('',(-3.55141190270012,4.12299373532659,11.8085328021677));
#1729=CARTESIAN_POINT('',(-3.6263917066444,4.07151477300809,11.7978528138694));
#1730=CARTESIAN_POINT('',(-3.66505192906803,4.04812839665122,11.7894038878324));
#1731=CARTESIAN_POINT('',(-3.74183008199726,4.00725441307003,11.7675119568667));
#1732=CARTESIAN_POINT('',(-3.77990482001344,3.9895636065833,11.7542888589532));
#1733=CARTESIAN_POINT('',(-3.85618089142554,3.95870115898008,11.7237005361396));
#1734=CARTESIAN_POINT('',(-3.89438224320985,3.94553020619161,11.7063346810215));
#1735=CARTESIAN_POINT('',(-3.99334095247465,3.91669011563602,11.6567790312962));
#1736=CARTESIAN_POINT('',(-4.05375640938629,3.90433367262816,11.6219785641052));
#1737=CARTESIAN_POINT('',(-4.17226690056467,3.88886710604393,11.546585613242));
#1738=CARTESIAN_POINT('',(-4.23035110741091,3.8857960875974,11.505969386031));
#1739=CARTESIAN_POINT('',(-4.3319200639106,3.8873877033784,11.4296536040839));
#1740=CARTESIAN_POINT('',(-4.37596500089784,3.89059985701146,11.3946424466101));
#1741=CARTESIAN_POINT('',(-4.4616179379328,3.90146626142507,11.3232029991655));
#1742=CARTESIAN_POINT('',(-4.5032451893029,3.90907780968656,11.2867914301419));
#1743=CARTESIAN_POINT('',(-4.54383500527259,3.91864145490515,11.2498177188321));
#1744=B_SPLINE_CURVE_WITH_KNOTS('',3,(#1710,#1711,#1712,#1713,#1714,#1715,#1716,#1717,#1718,
#1719,#1720,#1721,#1722,#1723,#1724,#1725,#1726,#1727,#1728,#1729,#1730,#1731,#1732,#1733,#1734,
#1735,#1736,#1737,#1738,#1739,#1740,#1741,#1742,#1743),.UNSPECIFIED.,.F.,.F.,(4,2,2,2,2,2,2,2,2,
2,2,2,2,2,2,2,4),(0.,0.151575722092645,0.303803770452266,0.458410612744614,0.612716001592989,
0.772582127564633,0.931818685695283,1.09317225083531,1.25435521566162,1.39153193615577,
1.52874982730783,1.66031893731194,1.79190807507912,2.00313995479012,2.21526019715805,
2.38408765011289,2.5513032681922),.UNSPECIFIED.);
#1745=EDGE_CURVE('E507',#1707,#1307,#1744,.T.);
#1746=ORIENTED_EDGE('',*,*,#1745,.T.);
#1747=EDGE_LOOP('',(#1309,#1356,#1365,#1404,#1413,#1452,#1461,#1500,#1509,#1548,#1557,#1604,
#1613,#1652,#1661,#1700,#1709,#1746));
#1748=FACE_BOUND('',#1747,.T.);
#1749=ADVANCED_FACE('F397',(#1298,#1748),#1295,.T.);
#1750=CARTESIAN_POINT('',(-5.75040868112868,-3.32,4.));
#1751=DIRECTION('',(0.,0.,1.));
#1752=DIRECTION('',(1.,0.,0.));
#1753=AXIS2_PLACEMENT_3D('',#1750,#1751,#1752);
#1754=CYLINDRICAL_SURFACE('',#1753,1.2);
#1755=DIRECTION('',(0.,0.,1.));
#1756=VECTOR('',#1755,1.);
#1757=CARTESIAN_POINT('',(-4.64805594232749,-3.79415022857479,4.));
#1758=LINE('',#1757,#1756);
#1759=EDGE_CURVE('E42',#1197,#1402,#1758,.T.);
#1760=ORIENTED_EDGE('',*,*,#1759,.T.);
#1761=ORIENTED_EDGE('',*,*,#1403,.F.);
#1762=DIRECTION('',(0.,0.,1.));
#1763=VECTOR('',#1762,1.);
#1764=CARTESIAN_POINT('',(-5.60985845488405,-2.12825940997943,4.));
#1765=LINE('',#1764,#1763);
#1766=EDGE_CURVE('E259',#1206,#1363,#1765,.T.);
#1767=ORIENTED_EDGE('',*,*,#1766,.F.);
#1768=ORIENTED_EDGE('',*,*,#1207,.F.);
#1769=EDGE_LOOP('',(#1760,#1761,#1767,#1768));
#1770=FACE_BOUND('',#1769,.T.);
#1771=ADVANCED_FACE('F401',(#1770),#1754,.F.);
#1772=CARTESIAN_POINT('',(0.,0.,4.));
#1773=DIRECTION('',(0.,0.,1.));
#1774=DIRECTION('',(1.,0.,0.));
#1775=AXIS2_PLACEMENT_3D('',#1772,#1773,#1774);
#1776=CYLINDRICAL_SURFACE('',#1775,6.);
#1777=ORIENTED_EDGE('',*,*,#1198,.T.);
#1778=DIRECTION('',(0.,0.,1.));
#1779=VECTOR('',#1778,1.);
#1780=CARTESIAN_POINT('',(-2.92938211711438,-5.23628880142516,4.));
#1781=LINE('',#1780,#1779);
#1782=EDGE_CURVE('E303',#1188,#1411,#1781,.T.);
#1783=ORIENTED_EDGE('',*,*,#1782,.T.);
#1784=ORIENTED_EDGE('',*,*,#1412,.T.);
#1785=ORIENTED_EDGE('',*,*,#1759,.F.);
#1786=EDGE_LOOP('',(#1777,#1783,#1784,#1785));
#1787=FACE_BOUND('',#1786,.T.);
#1788=ADVANCED_FACE('F406',(#1787),#1776,.T.);
#1789=CARTESIAN_POINT('',(-2.27101375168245,-6.23955900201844,4.));
#1790=DIRECTION('',(0.,0.,1.));
#1791=DIRECTION('',(1.,0.,0.));
#1792=AXIS2_PLACEMENT_3D('',#1789,#1790,#1791);
#1793=CYLINDRICAL_SURFACE('',#1792,1.2);
#1794=DIRECTION('',(0.,0.,1.));
#1795=VECTOR('',#1794,1.);
#1796=CARTESIAN_POINT('',(-1.1217846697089,-5.89420046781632,4.));
#1797=LINE('',#1796,#1795);
#1798=EDGE_CURVE('E300',#1179,#1450,#1797,.T.);
#1799=ORIENTED_EDGE('',*,*,#1798,.T.);
#1800=ORIENTED_EDGE('',*,*,#1451,.F.);
#1801=ORIENTED_EDGE('',*,*,#1782,.F.);
#1802=ORIENTED_EDGE('',*,*,#1189,.F.);
#1803=EDGE_LOOP('',(#1799,#1800,#1801,#1802));
#1804=FACE_BOUND('',#1803,.T.);
#1805=ADVANCED_FACE('F631',(#1804),#1793,.F.);
#1806=CARTESIAN_POINT('',(0.,0.,4.));
#1807=DIRECTION('',(0.,0.,1.));
#1808=DIRECTION('',(1.,0.,0.));
#1809=AXIS2_PLACEMENT_3D('',#1806,#1807,#1808);
#1810=CYLINDRICAL_SURFACE('',#1809,6.);
#1811=ORIENTED_EDGE('',*,*,#1180,.T.);
#1812=DIRECTION('',(0.,0.,1.));
#1813=VECTOR('',#1812,1.);
#1814=CARTESIAN_POINT('',(1.12178466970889,-5.89420046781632,4.));
#1815=LINE('',#1814,#1813);
#1816=EDGE_CURVE('E297',#1170,#1459,#1815,.T.);
#1817=ORIENTED_EDGE('',*,*,#1816,.T.);
#1818=ORIENTED_EDGE('',*,*,#1460,.T.);
#1819=ORIENTED_EDGE('',*,*,#1798,.F.);
#1820=EDGE_LOOP('',(#1811,#1817,#1818,#1819));
#1821=FACE_BOUND('',#1820,.T.);
#1822=ADVANCED_FACE('F615',(#1821),#1810,.T.);
#1823=CARTESIAN_POINT('',(2.27101375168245,-6.23955900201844,4.));
#1824=DIRECTION('',(0.,0.,1.));
#1825=DIRECTION('',(1.,0.,0.));
#1826=AXIS2_PLACEMENT_3D('',#1823,#1824,#1825);
#1827=CYLINDRICAL_SURFACE('',#1826,1.2);
#1828=DIRECTION('',(0.,0.,1.));
#1829=VECTOR('',#1828,1.);
#1830=CARTESIAN_POINT('',(2.92938211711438,-5.23628880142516,4.));
#1831=LINE('',#1830,#1829);
#1832=EDGE_CURVE('E294',#1161,#1498,#1831,.T.);
#1833=ORIENTED_EDGE('',*,*,#1832,.T.);
#1834=ORIENTED_EDGE('',*,*,#1499,.F.);
#1835=ORIENTED_EDGE('',*,*,#1816,.F.);
#1836=ORIENTED_EDGE('',*,*,#1171,.F.);
#1837=EDGE_LOOP('',(#1833,#1834,#1835,#1836));
#1838=FACE_BOUND('',#1837,.T.);
#1839=ADVANCED_FACE('F610',(#1838),#1827,.F.);
#1840=CARTESIAN_POINT('',(0.,0.,4.));
#1841=DIRECTION('',(0.,0.,1.));
#1842=DIRECTION('',(1.,0.,0.));
#1843=AXIS2_PLACEMENT_3D('',#1840,#1841,#1842);
#1844=CYLINDRICAL_SURFACE('',#1843,6.);
#1845=ORIENTED_EDGE('',*,*,#1162,.T.);
#1846=DIRECTION('',(0.,0.,1.));
#1847=VECTOR('',#1846,1.);
#1848=CARTESIAN_POINT('',(4.64805594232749,-3.79415022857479,4.));
#1849=LINE('',#1848,#1847);
#1850=EDGE_CURVE('E291',#1152,#1507,#1849,.T.);
#1851=ORIENTED_EDGE('',*,*,#1850,.T.);
#1852=ORIENTED_EDGE('',*,*,#1508,.T.);
#1853=ORIENTED_EDGE('',*,*,#1832,.F.);
#1854=EDGE_LOOP('',(#1845,#1851,#1852,#1853));
#1855=FACE_BOUND('',#1854,.T.);
#1856=ADVANCED_FACE('F606',(#1855),#1844,.T.);
#1857=CARTESIAN_POINT('',(5.75040868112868,-3.32,4.));
#1858=DIRECTION('',(0.,0.,1.));
#1859=DIRECTION('',(1.,0.,0.));
#1860=AXIS2_PLACEMENT_3D('',#1857,#1858,#1859);
#1861=CYLINDRICAL_SURFACE('',#1860,1.2);
#1862=DIRECTION('',(0.,0.,1.));
#1863=VECTOR('',#1862,1.);
#1864=CARTESIAN_POINT('',(5.60985845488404,-2.12825940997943,4.));
#1865=LINE('',#1864,#1863);
#1866=EDGE_CURVE('E288',#1143,#1546,#1865,.T.);
#1867=ORIENTED_EDGE('',*,*,#1866,.T.);
#1868=ORIENTED_EDGE('',*,*,#1547,.F.);
#1869=ORIENTED_EDGE('',*,*,#1850,.F.);
#1870=ORIENTED_EDGE('',*,*,#1153,.F.);
#1871=EDGE_LOOP('',(#1867,#1868,#1869,#1870));
#1872=FACE_BOUND('',#1871,.T.);
#1873=ADVANCED_FACE('F602',(#1872),#1861,.F.);
#1874=CARTESIAN_POINT('',(0.,0.,4.));
#1875=DIRECTION('',(0.,0.,1.));
#1876=DIRECTION('',(1.,0.,0.));
#1877=AXIS2_PLACEMENT_3D('',#1874,#1875,#1876);
#1878=CYLINDRICAL_SURFACE('',#1877,6.);
#1879=ORIENTED_EDGE('',*,*,#1144,.T.);
#1880=DIRECTION('',(0.,0.,1.));
#1881=VECTOR('',#1880,1.);
#1882=CARTESIAN_POINT('',(5.99945018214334,0.0812250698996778,4.));
#1883=LINE('',#1882,#1881);
#1884=EDGE_CURVE('E285',#1134,#1555,#1883,.T.);
#1885=ORIENTED_EDGE('',*,*,#1884,.T.);
#1886=ORIENTED_EDGE('',*,*,#1556,.T.);
#1887=ORIENTED_EDGE('',*,*,#1866,.F.);
#1888=EDGE_LOOP('',(#1879,#1885,#1886,#1887));
#1889=FACE_BOUND('',#1888,.T.);
#1890=ADVANCED_FACE('F583',(#1889),#1878,.T.);
#1891=CARTESIAN_POINT('',(6.53912348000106,1.15302389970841,4.));
#1892=DIRECTION('',(0.,0.,1.));
#1893=DIRECTION('',(1.,0.,0.));
#1894=AXIS2_PLACEMENT_3D('',#1891,#1892,#1893);
#1895=CYLINDRICAL_SURFACE('',#1894,1.2);
#1896=DIRECTION('',(0.,0.,1.));
#1897=VECTOR('',#1896,1.);
#1898=CARTESIAN_POINT('',(5.6654196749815,1.97560621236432,4.));
#1899=LINE('',#1898,#1897);
#1900=EDGE_CURVE('E282',#1125,#1602,#1899,.T.);
#1901=ORIENTED_EDGE('',*,*,#1900,.T.);
#1902=ORIENTED_EDGE('',*,*,#1603,.F.);
#1903=ORIENTED_EDGE('',*,*,#1884,.F.);
#1904=ORIENTED_EDGE('',*,*,#1135,.F.);
#1905=EDGE_LOOP('',(#1901,#1902,#1903,#1904));
#1906=FACE_BOUND('',#1905,.T.);
#1907=ADVANCED_FACE('F578',(#1906),#1895,.F.);
#1908=CARTESIAN_POINT('',(0.,0.,4.));
#1909=DIRECTION('',(0.,0.,1.));
#1910=DIRECTION('',(1.,0.,0.));
#1911=AXIS2_PLACEMENT_3D('',#1908,#1909,#1910);
#1912=CYLINDRICAL_SURFACE('',#1911,6.);
#1913=ORIENTED_EDGE('',*,*,#1126,.T.);
#1914=DIRECTION('',(0.,0.,1.));
#1915=VECTOR('',#1914,1.);
#1916=CARTESIAN_POINT('',(4.54363500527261,3.91859425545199,4.));
#1917=LINE('',#1916,#1915);
#1918=EDGE_CURVE('E279',#1116,#1611,#1917,.T.);
#1919=ORIENTED_EDGE('',*,*,#1918,.T.);
#1920=ORIENTED_EDGE('',*,*,#1612,.T.);
#1921=ORIENTED_EDGE('',*,*,#1900,.F.);
#1922=EDGE_LOOP('',(#1913,#1919,#1920,#1921));
#1923=FACE_BOUND('',#1922,.T.);
#1924=ADVANCED_FACE('F575',(#1923),#1912,.T.);
#1925=CARTESIAN_POINT('',(4.26810972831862,5.08653510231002,4.));
#1926=DIRECTION('',(0.,0.,1.));
#1927=DIRECTION('',(1.,0.,0.));
#1928=AXIS2_PLACEMENT_3D('',#1925,#1926,#1927);
#1929=CYLINDRICAL_SURFACE('',#1928,1.2);
#1930=DIRECTION('',(0.,0.,1.));
#1931=VECTOR('',#1930,1.);
#1932=CARTESIAN_POINT('',(3.07006806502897,5.15506373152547,4.));
#1933=LINE('',#1932,#1931);
#1934=EDGE_CURVE('E276',#1107,#1650,#1933,.T.);
#1935=ORIENTED_EDGE('',*,*,#1934,.T.);
#1936=ORIENTED_EDGE('',*,*,#1651,.F.);
#1937=ORIENTED_EDGE('',*,*,#1918,.F.);
#1938=ORIENTED_EDGE('',*,*,#1117,.F.);
#1939=EDGE_LOOP('',(#1935,#1936,#1937,#1938));
#1940=FACE_BOUND('',#1939,.T.);
#1941=ADVANCED_FACE('F558',(#1940),#1929,.F.);
#1942=CARTESIAN_POINT('',(0.,0.,4.));
#1943=DIRECTION('',(0.,0.,1.));
#1944=DIRECTION('',(1.,0.,0.));
#1945=AXIS2_PLACEMENT_3D('',#1942,#1943,#1944);
#1946=CYLINDRICAL_SURFACE('',#1945,6.);
#1947=ORIENTED_EDGE('',*,*,#1108,.T.);
#1948=DIRECTION('',(0.,0.,1.));
#1949=VECTOR('',#1948,1.);
#1950=CARTESIAN_POINT('',(0.961802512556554,5.92240963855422,4.));
#1951=LINE('',#1950,#1949);
#1952=EDGE_CURVE('E273',#1098,#1659,#1951,.T.);
#1953=ORIENTED_EDGE('',*,*,#1952,.T.);
#1954=ORIENTED_EDGE('',*,*,#1660,.T.);
#1955=ORIENTED_EDGE('',*,*,#1934,.F.);
#1956=EDGE_LOOP('',(#1947,#1953,#1954,#1955));
#1957=FACE_BOUND('',#1956,.T.);
#1958=ADVANCED_FACE('F529',(#1957),#1946,.T.);
#1959=CARTESIAN_POINT('',(0.,6.64,4.));
#1960=DIRECTION('',(0.,0.,1.));
#1961=DIRECTION('',(1.,0.,0.));
#1962=AXIS2_PLACEMENT_3D('',#1959,#1960,#1961);
#1963=CYLINDRICAL_SURFACE('',#1962,1.2);
#1964=DIRECTION('',(0.,0.,1.));
#1965=VECTOR('',#1964,1.);
#1966=CARTESIAN_POINT('',(-0.961802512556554,5.92240963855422,4.));
#1967=LINE('',#1966,#1965);
#1968=EDGE_CURVE('E270',#1089,#1698,#1967,.T.);
#1969=ORIENTED_EDGE('',*,*,#1968,.T.);
#1970=ORIENTED_EDGE('',*,*,#1699,.F.);
#1971=ORIENTED_EDGE('',*,*,#1952,.F.);
#1972=ORIENTED_EDGE('',*,*,#1099,.F.);
#1973=EDGE_LOOP('',(#1969,#1970,#1971,#1972));
#1974=FACE_BOUND('',#1973,.T.);
#1975=ADVANCED_FACE('F524',(#1974),#1963,.F.);
#1976=CARTESIAN_POINT('',(0.,0.,4.));
#1977=DIRECTION('',(0.,0.,1.));
#1978=DIRECTION('',(1.,0.,0.));
#1979=AXIS2_PLACEMENT_3D('',#1976,#1977,#1978);
#1980=CYLINDRICAL_SURFACE('',#1979,6.);
#1981=ORIENTED_EDGE('',*,*,#1090,.T.);
#1982=DIRECTION('',(0.,0.,1.));
#1983=VECTOR('',#1982,1.);
#1984=CARTESIAN_POINT('',(-3.07006806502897,5.15506373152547,4.));
#1985=LINE('',#1984,#1983);
#1986=EDGE_CURVE('E267',#1080,#1707,#1985,.T.);
#1987=ORIENTED_EDGE('',*,*,#1986,.T.);
#1988=ORIENTED_EDGE('',*,*,#1708,.T.);
#1989=ORIENTED_EDGE('',*,*,#1968,.F.);
#1990=EDGE_LOOP('',(#1981,#1987,#1988,#1989));
#1991=FACE_BOUND('',#1990,.T.);
#1992=ADVANCED_FACE('F520',(#1991),#1980,.T.);
#1993=CARTESIAN_POINT('',(-4.26810972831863,5.08653510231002,4.));
#1994=DIRECTION('',(0.,0.,1.));
#1995=DIRECTION('',(1.,0.,0.));
#1996=AXIS2_PLACEMENT_3D('',#1993,#1994,#1995);
#1997=CYLINDRICAL_SURFACE('',#1996,1.2);
#1998=DIRECTION('',(0.,0.,1.));
#1999=VECTOR('',#1998,1.);
#2000=CARTESIAN_POINT('',(-4.54363500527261,3.918594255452,4.));
#2001=LINE('',#2000,#1999);
#2002=EDGE_CURVE('E264',#1071,#1307,#2001,.T.);
#2003=ORIENTED_EDGE('',*,*,#2002,.T.);
#2004=ORIENTED_EDGE('',*,*,#1745,.F.);
#2005=ORIENTED_EDGE('',*,*,#1986,.F.);
#2006=ORIENTED_EDGE('',*,*,#1081,.F.);
#2007=EDGE_LOOP('',(#2003,#2004,#2005,#2006));
#2008=FACE_BOUND('',#2007,.T.);
#2009=ADVANCED_FACE('F516',(#2008),#1997,.F.);
#2010=CARTESIAN_POINT('',(0.,0.,4.));
#2011=DIRECTION('',(0.,0.,1.));
#2012=DIRECTION('',(1.,0.,0.));
#2013=AXIS2_PLACEMENT_3D('',#2010,#2011,#2012);
#2014=CYLINDRICAL_SURFACE('',#2013,6.);
#2015=ORIENTED_EDGE('',*,*,#1072,.T.);
#2016=DIRECTION('',(0.,0.,1.));
#2017=VECTOR('',#2016,1.);
#2018=CARTESIAN_POINT('',(-5.6654196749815,1.97560621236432,4.));
#2019=LINE('',#2018,#2017);
#2020=EDGE_CURVE('E260',#1062,#1305,#2019,.T.);
#2021=ORIENTED_EDGE('',*,*,#2020,.T.);
#2022=ORIENTED_EDGE('',*,*,#1308,.T.);
#2023=ORIENTED_EDGE('',*,*,#2002,.F.);
#2024=EDGE_LOOP('',(#2015,#2021,#2022,#2023));
#2025=FACE_BOUND('',#2024,.T.);
#2026=ADVANCED_FACE('F495',(#2025),#2014,.T.);
#2027=CARTESIAN_POINT('',(-6.53912348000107,1.15302389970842,4.));
#2028=DIRECTION('',(0.,0.,1.));
#2029=DIRECTION('',(1.,0.,0.));
#2030=AXIS2_PLACEMENT_3D('',#2027,#2028,#2029);
#2031=CYLINDRICAL_SURFACE('',#2030,1.2);
#2032=DIRECTION('',(0.,0.,1.));
#2033=VECTOR('',#2032,1.);
#2034=CARTESIAN_POINT('',(-5.99945018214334,0.0812250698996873,4.));
#2035=LINE('',#2034,#2033);
#2036=EDGE_CURVE('E263',#1060,#1354,#2035,.T.);
#2037=ORIENTED_EDGE('',*,*,#2036,.T.);
#2038=ORIENTED_EDGE('',*,*,#1355,.F.);
#2039=ORIENTED_EDGE('',*,*,#2020,.F.);
#2040=ORIENTED_EDGE('',*,*,#1063,.F.);
#2041=EDGE_LOOP('',(#2037,#2038,#2039,#2040));
#2042=FACE_BOUND('',#2041,.T.);
#2043=ADVANCED_FACE('F410',(#2042),#2031,.F.);
#2044=CARTESIAN_POINT('',(0.,0.,4.));
#2045=DIRECTION('',(0.,0.,1.));
#2046=DIRECTION('',(1.,0.,0.));
#2047=AXIS2_PLACEMENT_3D('',#2044,#2045,#2046);
#2048=CYLINDRICAL_SURFACE('',#2047,6.);
#2049=ORIENTED_EDGE('',*,*,#1214,.T.);
#2050=ORIENTED_EDGE('',*,*,#1766,.T.);
#2051=ORIENTED_EDGE('',*,*,#1364,.T.);
#2052=ORIENTED_EDGE('',*,*,#2036,.F.);
#2053=EDGE_LOOP('',(#2049,#2050,#2051,#2052));
#2054=FACE_BOUND('',#2053,.T.);
#2055=ADVANCED_FACE('F408',(#2054),#2048,.T.);
#2056=CARTESIAN_POINT('',(-3.25,0.45,14.75));
#2057=DIRECTION('',(1.,0.,0.));
#2058=DIRECTION('',(0.,0.,-1.));
#2059=AXIS2_PLACEMENT_3D('',#2056,#2057,#2058);
#2060=PLANE('',#2059);
#2061=DIRECTION('',(0.,0.,-1.));
#2062=VECTOR('',#2061,1.);
#2063=CARTESIAN_POINT('',(-3.25,-0.45,14.75));
#2064=LINE('',#2063,#2062);
#2065=CARTESIAN_POINT('',(-3.25,-0.45,10.75));
#2066=VERTEX_POINT('',#2065);
#2067=EDGE_CURVE('E192',#61,#2066,#2064,.T.);
#2068=ORIENTED_EDGE('',*,*,#2067,.T.);
#2069=DIRECTION('',(0.,-1.,0.));
#2070=VECTOR('',#2069,1.);
#2071=CARTESIAN_POINT('',(-3.25,0.45,10.75));
#2072=LINE('',#2071,#2070);
#2073=CARTESIAN_POINT('',(-3.25,0.45,10.75));
#2074=VERTEX_POINT('',#2073);
#2075=EDGE_CURVE('E197',#2074,#2066,#2072,.T.);
#2076=ORIENTED_EDGE('',*,*,#2075,.F.);
#2077=DIRECTION('',(0.,0.,-1.));
#2078=VECTOR('',#2077,1.);
#2079=CARTESIAN_POINT('',(-3.25,0.45,14.75));
#2080=LINE('',#2079,#2078);
#2081=EDGE_CURVE('E236',#224,#2074,#2080,.T.);
#2082=ORIENTED_EDGE('',*,*,#2081,.F.);
#2083=ORIENTED_EDGE('',*,*,#225,.F.);
#2084=EDGE_LOOP('',(#2068,#2076,#2082,#2083));
#2085=FACE_BOUND('',#2084,.T.);
#2086=ADVANCED_FACE('F194',(#2085),#2060,.T.);
#2087=CARTESIAN_POINT('',(-3.05,-0.45,14.75));
#2088=DIRECTION('',(0.,0.,-1.));
#2089=DIRECTION('',(-1.,0.,0.));
#2090=AXIS2_PLACEMENT_3D('',#2087,#2088,#2089);
#2091=CYLINDRICAL_SURFACE('',#2090,0.2);
#2092=DIRECTION('',(0.,0.,-1.));
#2093=VECTOR('',#2092,1.);
#2094=CARTESIAN_POINT('',(-3.05,-0.65,14.75));
#2095=LINE('',#2094,#2093);
#2096=CARTESIAN_POINT('',(-3.05,-0.65,10.75));
#2097=VERTEX_POINT('',#2096);
#2098=EDGE_CURVE('E201',#59,#2097,#2095,.T.);
#2099=ORIENTED_EDGE('',*,*,#2098,.T.);
#2100=CARTESIAN_POINT('',(-3.05,-0.45,10.75));
#2101=DIRECTION('',(0.,0.,1.));
#2102=DIRECTION('',(1.,0.,0.));
#2103=AXIS2_PLACEMENT_3D('',#2100,#2101,#2102);
#2104=CIRCLE('',#2103,0.2);
#2105=EDGE_CURVE('E204',#2066,#2097,#2104,.T.);
#2106=ORIENTED_EDGE('',*,*,#2105,.F.);
#2107=ORIENTED_EDGE('',*,*,#2067,.F.);
#2108=ORIENTED_EDGE('',*,*,#62,.F.);
#2109=EDGE_LOOP('',(#2099,#2106,#2107,#2108));
#2110=FACE_BOUND('',#2109,.T.);
#2111=ADVANCED_FACE('F205',(#2110),#2091,.F.);
#2112=CARTESIAN_POINT('',(-3.05,-0.65,14.75));
#2113=DIRECTION('',(0.,1.,0.));
#2114=DIRECTION('',(-1.,0.,0.));
#2115=AXIS2_PLACEMENT_3D('',#2112,#2113,#2114);
#2116=PLANE('',#2115);
#2117=DIRECTION('',(0.,0.,-1.));
#2118=VECTOR('',#2117,1.);
#2119=CARTESIAN_POINT('',(3.05,-0.65,14.75));
#2120=LINE('',#2119,#2118);
#2121=CARTESIAN_POINT('',(3.05,-0.65,10.75));
#2122=VERTEX_POINT('',#2121);
#2123=EDGE_CURVE('E245',#657,#2122,#2120,.T.);
#2124=ORIENTED_EDGE('',*,*,#2123,.T.);
#2125=DIRECTION('',(1.,0.,0.));
#2126=VECTOR('',#2125,1.);
#2127=CARTESIAN_POINT('',(-3.05,-0.65,10.75));
#2128=LINE('',#2127,#2126);
#2129=EDGE_CURVE('E210',#2097,#2122,#2128,.T.);
#2130=ORIENTED_EDGE('',*,*,#2129,.F.);
#2131=ORIENTED_EDGE('',*,*,#2098,.F.);
#2132=ORIENTED_EDGE('',*,*,#845,.F.);
#2133=EDGE_LOOP('',(#2124,#2130,#2131,#2132));
#2134=FACE_BOUND('',#2133,.T.);
#2135=ADVANCED_FACE('F470',(#2134),#2116,.T.);
#2136=CARTESIAN_POINT('',(3.05,-0.45,14.75));
#2137=DIRECTION('',(0.,0.,-1.));
#2138=DIRECTION('',(-1.,0.,0.));
#2139=AXIS2_PLACEMENT_3D('',#2136,#2137,#2138);
#2140=CYLINDRICAL_SURFACE('',#2139,0.2);
#2141=DIRECTION('',(0.,0.,-1.));
#2142=VECTOR('',#2141,1.);
#2143=CARTESIAN_POINT('',(3.25,-0.45,14.75));
#2144=LINE('',#2143,#2142);
#2145=CARTESIAN_POINT('',(3.25,-0.45,10.75));
#2146=VERTEX_POINT('',#2145);
#2147=EDGE_CURVE('E243',#630,#2146,#2144,.T.);
#2148=ORIENTED_EDGE('',*,*,#2147,.T.);
#2149=CARTESIAN_POINT('',(3.05,-0.45,10.75));
#2150=DIRECTION('',(0.,0.,1.));
#2151=DIRECTION('',(1.,0.,0.));
#2152=AXIS2_PLACEMENT_3D('',#2149,#2150,#2151);
#2153=CIRCLE('',#2152,0.2);
#2154=EDGE_CURVE('E224',#2122,#2146,#2153,.T.);
#2155=ORIENTED_EDGE('',*,*,#2154,.F.);
#2156=ORIENTED_EDGE('',*,*,#2123,.F.);
#2157=ORIENTED_EDGE('',*,*,#658,.F.);
#2158=EDGE_LOOP('',(#2148,#2155,#2156,#2157));
#2159=FACE_BOUND('',#2158,.T.);
#2160=ADVANCED_FACE('F724',(#2159),#2140,.F.);
#2161=CARTESIAN_POINT('',(3.25,-0.45,14.75));
#2162=DIRECTION('',(-1.,0.,0.));
#2163=DIRECTION('',(0.,0.,1.));
#2164=AXIS2_PLACEMENT_3D('',#2161,#2162,#2163);
#2165=PLANE('',#2164);
#2166=DIRECTION('',(0.,0.,-1.));
#2167=VECTOR('',#2166,1.);
#2168=CARTESIAN_POINT('',(3.25,0.45,14.75));
#2169=LINE('',#2168,#2167);
#2170=CARTESIAN_POINT('',(3.25,0.45,10.75));
#2171=VERTEX_POINT('',#2170);
#2172=EDGE_CURVE('E241',#467,#2171,#2169,.T.);
#2173=ORIENTED_EDGE('',*,*,#2172,.T.);
#2174=DIRECTION('',(0.,1.,0.));
#2175=VECTOR('',#2174,1.);
#2176=CARTESIAN_POINT('',(3.25,-0.45,10.75));
#2177=LINE('',#2176,#2175);
#2178=EDGE_CURVE('E227',#2146,#2171,#2177,.T.);
#2179=ORIENTED_EDGE('',*,*,#2178,.F.);
#2180=ORIENTED_EDGE('',*,*,#2147,.F.);
#2181=ORIENTED_EDGE('',*,*,#631,.F.);
#2182=EDGE_LOOP('',(#2173,#2179,#2180,#2181));
#2183=FACE_BOUND('',#2182,.T.);
#2184=ADVANCED_FACE('F731',(#2183),#2165,.T.);
#2185=CARTESIAN_POINT('',(3.05,0.45,14.75));
#2186=DIRECTION('',(0.,0.,-1.));
#2187=DIRECTION('',(-1.,0.,0.));
#2188=AXIS2_PLACEMENT_3D('',#2185,#2186,#2187);
#2189=CYLINDRICAL_SURFACE('',#2188,0.2);
#2190=DIRECTION('',(0.,0.,-1.));
#2191=VECTOR('',#2190,1.);
#2192=CARTESIAN_POINT('',(3.05,0.65,14.75));
#2193=LINE('',#2192,#2191);
#2194=CARTESIAN_POINT('',(3.05,0.65,10.75));
#2195=VERTEX_POINT('',#2194);
#2196=EDGE_CURVE('E239',#440,#2195,#2193,.T.);
#2197=ORIENTED_EDGE('',*,*,#2196,.T.);
#2198=CARTESIAN_POINT('',(3.05,0.45,10.75));
#2199=DIRECTION('',(0.,0.,1.));
#2200=DIRECTION('',(1.,0.,0.));
#2201=AXIS2_PLACEMENT_3D('',#2198,#2199,#2200);
#2202=CIRCLE('',#2201,0.2);
#2203=EDGE_CURVE('E230',#2171,#2195,#2202,.T.);
#2204=ORIENTED_EDGE('',*,*,#2203,.F.);
#2205=ORIENTED_EDGE('',*,*,#2172,.F.);
#2206=ORIENTED_EDGE('',*,*,#468,.F.);
#2207=EDGE_LOOP('',(#2197,#2204,#2205,#2206));
#2208=FACE_BOUND('',#2207,.T.);
#2209=ADVANCED_FACE('F738',(#2208),#2189,.F.);
#2210=CARTESIAN_POINT('',(3.05,0.65,14.75));
#2211=DIRECTION('',(0.,-1.,0.));
#2212=DIRECTION('',(1.,0.,0.));
#2213=AXIS2_PLACEMENT_3D('',#2210,#2211,#2212);
#2214=PLANE('',#2213);
#2215=ORIENTED_EDGE('',*,*,#441,.F.);
#2216=DIRECTION('',(0.,0.,-1.));
#2217=VECTOR('',#2216,1.);
#2218=CARTESIAN_POINT('',(-3.05,0.65,14.75));
#2219=LINE('',#2218,#2217);
#2220=CARTESIAN_POINT('',(-3.05,0.65,10.75));
#2221=VERTEX_POINT('',#2220);
#2222=EDGE_CURVE('E34',#251,#2221,#2219,.T.);
#2223=ORIENTED_EDGE('',*,*,#2222,.T.);
#2224=DIRECTION('',(-1.,0.,0.));
#2225=VECTOR('',#2224,1.);
#2226=CARTESIAN_POINT('',(3.05,0.65,10.75));
#2227=LINE('',#2226,#2225);
#2228=EDGE_CURVE('E233',#2195,#2221,#2227,.T.);
#2229=ORIENTED_EDGE('',*,*,#2228,.F.);
#2230=ORIENTED_EDGE('',*,*,#2196,.F.);
#2231=EDGE_LOOP('',(#2215,#2223,#2229,#2230));
#2232=FACE_BOUND('',#2231,.T.);
#2233=ADVANCED_FACE('F745',(#2232),#2214,.T.);
#2234=CARTESIAN_POINT('',(-3.05,0.45,14.75));
#2235=DIRECTION('',(0.,0.,-1.));
#2236=DIRECTION('',(-1.,0.,0.));
#2237=AXIS2_PLACEMENT_3D('',#2234,#2235,#2236);
#2238=CYLINDRICAL_SURFACE('',#2237,0.2);
#2239=ORIENTED_EDGE('',*,*,#2081,.T.);
#2240=CARTESIAN_POINT('',(-3.05,0.45,10.75));
#2241=DIRECTION('',(0.,0.,1.));
#2242=DIRECTION('',(1.,0.,0.));
#2243=AXIS2_PLACEMENT_3D('',#2240,#2241,#2242);
#2244=CIRCLE('',#2243,0.2);
#2245=EDGE_CURVE('E215',#2221,#2074,#2244,.T.);
#2246=ORIENTED_EDGE('',*,*,#2245,.F.);
#2247=ORIENTED_EDGE('',*,*,#2222,.F.);
#2248=ORIENTED_EDGE('',*,*,#252,.F.);
#2249=EDGE_LOOP('',(#2239,#2246,#2247,#2248));
#2250=FACE_BOUND('',#2249,.T.);
#2251=ADVANCED_FACE('F752',(#2250),#2238,.F.);
#2252=CARTESIAN_POINT('',(-3.05,-0.45,10.75));
#2253=DIRECTION('',(0.,0.,1.));
#2254=DIRECTION('',(1.,0.,0.));
#2255=AXIS2_PLACEMENT_3D('',#2252,#2253,#2254);
#2256=PLANE('',#2255);
#2257=ORIENTED_EDGE('',*,*,#2075,.T.);
#2258=ORIENTED_EDGE('',*,*,#2105,.T.);
#2259=ORIENTED_EDGE('',*,*,#2129,.T.);
#2260=ORIENTED_EDGE('',*,*,#2154,.T.);
#2261=ORIENTED_EDGE('',*,*,#2178,.T.);
#2262=ORIENTED_EDGE('',*,*,#2203,.T.);
#2263=ORIENTED_EDGE('',*,*,#2228,.T.);
#2264=ORIENTED_EDGE('',*,*,#2245,.T.);
#2265=EDGE_LOOP('',(#2257,#2258,#2259,#2260,#2261,#2262,#2263,#2264));
#2266=FACE_BOUND('',#2265,.T.);
#2267=ADVANCED_FACE('F213',(#2266),#2256,.T.);
#2268=CARTESIAN_POINT('',(0.,0.,6.));
#2269=DIRECTION('',(0.,0.,-1.));
#2270=DIRECTION('',(-1.,0.,0.));
#2271=AXIS2_PLACEMENT_3D('',#2268,#2269,#2270);
#2272=CYLINDRICAL_SURFACE('',#2271,1.5);
#2273=CARTESIAN_POINT('',(0.,0.,6.));
#2274=DIRECTION('',(0.,0.,-1.));
#2275=DIRECTION('',(-1.,0.,0.));
#2276=AXIS2_PLACEMENT_3D('',#2273,#2274,#2275);
#2277=CIRCLE('',#2276,1.5);
#2278=CARTESIAN_POINT('',(-1.5,0.,6.));
#2279=VERTEX_POINT('',#2278);
#2280=EDGE_CURVE('E216',#2279,#2279,#2277,.T.);
#2281=ORIENTED_EDGE('',*,*,#2280,.F.);
#2282=EDGE_LOOP('',(#2281));
#2283=FACE_BOUND('',#2282,.T.);
#2284=ORIENTED_EDGE('',*,*,#873,.T.);
#2285=EDGE_LOOP('',(#2284));
#2286=FACE_BOUND('',#2285,.T.);
#2287=ADVANCED_FACE('F764',(#2283,#2286),#2272,.F.);
#2288=CARTESIAN_POINT('',(0.,0.,6.));
#2289=DIRECTION('',(0.,0.,-1.));
#2290=DIRECTION('',(-1.,0.,0.));
#2291=AXIS2_PLACEMENT_3D('',#2288,#2289,#2290);
#2292=PLANE('',#2291);
#2293=ORIENTED_EDGE('',*,*,#2280,.T.);
#2294=EDGE_LOOP('',(#2293));
#2295=FACE_BOUND('',#2294,.T.);
#2296=ADVANCED_FACE('F771',(#2295),#2292,.T.);
#2297=CLOSED_SHELL('',(#849,#877,#897,#917,#937,#957,#977,#997,#1017,#1037,#1218,#1238,#1258,
#1270,#1290,#1749,#1771,#1788,#1805,#1822,#1839,#1856,#1873,#1890,#1907,#1924,#1941,#1958,#1975,
#1992,#2009,#2026,#2043,#2055,#2086,#2111,#2135,#2160,#2184,#2209,#2233,#2251,#2267,#2287,#2296));
#2298=MANIFOLD_SOLID_BREP('B1',#2297);
#2299=ADVANCED_BREP_SHAPE_REPRESENTATION('',(#18,#2298),#14);
#2300=SHAPE_DEFINITION_REPRESENTATION(#9,#2299);
ENDSEC;
END-ISO-10303-21;
